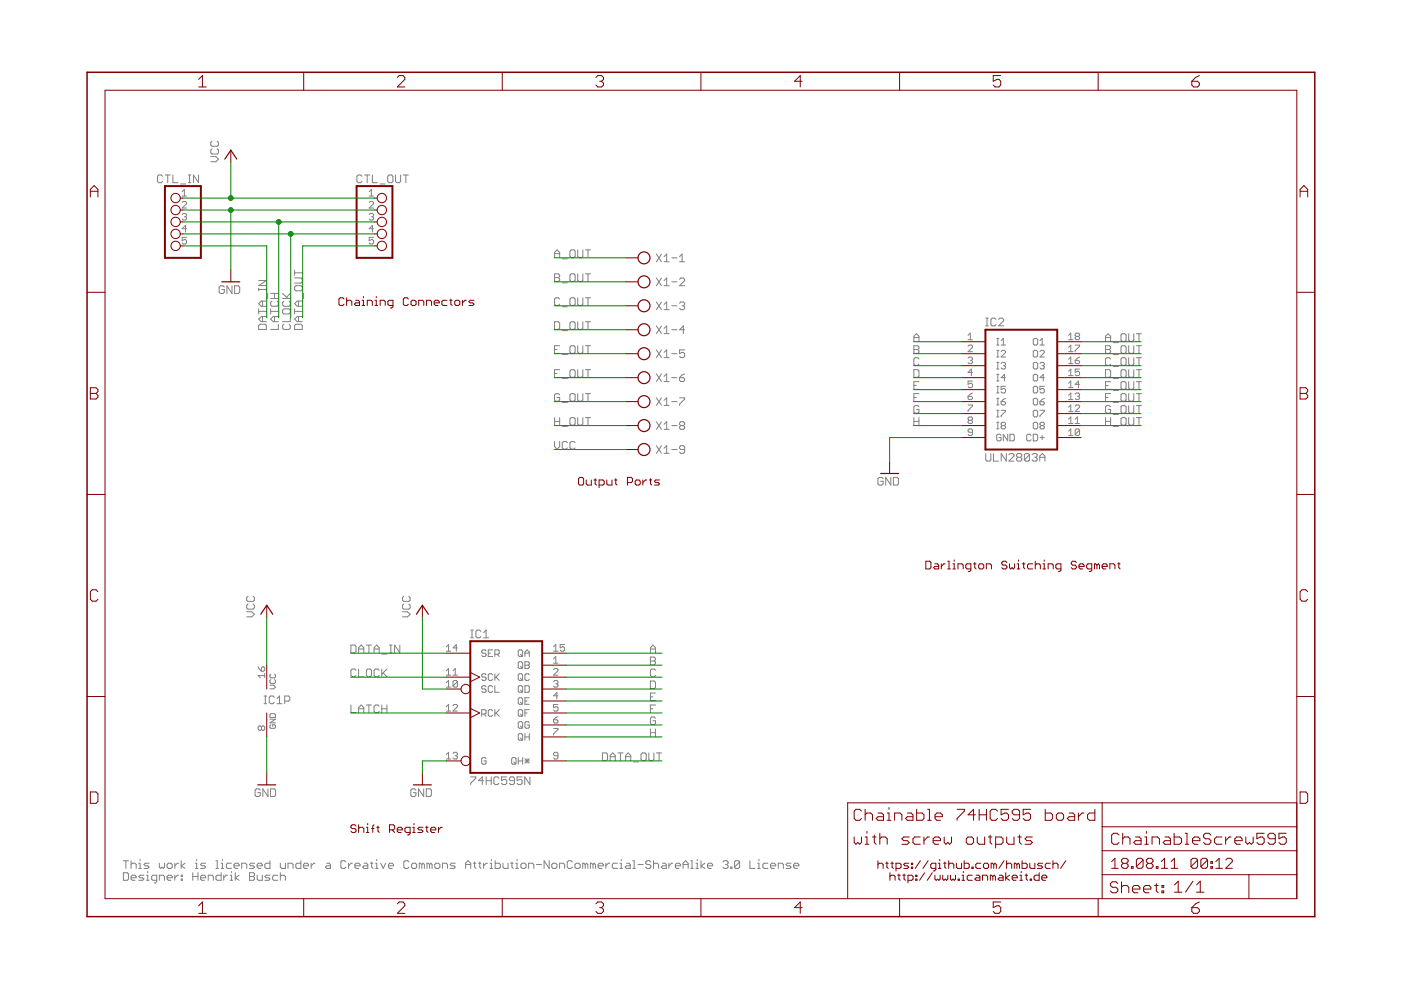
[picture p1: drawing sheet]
<svg xmlns="http://www.w3.org/2000/svg" width="297mm" height="210mm" viewBox="0 0 297 210" stroke-linecap="round" stroke-linejoin="round" font-family="sans-serif">
<g fill="#808080" stroke="#808080" stroke-width=".21">
<path d="M99.8 164.7h1.1z"/>
<path d="M100.9 164.7v.3z"/>
<path d="M100.9 165l-1.1 1.1z"/>
<path d="M99.8 166.1v.2z"/>
<path d="M102.3 164.7v1.6z"/>
<path d="M101.4 165.5l.9-.8z"/>
<path d="M101.4 165.5h1.1z"/>
<path d="M103.1 164.7v1.6z"/>
<path d="M103.1 165.5h1.1z"/>
<path d="M104.2 164.7v1.6z"/>
<path d="M105.5 164.7l.3 .3z"/>
<path d="M105 164.7h.5z"/>
<path d="M105 164.7l-.3 .3z"/>
<path d="M104.7 165v1.1z"/>
<path d="M104.7 166.1l.3 .2z"/>
<path d="M105 166.3h.5z"/>
<path d="M105.5 166.3l.3-.2z"/>
<path d="M106.3 164.7h1.1z"/>
<path d="M106.3 164.7v.8z"/>
<path d="M106.3 165.5l.6-.3z"/>
<path d="M106.9 165.2h.3z"/>
<path d="M107.2 165.2l.2 .3z"/>
<path d="M107.4 165.5v.6z"/>
<path d="M107.4 166.1l-.2 .2z"/>
<path d="M106.6 166.3h.6z"/>
<path d="M106.3 166.1l.3 .2z"/>
<path d="M108 166.1l.2 .2z"/>
<path d="M108.2 166.3h.6z"/>
<path d="M108.8 166.3l.3-.2z"/>
<path d="M109.1 165v1.1z"/>
<path d="M108.8 164.7l.3 .3z"/>
<path d="M108.2 164.7h.6z"/>
<path d="M108.2 164.7l-.2 .3z"/>
<path d="M108 165v.2z"/>
<path d="M108 165.2l.2 .3z"/>
<path d="M108.2 165.5h.9z"/>
<path d="M109.6 164.7h1.1z"/>
<path d="M109.6 164.7v.8z"/>
<path d="M109.6 165.5l.6-.3z"/>
<path d="M110.2 165.2h.2z"/>
<path d="M110.4 165.2l.3 .3z"/>
<path d="M110.7 165.5v.6z"/>
<path d="M110.7 166.1l-.3 .2z"/>
<path d="M109.9 166.3h.5z"/>
<path d="M109.6 166.1l.3 .2z"/>
<path d="M111.3 164.7v1.6z"/>
<path d="M111.3 164.7l1.1 1.6z"/>
<path d="M112.4 164.7v1.6z"/>
<path d="M54.9 167.3l.3 .2z"/>
<path d="M54.4 167.3h.5z"/>
<path d="M54.4 167.3l-.3 .2z"/>
<path d="M54.1 167.5v1.1z"/>
<path d="M54.1 168.6l.3 .3z"/>
<path d="M54.4 168.9h.5z"/>
<path d="M54.9 168.9l.3-.3z"/>
<path d="M55.2 168.1v.5z"/>
<path d="M54.6 168.1h.6z"/>
<path d="M55.7 167.3v1.6z"/>
<path d="M55.7 167.3l1.1 1.6z"/>
<path d="M56.8 167.3v1.6z"/>
<path d="M57.4 167.3v1.6z"/>
<path d="M57.4 168.9h.8z"/>
<path d="M58.4 168.6l-.2 .3z"/>
<path d="M58.4 167.5v1.1z"/>
<path d="M58.2 167.3l.2 .2z"/>
<path d="M57.4 167.3h.8z"/>
<path d="M47.3 60.6l.3 .3z"/>
<path d="M46.7 60.6h.6z"/>
<path d="M46.7 60.6l-.2 .3z"/>
<path d="M46.5 60.9v1.1z"/>
<path d="M46.5 62l.2 .2z"/>
<path d="M46.7 62.2h.6z"/>
<path d="M47.3 62.2l.3-.2z"/>
<path d="M47.6 61.4v.6z"/>
<path d="M47 61.4h.6z"/>
<path d="M48.1 60.6v1.6z"/>
<path d="M48.1 60.6l1.1 1.6z"/>
<path d="M49.2 60.6v1.6z"/>
<path d="M49.7 60.6v1.6z"/>
<path d="M49.7 62.2h.8z"/>
<path d="M50.5 62.2l.3-.2z"/>
<path d="M50.8 60.9v1.1z"/>
<path d="M50.5 60.6l.3 .3z"/>
<path d="M49.7 60.6h.8z"/>
<path d="M52.3 130.8h1.1z"/>
<path d="M53.4 130.8l.5-.6z"/>
<path d="M53.4 129.7l.5 .5z"/>
<path d="M52.3 129.7h1.1z"/>
<path d="M52.6 128.1l-.3 .2z"/>
<path d="M52.3 128.3v.6z"/>
<path d="M52.3 128.9l.3 .3z"/>
<path d="M52.6 129.2h1.1z"/>
<path d="M53.7 129.2l.2-.3z"/>
<path d="M53.9 128.3v.6z"/>
<path d="M53.7 128.1l.2 .2z"/>
<path d="M52.6 126.4l-.3 .3z"/>
<path d="M52.3 126.7v.6z"/>
<path d="M52.3 127.3l.3 .2z"/>
<path d="M52.6 127.5h1.1z"/>
<path d="M53.7 127.5l.2-.2z"/>
<path d="M53.9 126.7v.6z"/>
<path d="M53.7 126.4l.2 .3z"/>
<path d="M44.7 34.3h1.1z"/>
<path d="M46.3 33.7l-.5 .6z"/>
<path d="M45.8 33.2l.5 .5z"/>
<path d="M44.7 33.2h1.1z"/>
<path d="M45 31.6l-.3 .2z"/>
<path d="M44.7 31.8v.6z"/>
<path d="M44.7 32.4l.3 .3z"/>
<path d="M45 32.7h1z"/>
<path d="M46 32.7l.3-.3z"/>
<path d="M46.3 31.8v.6z"/>
<path d="M46 31.6l.3 .2z"/>
<path d="M44.7 30.2l.3-.3z"/>
<path d="M44.7 30.2v.6z"/>
<path d="M44.7 30.8l.3 .2z"/>
<path d="M45 31h1z"/>
<path d="M46 31l.3-.2z"/>
<path d="M46.3 30.2v.6z"/>
<path d="M46 29.9l.3 .3z"/>
<path d="M87.9 167.3l.3 .2z"/>
<path d="M87.4 167.3h.5z"/>
<path d="M87.4 167.3l-.3 .2z"/>
<path d="M87.1 167.5v1.1z"/>
<path d="M87.1 168.6l.3 .3z"/>
<path d="M87.4 168.9h.5z"/>
<path d="M88.2 168.6l-.3 .3z"/>
<path d="M88.2 168.1v.5z"/>
<path d="M87.6 168.1h.6z"/>
<path d="M88.7 167.3v1.6z"/>
<path d="M88.7 167.3l1.1 1.6z"/>
<path d="M89.8 167.3v1.6z"/>
<path d="M90.4 167.3v1.6z"/>
<path d="M90.4 168.9h.8z"/>
<path d="M91.2 168.9l.3-.3z"/>
<path d="M91.5 167.5v1.1z"/>
<path d="M91.2 167.3l.3 .2z"/>
<path d="M90.4 167.3h.8z"/>
<path d="M85.3 130.8h1.1z"/>
<path d="M86.4 130.8l.6-.6z"/>
<path d="M86.4 129.7l.6 .5z"/>
<path d="M85.3 129.7h1.1z"/>
<path d="M85.6 128.1l-.3 .2z"/>
<path d="M85.3 128.3v.6z"/>
<path d="M85.3 128.9l.3 .3z"/>
<path d="M85.6 129.2h1.1z"/>
<path d="M86.7 129.2l.3-.3z"/>
<path d="M87 128.3v.6z"/>
<path d="M86.7 128.1l.3 .2z"/>
<path d="M85.6 126.4l-.3 .3z"/>
<path d="M85.3 126.7v.6z"/>
<path d="M85.3 127.3l.3 .2z"/>
<path d="M85.6 127.5h1.1z"/>
<path d="M86.7 127.5l.3-.2z"/>
<path d="M87 126.7v.6z"/>
<path d="M86.7 126.4l.3 .3z"/>
<path d="M209 96.2v1.3z"/>
<path d="M209 97.5l.3 .3z"/>
<path d="M209.3 97.8h.5z"/>
<path d="M210.1 97.5l-.3 .3z"/>
<path d="M210.1 96.2v1.3z"/>
<path d="M210.6 96.2v1.6z"/>
<path d="M210.6 97.8h1.1z"/>
<path d="M212.3 96.2v1.6z"/>
<path d="M212.3 96.2l1.1 1.6z"/>
<path d="M213.4 96.2v1.6z"/>
<path d="M213.9 97.8h1.1z"/>
<path d="M213.9 97.8l1.1-1.1z"/>
<path d="M215 96.4v.3z"/>
<path d="M214.7 96.2l.3 .2z"/>
<path d="M214.2 96.2h.5z"/>
<path d="M213.9 96.4l.3-.2z"/>
<path d="M215.5 96.4l.3-.2z"/>
<path d="M215.8 96.2h.6z"/>
<path d="M216.4 96.2l.2 .2z"/>
<path d="M216.6 96.4v.3z"/>
<path d="M216.6 96.7l-.2 .3z"/>
<path d="M216.4 97l.2 .2z"/>
<path d="M216.6 97.2v.3z"/>
<path d="M216.4 97.8l.2-.3z"/>
<path d="M215.8 97.8h.6z"/>
<path d="M215.5 97.5l.3 .3z"/>
<path d="M215.5 97.2v.3z"/>
<path d="M215.5 97.2l.3-.2z"/>
<path d="M215.5 96.7l.3 .3z"/>
<path d="M215.5 96.4v.3z"/>
<path d="M215.8 97h.6z"/>
<path d="M217.2 96.4v1.1z"/>
<path d="M217.2 96.4l.3-.2z"/>
<path d="M217.5 96.2h.5z"/>
<path d="M218 96.2l.3 .2z"/>
<path d="M218.3 96.4v1.1z"/>
<path d="M218 97.8l.3-.3z"/>
<path d="M217.5 97.8h.5z"/>
<path d="M217.2 97.5l.3 .3z"/>
<path d="M218.3 96.4l-1.1 1.1z"/>
<path d="M218.8 96.4l.3-.2z"/>
<path d="M219.1 96.2h.5z"/>
<path d="M219.6 96.2l.3 .2z"/>
<path d="M219.9 96.4v.3z"/>
<path d="M219.9 96.7l-.3 .3z"/>
<path d="M219.4 97h.2z"/>
<path d="M219.6 97l.3 .2z"/>
<path d="M219.9 97.2v.3z"/>
<path d="M219.9 97.5l-.3 .3z"/>
<path d="M219.1 97.8h.5z"/>
<path d="M218.8 97.5l.3 .3z"/>
<path d="M220.4 96.7v1.1z"/>
<path d="M220.4 96.7l.6-.5z"/>
<path d="M221 96.2l.5 .5z"/>
<path d="M221.5 96.7v1.1z"/>
<path d="M220.4 97h1.1z"/>
<path d="M187 101.2l.2 .3z"/>
<path d="M186.4 101.2h.6z"/>
<path d="M186.4 101.2l-.3 .3z"/>
<path d="M186.1 101.5v1.1z"/>
<path d="M186.1 102.6l.3 .2z"/>
<path d="M186.4 102.8h.6z"/>
<path d="M187 102.8l.2-.2z"/>
<path d="M187.2 102v.6z"/>
<path d="M186.7 102h.5z"/>
<path d="M187.8 101.2v1.6z"/>
<path d="M187.8 101.2l1.1 1.6z"/>
<path d="M188.9 101.2v1.6z"/>
<path d="M189.4 101.2v1.6z"/>
<path d="M189.4 102.8h.8z"/>
<path d="M190.2 102.8l.3-.2z"/>
<path d="M190.5 101.5v1.1z"/>
<path d="M190.2 101.2l.3 .3z"/>
<path d="M189.4 101.2h.8z"/>
<path d="M26.7 182.5v1.6z"/>
<path d="M26.2 182.5h1z"/>
<path d="M27.8 182.5v1.6z"/>
<path d="M27.8 183.3l.3-.3z"/>
<path d="M28.1 183h.5z"/>
<path d="M28.6 183l.3 .3z"/>
<path d="M28.9 183.3v.8z"/>
<path d="M29.4 183h.3z"/>
<path d="M29.7 183v1.1z"/>
<path d="M29.4 184.1h.6z"/>
<path d="M29.7 182.2v.3z"/>
<path d="M30.5 184.1h.8z"/>
<path d="M31.3 184.1l.3-.2z"/>
<path d="M31.3 183.6l.3 .3z"/>
<path d="M30.8 183.6h.5z"/>
<path d="M30.5 183.3l.3 .3z"/>
<path d="M30.5 183.3l.3-.3z"/>
<path d="M30.8 183h.8z"/>
<path d="M33.8 183v.9z"/>
<path d="M33.8 183.9l.3 .2z"/>
<path d="M34.3 183.9l-.2 .2z"/>
<path d="M34.3 183.9l.3 .2z"/>
<path d="M34.6 184.1l.3-.2z"/>
<path d="M34.9 183v.9z"/>
<path d="M35.7 184.1h.5z"/>
<path d="M36.5 183.9l-.3 .2z"/>
<path d="M36.5 183.3v.6z"/>
<path d="M36.2 183l.3 .3z"/>
<path d="M35.7 183h.5z"/>
<path d="M35.7 183l-.3 .3z"/>
<path d="M35.4 183.3v.6z"/>
<path d="M35.4 183.9l.3 .2z"/>
<path d="M37.1 183v1.1z"/>
<path d="M37.1 183.6l.5-.6z"/>
<path d="M37.6 183h.3z"/>
<path d="M38.4 182.5v1.6z"/>
<path d="M38.4 183.6l.8 .5z"/>
<path d="M38.4 183.6l.8-.6z"/>
<path d="M41.4 183h.3z"/>
<path d="M41.7 183v1.1z"/>
<path d="M41.4 184.1h.6z"/>
<path d="M41.7 182.2v.3z"/>
<path d="M42.5 184.1h.8z"/>
<path d="M43.6 183.9l-.3 .2z"/>
<path d="M43.3 183.6l.3 .3z"/>
<path d="M42.8 183.6h.5z"/>
<path d="M42.5 183.3l.3 .3z"/>
<path d="M42.5 183.3l.3-.3z"/>
<path d="M42.8 183h.8z"/>
<path d="M45.8 182.5h.3z"/>
<path d="M46.1 182.5v1.6z"/>
<path d="M45.8 184.1h.5z"/>
<path d="M46.9 183h.3z"/>
<path d="M47.2 183v1.1z"/>
<path d="M46.9 184.1h.5z"/>
<path d="M47.2 182.2v.3z"/>
<path d="M48.2 183h.9z"/>
<path d="M48.2 183l-.2 .3z"/>
<path d="M48 183.3v.6z"/>
<path d="M48 183.9l.2 .2z"/>
<path d="M48.2 184.1h.9z"/>
<path d="M49.9 184.1h.5z"/>
<path d="M49.6 183.9l.3 .2z"/>
<path d="M49.6 183.3v.6z"/>
<path d="M49.6 183.3l.3-.3z"/>
<path d="M49.9 183h.5z"/>
<path d="M50.4 183l.3 .3z"/>
<path d="M50.7 183.3v.3z"/>
<path d="M49.6 183.6h1.1z"/>
<path d="M51.2 183v1.1z"/>
<path d="M51.2 183h.9z"/>
<path d="M52.1 183l.2 .3z"/>
<path d="M52.3 183.3v.8z"/>
<path d="M52.9 184.1h.8z"/>
<path d="M54 183.9l-.3 .2z"/>
<path d="M53.7 183.6l.3 .3z"/>
<path d="M53.1 183.6h.6z"/>
<path d="M52.9 183.3l.2 .3z"/>
<path d="M53.1 183l-.2 .3z"/>
<path d="M53.1 183h.9z"/>
<path d="M54.8 184.1h.5z"/>
<path d="M54.5 183.9l.3 .2z"/>
<path d="M54.5 183.3v.6z"/>
<path d="M54.5 183.3l.3-.3z"/>
<path d="M54.8 183h.5z"/>
<path d="M55.3 183l.3 .3z"/>
<path d="M55.6 183.3v.3z"/>
<path d="M54.5 183.6h1.1z"/>
<path d="M57.2 182.5v1.6z"/>
<path d="M56.4 184.1h.8z"/>
<path d="M56.2 183.9l.2 .2z"/>
<path d="M56.2 183.3v.6z"/>
<path d="M56.2 183.3l.2-.3z"/>
<path d="M56.4 183h.8z"/>
<path d="M59.4 183v.9z"/>
<path d="M59.4 183.9l.3 .2z"/>
<path d="M59.7 184.1h.8z"/>
<path d="M60.5 183v1.1z"/>
<path d="M61.1 183v1.1z"/>
<path d="M61.1 183h.8z"/>
<path d="M61.9 183l.2 .3z"/>
<path d="M62.1 183.3v.8z"/>
<path d="M63.8 182.5v1.6z"/>
<path d="M63 184.1h.8z"/>
<path d="M62.7 183.9l.3 .2z"/>
<path d="M62.7 183.3v.6z"/>
<path d="M63 183l-.3 .3z"/>
<path d="M63 183h.8z"/>
<path d="M64.6 184.1h.5z"/>
<path d="M64.3 183.9l.3 .2z"/>
<path d="M64.3 183.3v.6z"/>
<path d="M64.3 183.3l.3-.3z"/>
<path d="M64.6 183h.5z"/>
<path d="M65.1 183l.3 .3z"/>
<path d="M65.4 183.3v.3z"/>
<path d="M64.3 183.6h1.1z"/>
<path d="M66 183v1.1z"/>
<path d="M66 183.6l.5-.6z"/>
<path d="M66.5 183h.3z"/>
<path d="M69.3 183h.5z"/>
<path d="M69.8 183l.3 .3z"/>
<path d="M70.1 183.3v.8z"/>
<path d="M69.3 184.1h.8z"/>
<path d="M69 183.9l.3 .2z"/>
<path d="M69 183.9l.3-.3z"/>
<path d="M69.3 183.6h.8z"/>
<path d="M73.1 182.5l.2 .2z"/>
<path d="M72.5 182.5h.6z"/>
<path d="M72.3 182.7l.2-.2z"/>
<path d="M72.3 182.7v1.2z"/>
<path d="M72.3 183.9l.2 .2z"/>
<path d="M72.5 184.1h.6z"/>
<path d="M73.1 184.1l.2-.2z"/>
<path d="M73.9 183v1.1z"/>
<path d="M73.9 183.6l.5-.6z"/>
<path d="M74.4 183h.3z"/>
<path d="M75.5 184.1h.6z"/>
<path d="M75.2 183.9l.3 .2z"/>
<path d="M75.2 183.3v.6z"/>
<path d="M75.2 183.3l.3-.3z"/>
<path d="M75.5 183h.6z"/>
<path d="M76.1 183l.2 .3z"/>
<path d="M76.3 183.3v.3z"/>
<path d="M75.2 183.6h1.1z"/>
<path d="M77.2 183h.5z"/>
<path d="M77.7 183l.3 .3z"/>
<path d="M78 183.3v.8z"/>
<path d="M77.2 184.1h.8z"/>
<path d="M76.9 183.9l.3 .2z"/>
<path d="M76.9 183.9l.3-.3z"/>
<path d="M77.2 183.6h.8z"/>
<path d="M78.8 182.7v1.2z"/>
<path d="M78.8 183.9l.3 .2z"/>
<path d="M78.5 183h.6z"/>
<path d="M79.6 183h.3z"/>
<path d="M79.9 183v1.1z"/>
<path d="M79.6 184.1h.6z"/>
<path d="M79.9 182.2v.3z"/>
<path d="M80.7 183l.6 1.1z"/>
<path d="M81.8 183l-.5 1.1z"/>
<path d="M82.6 184.1h.6z"/>
<path d="M82.4 183.9l.2 .2z"/>
<path d="M82.4 183.3v.6z"/>
<path d="M82.6 183l-.2 .3z"/>
<path d="M82.6 183h.6z"/>
<path d="M83.2 183l.2 .3z"/>
<path d="M83.4 183.3v.3z"/>
<path d="M82.4 183.6h1z"/>
<path d="M86.4 182.5l.3 .2z"/>
<path d="M85.9 182.5h.5z"/>
<path d="M85.6 182.7l.3-.2z"/>
<path d="M85.6 182.7v1.2z"/>
<path d="M85.6 183.9l.3 .2z"/>
<path d="M85.9 184.1h.5z"/>
<path d="M86.7 183.9l-.3 .2z"/>
<path d="M87.5 184.1h.6z"/>
<path d="M88.1 184.1l.2-.2z"/>
<path d="M88.3 183.3v.6z"/>
<path d="M88.1 183l.2 .3z"/>
<path d="M87.5 183h.6z"/>
<path d="M87.5 183l-.2 .3z"/>
<path d="M87.3 183.3v.6z"/>
<path d="M87.3 183.9l.2 .2z"/>
<path d="M88.9 183v1.1z"/>
<path d="M88.9 183h.3z"/>
<path d="M89.2 183l.2 .3z"/>
<path d="M89.4 183.3v.8z"/>
<path d="M89.4 183.3l.3-.3z"/>
<path d="M89.7 183l.3 .3z"/>
<path d="M90 183.3v.8z"/>
<path d="M90.5 183v1.1z"/>
<path d="M90.5 183h.3z"/>
<path d="M90.8 183l.3 .3z"/>
<path d="M91.1 183.3v.8z"/>
<path d="M91.1 183.3l.3-.3z"/>
<path d="M91.4 183l.2 .3z"/>
<path d="M91.6 183.3v.8z"/>
<path d="M92.4 184.1h.6z"/>
<path d="M93.3 183.9l-.3 .2z"/>
<path d="M93.3 183.3v.6z"/>
<path d="M93 183l.3 .3z"/>
<path d="M92.4 183h.6z"/>
<path d="M92.4 183l-.2 .3z"/>
<path d="M92.2 183.3v.6z"/>
<path d="M92.2 183.9l.2 .2z"/>
<path d="M93.8 183v1.1z"/>
<path d="M93.8 183h.8z"/>
<path d="M94.6 183l.3 .3z"/>
<path d="M94.9 183.3v.8z"/>
<path d="M95.4 184.1h.9z"/>
<path d="M96.5 183.9l-.2 .2z"/>
<path d="M96.3 183.6l.2 .3z"/>
<path d="M95.7 183.6h.6z"/>
<path d="M95.4 183.3l.3 .3z"/>
<path d="M95.4 183.3l.3-.3z"/>
<path d="M95.7 183h.8z"/>
<path d="M98.7 183v1.1z"/>
<path d="M99.2 182.5l-.5 .5z"/>
<path d="M99.2 182.5l.6 .5z"/>
<path d="M99.8 183v1.1z"/>
<path d="M98.7 183.3h1.1z"/>
<path d="M100.6 182.7v1.2z"/>
<path d="M100.6 183.9l.3 .2z"/>
<path d="M100.3 183h.6z"/>
<path d="M101.7 182.7v1.2z"/>
<path d="M101.7 183.9l.3 .2z"/>
<path d="M101.5 183h.5z"/>
<path d="M102.5 183v1.1z"/>
<path d="M102.5 183.6l.6-.6z"/>
<path d="M103.1 183h.3z"/>
<path d="M103.9 183h.3z"/>
<path d="M104.2 183v1.1z"/>
<path d="M103.9 184.1h.5z"/>
<path d="M104.2 182.2v.3z"/>
<path d="M105 182.5v1.6z"/>
<path d="M105 184.1h.8z"/>
<path d="M105.8 184.1l.3-.2z"/>
<path d="M106.1 183.3v.6z"/>
<path d="M105.8 183l.3 .3z"/>
<path d="M105 183h.8z"/>
<path d="M106.6 183v.9z"/>
<path d="M106.6 183.9l.3 .2z"/>
<path d="M106.9 184.1h.8z"/>
<path d="M107.7 183v1.1z"/>
<path d="M108.5 182.7v1.2z"/>
<path d="M108.5 183.9l.3 .2z"/>
<path d="M108.3 183h.5z"/>
<path d="M109.3 183h.3z"/>
<path d="M109.6 183v1.1z"/>
<path d="M109.3 184.1h.6z"/>
<path d="M109.6 182.2v.3z"/>
<path d="M110.7 184.1h.6z"/>
<path d="M111.5 183.9l-.2 .2z"/>
<path d="M111.5 183.3v.6z"/>
<path d="M111.3 183l.2 .3z"/>
<path d="M110.7 183h.6z"/>
<path d="M110.7 183l-.3 .3z"/>
<path d="M110.4 183.3v.6z"/>
<path d="M110.4 183.9l.3 .2z"/>
<path d="M112.1 183v1.1z"/>
<path d="M112.1 183h.8z"/>
<path d="M112.9 183l.3 .3z"/>
<path d="M113.2 183.3v.8z"/>
<path d="M113.7 183.3h1.1z"/>
<path d="M115.4 182.5v1.6z"/>
<path d="M115.4 182.5l1 1.6z"/>
<path d="M116.4 182.5v1.6z"/>
<path d="M117.3 184.1h.5z"/>
<path d="M117.8 184.1l.3-.2z"/>
<path d="M118.1 183.3v.6z"/>
<path d="M117.8 183l.3 .3z"/>
<path d="M117.3 183h.5z"/>
<path d="M117.3 183l-.3 .3z"/>
<path d="M117 183.3v.6z"/>
<path d="M117 183.9l.3 .2z"/>
<path d="M118.6 183v1.1z"/>
<path d="M118.6 183h.8z"/>
<path d="M119.4 183l.3 .3z"/>
<path d="M119.7 183.3v.8z"/>
<path d="M121.1 182.5l.2 .2z"/>
<path d="M120.5 182.5h.6z"/>
<path d="M120.3 182.7l.2-.2z"/>
<path d="M120.3 182.7v1.2z"/>
<path d="M120.3 183.9l.2 .2z"/>
<path d="M120.5 184.1h.6z"/>
<path d="M121.3 183.9l-.2 .2z"/>
<path d="M122.2 184.1h.5z"/>
<path d="M122.7 184.1l.3-.2z"/>
<path d="M123 183.3v.6z"/>
<path d="M122.7 183l.3 .3z"/>
<path d="M122.2 183h.5z"/>
<path d="M122.2 183l-.3 .3z"/>
<path d="M121.9 183.3v.6z"/>
<path d="M121.9 183.9l.3 .2z"/>
<path d="M123.5 183v1.1z"/>
<path d="M123.5 183h.3z"/>
<path d="M123.8 183l.3 .3z"/>
<path d="M124.1 183.3v.8z"/>
<path d="M124.1 183.3l.3-.3z"/>
<path d="M124.4 183l.2 .3z"/>
<path d="M124.6 183.3v.8z"/>
<path d="M125.2 183v1.1z"/>
<path d="M125.2 183h.3z"/>
<path d="M125.5 183l.2 .3z"/>
<path d="M125.7 183.3v.8z"/>
<path d="M126 183l-.3 .3z"/>
<path d="M126 183l.3 .3z"/>
<path d="M126.3 183.3v.8z"/>
<path d="M127.1 184.1h.5z"/>
<path d="M126.8 183.9l.3 .2z"/>
<path d="M126.8 183.3v.6z"/>
<path d="M126.8 183.3l.3-.3z"/>
<path d="M127.1 183h.5z"/>
<path d="M127.6 183l.3 .3z"/>
<path d="M127.9 183.3v.3z"/>
<path d="M126.8 183.6h1.1z"/>
<path d="M128.5 183v1.1z"/>
<path d="M129 183l-.5 .6z"/>
<path d="M129 183h.3z"/>
<path d="M130.1 183h.8z"/>
<path d="M130.1 183l-.3 .3z"/>
<path d="M129.8 183.3v.6z"/>
<path d="M129.8 183.9l.3 .2z"/>
<path d="M130.1 184.1h.8z"/>
<path d="M131.4 183h.3z"/>
<path d="M131.7 183v1.1z"/>
<path d="M131.4 184.1h.6z"/>
<path d="M131.7 182.2v.3z"/>
<path d="M132.8 183h.5z"/>
<path d="M133.3 183l.3 .3z"/>
<path d="M133.6 183.3v.8z"/>
<path d="M132.8 184.1h.8z"/>
<path d="M132.5 183.9l.3 .2z"/>
<path d="M132.5 183.9l.3-.3z"/>
<path d="M132.8 183.6h.8z"/>
<path d="M134.2 182.5h.2z"/>
<path d="M134.4 182.5v1.6z"/>
<path d="M134.2 184.1h.5z"/>
<path d="M135.3 183.3h1.1z"/>
<path d="M137.7 182.5l.3 .2z"/>
<path d="M137.2 182.5h.5z"/>
<path d="M136.9 182.7l.3-.2z"/>
<path d="M136.9 182.7v.3z"/>
<path d="M136.9 183l.3 .3z"/>
<path d="M137.2 183.3h.5z"/>
<path d="M137.7 183.3l.3 .3z"/>
<path d="M138 183.6v.3z"/>
<path d="M138 183.9l-.3 .2z"/>
<path d="M137.2 184.1h.5z"/>
<path d="M136.9 183.9l.3 .2z"/>
<path d="M138.6 182.5v1.6z"/>
<path d="M138.8 183l-.2 .3z"/>
<path d="M138.8 183h.6z"/>
<path d="M139.4 183l.2 .3z"/>
<path d="M139.6 183.3v.8z"/>
<path d="M140.5 183h.5z"/>
<path d="M141 183l.3 .3z"/>
<path d="M141.3 183.3v.8z"/>
<path d="M140.5 184.1h.8z"/>
<path d="M140.2 183.9l.3 .2z"/>
<path d="M140.2 183.9l.3-.3z"/>
<path d="M140.5 183.6h.8z"/>
<path d="M141.8 183v1.1z"/>
<path d="M141.8 183.6l.6-.6z"/>
<path d="M142.4 183h.2z"/>
<path d="M143.4 184.1h.6z"/>
<path d="M143.2 183.9l.2 .2z"/>
<path d="M143.2 183.3v.6z"/>
<path d="M143.4 183l-.2 .3z"/>
<path d="M143.4 183h.6z"/>
<path d="M144 183l.3 .3z"/>
<path d="M144.3 183.3v.3z"/>
<path d="M143.2 183.6h1.1z"/>
<path d="M144.8 183v1.1z"/>
<path d="M144.8 183l.6-.5z"/>
<path d="M145.4 182.5l.5 .5z"/>
<path d="M145.9 183v1.1z"/>
<path d="M144.8 183.3h1.1z"/>
<path d="M146.4 182.5h.3z"/>
<path d="M146.7 182.5v1.6z"/>
<path d="M146.4 184.1h.6z"/>
<path d="M147.6 183h.2z"/>
<path d="M147.8 183v1.1z"/>
<path d="M147.6 184.1h.5z"/>
<path d="M147.8 182.2v.3z"/>
<path d="M148.6 182.5v1.6z"/>
<path d="M148.6 183.6l.9 .5z"/>
<path d="M148.6 183.6l.9-.6z"/>
<path d="M150.3 184.1h.5z"/>
<path d="M150 183.9l.3 .2z"/>
<path d="M150 183.3v.6z"/>
<path d="M150 183.3l.3-.3z"/>
<path d="M150.3 183h.5z"/>
<path d="M150.8 183l.3 .3z"/>
<path d="M151.1 183.3v.3z"/>
<path d="M150 183.6h1.1z"/>
<path d="M153.3 182.7l.2-.2z"/>
<path d="M153.5 182.5h.6z"/>
<path d="M154.1 182.5l.3 .2z"/>
<path d="M154.4 182.7v.3z"/>
<path d="M154.4 183l-.3 .3z"/>
<path d="M153.8 183.3h.3z"/>
<path d="M154.1 183.3l.3 .3z"/>
<path d="M154.4 183.6v.3z"/>
<path d="M154.4 183.9l-.3 .2z"/>
<path d="M153.5 184.1h.6z"/>
<path d="M153.3 183.9l.2 .2z"/>
<path d="M154.9 183.9v.2z"/>
<path d="M154.9 183.9h.3z"/>
<path d="M155.2 183.9v.2z"/>
<path d="M154.9 184.1h.3z"/>
<path d="M155.7 182.7v1.2z"/>
<path d="M155.7 182.7l.3-.2z"/>
<path d="M156 182.5h.5z"/>
<path d="M156.5 182.5l.3 .2z"/>
<path d="M156.8 182.7v1.2z"/>
<path d="M156.8 183.9l-.3 .2z"/>
<path d="M156 184.1h.5z"/>
<path d="M155.7 183.9l.3 .2z"/>
<path d="M156.8 182.7l-1.1 1.2z"/>
<path d="M159 182.5v1.6z"/>
<path d="M159 184.1h1.1z"/>
<path d="M160.7 183h.2z"/>
<path d="M160.9 183v1.1z"/>
<path d="M160.7 184.1h.5z"/>
<path d="M160.9 182.2v.3z"/>
<path d="M162 183h.8z"/>
<path d="M162 183l-.3 .3z"/>
<path d="M161.7 183.3v.6z"/>
<path d="M161.7 183.9l.3 .2z"/>
<path d="M162 184.1h.8z"/>
<path d="M163.6 184.1h.6z"/>
<path d="M163.4 183.9l.2 .2z"/>
<path d="M163.4 183.3v.6z"/>
<path d="M163.4 183.3l.2-.3z"/>
<path d="M163.6 183h.6z"/>
<path d="M164.2 183l.3 .3z"/>
<path d="M164.5 183.3v.3z"/>
<path d="M163.4 183.6h1.1z"/>
<path d="M165 183v1.1z"/>
<path d="M165 183h.8z"/>
<path d="M165.8 183l.3 .3z"/>
<path d="M166.1 183.3v.8z"/>
<path d="M166.6 184.1h.8z"/>
<path d="M167.7 183.9l-.3 .2z"/>
<path d="M167.4 183.6l.3 .3z"/>
<path d="M166.9 183.6h.5z"/>
<path d="M166.6 183.3l.3 .3z"/>
<path d="M166.6 183.3l.3-.3z"/>
<path d="M166.9 183h.8z"/>
<path d="M168.5 184.1h.6z"/>
<path d="M168.3 183.9l.2 .2z"/>
<path d="M168.3 183.3v.6z"/>
<path d="M168.3 183.3l.2-.3z"/>
<path d="M168.5 183h.6z"/>
<path d="M169.1 183l.3 .3z"/>
<path d="M169.4 183.3v.3z"/>
<path d="M168.3 183.6h1.1z"/>
<path d="M26.2 185v1.6z"/>
<path d="M26.2 186.6h.8z"/>
<path d="M27 186.6l.2-.2z"/>
<path d="M27.2 185.3v1.1z"/>
<path d="M27 185l.2 .3z"/>
<path d="M26.2 185h.8z"/>
<path d="M28.1 186.6h.5z"/>
<path d="M27.8 186.4l.3 .2z"/>
<path d="M27.8 185.8v.6z"/>
<path d="M27.8 185.8l.3-.2z"/>
<path d="M28.1 185.6h.5z"/>
<path d="M28.6 185.6l.3 .2z"/>
<path d="M28.9 185.8v.3z"/>
<path d="M27.8 186.1h1.1z"/>
<path d="M29.4 186.6h.8z"/>
<path d="M30.2 186.6l.3-.2z"/>
<path d="M30.2 186.1l.3 .3z"/>
<path d="M29.7 186.1h.5z"/>
<path d="M29.4 185.8l.3 .3z"/>
<path d="M29.4 185.8l.3-.2z"/>
<path d="M29.7 185.6h.8z"/>
<path d="M31.1 185.6h.2z"/>
<path d="M31.3 185.6v1z"/>
<path d="M31.1 186.6h.5z"/>
<path d="M31.3 184.8v.2z"/>
<path d="M32.7 187.2h.3z"/>
<path d="M33.2 186.9l-.2 .3z"/>
<path d="M33.2 185.6v1.3z"/>
<path d="M32.4 185.6h.8z"/>
<path d="M32.4 185.6l-.2 .2z"/>
<path d="M32.2 185.8v.6z"/>
<path d="M32.2 186.4l.2 .2z"/>
<path d="M32.4 186.6h.8z"/>
<path d="M33.8 185.6v1z"/>
<path d="M33.8 185.6h.8z"/>
<path d="M34.6 185.6l.3 .2z"/>
<path d="M34.9 185.8v.8z"/>
<path d="M35.7 186.6h.5z"/>
<path d="M35.4 186.4l.3 .2z"/>
<path d="M35.4 185.8v.6z"/>
<path d="M35.4 185.8l.3-.2z"/>
<path d="M35.7 185.6h.5z"/>
<path d="M36.2 185.6l.3 .2z"/>
<path d="M36.5 185.8v.3z"/>
<path d="M35.4 186.1h1.1z"/>
<path d="M37.1 185.6v1z"/>
<path d="M37.1 186.1l.5-.5z"/>
<path d="M37.6 185.6h.3z"/>
<path d="M38.4 185.6h.3z"/>
<path d="M38.7 185.6v.2z"/>
<path d="M38.4 185.8h.3z"/>
<path d="M38.4 185.6v.2z"/>
<path d="M38.4 186.4h.3z"/>
<path d="M38.7 186.4v.2z"/>
<path d="M38.4 186.6h.3z"/>
<path d="M38.4 186.4v.2z"/>
<path d="M40.9 185v1.6z"/>
<path d="M40.9 185.8h1.1z"/>
<path d="M42 185v1.6z"/>
<path d="M42.8 186.6h.5z"/>
<path d="M42.5 186.4l.3 .2z"/>
<path d="M42.5 185.8v.6z"/>
<path d="M42.5 185.8l.3-.2z"/>
<path d="M42.8 185.6h.5z"/>
<path d="M43.3 185.6l.3 .2z"/>
<path d="M43.6 185.8v.3z"/>
<path d="M42.5 186.1h1.1z"/>
<path d="M44.2 185.6v1z"/>
<path d="M44.2 185.6h.8z"/>
<path d="M45 185.6l.2 .2z"/>
<path d="M45.2 185.8v.8z"/>
<path d="M46.9 185v1.6z"/>
<path d="M46.1 186.6h.8z"/>
<path d="M45.8 186.4l.3 .2z"/>
<path d="M45.8 185.8v.6z"/>
<path d="M45.8 185.8l.3-.2z"/>
<path d="M46.1 185.6h.8z"/>
<path d="M47.4 185.6v1z"/>
<path d="M48 185.6l-.6 .5z"/>
<path d="M48 185.6h.2z"/>
<path d="M48.8 185.6h.3z"/>
<path d="M49.1 185.6v1z"/>
<path d="M48.8 186.6h.5z"/>
<path d="M49.1 184.8v.2z"/>
<path d="M49.9 185v1.6z"/>
<path d="M49.9 186.1l.8 .5z"/>
<path d="M49.9 186.1l.8-.5z"/>
<path d="M52.9 185v1.6z"/>
<path d="M52.9 185h.8z"/>
<path d="M53.7 185l.3 .3z"/>
<path d="M54 185.3v.3z"/>
<path d="M54 185.6l-.3 .2z"/>
<path d="M53.7 185.8l.3 .3z"/>
<path d="M54 186.1v.3z"/>
<path d="M53.7 186.6l.3-.2z"/>
<path d="M52.9 186.6h.8z"/>
<path d="M52.9 185.8h.8z"/>
<path d="M54.5 185.6v.8z"/>
<path d="M54.5 186.4l.3 .2z"/>
<path d="M54.8 186.6h.8z"/>
<path d="M55.6 185.6v1z"/>
<path d="M56.2 186.6h.8z"/>
<path d="M57 186.6l.2-.2z"/>
<path d="M57 186.1l.2 .3z"/>
<path d="M56.4 186.1h.6z"/>
<path d="M56.2 185.8l.2 .3z"/>
<path d="M56.2 185.8l.2-.2z"/>
<path d="M56.4 185.6h.8z"/>
<path d="M58.1 185.6h.8z"/>
<path d="M58.1 185.6l-.3 .2z"/>
<path d="M57.8 185.8v.6z"/>
<path d="M57.8 186.4l.3 .2z"/>
<path d="M58.1 186.6h.8z"/>
<path d="M59.4 185v1.6z"/>
<path d="M59.4 185.8l.3-.2z"/>
<path d="M59.7 185.6h.5z"/>
<path d="M60.2 185.6l.3 .2z"/>
<path d="M60.5 185.8v.8z"/>
<path d="M109.9 140.5v1z"/>
<path d="M109.9 140.5l.2-.2z"/>
<path d="M110.1 140.3h.5z"/>
<path d="M110.6 140.3l.2 .2z"/>
<path d="M110.8 140.5v1z"/>
<path d="M110.8 141.5l-.2 .2z"/>
<path d="M110.1 141.7h.5z"/>
<path d="M109.9 141.5l.2 .2z"/>
<path d="M110.3 141.3l.5 .4z"/>
<path d="M111.3 140.3v1.4z"/>
<path d="M111.3 140.3h.7z"/>
<path d="M112 140.3l.2 .2z"/>
<path d="M112.2 140.5v.3z"/>
<path d="M112.2 140.8l-.2 .2z"/>
<path d="M112 141l.2 .3z"/>
<path d="M112.2 141.3v.2z"/>
<path d="M112.2 141.5l-.2 .2z"/>
<path d="M111.3 141.7h.7z"/>
<path d="M111.3 141h.7z"/>
<path d="M117.4 139.7l.4-.5z"/>
<path d="M117.8 139.2v1.4z"/>
<path d="M117.4 140.6h.9z"/>
<path d="M109.9 143.1v.9z"/>
<path d="M109.9 143.1l.2-.2z"/>
<path d="M110.1 142.9h.5z"/>
<path d="M110.6 142.9l.2 .2z"/>
<path d="M110.8 143.1v.9z"/>
<path d="M110.8 144l-.2 .3z"/>
<path d="M110.1 144.3h.5z"/>
<path d="M109.9 144l.2 .3z"/>
<path d="M110.3 143.8l.5 .5z"/>
<path d="M112 142.9l.2 .2z"/>
<path d="M111.5 142.9h.5z"/>
<path d="M111.5 142.9l-.2 .2z"/>
<path d="M111.3 143.1v.9z"/>
<path d="M111.3 144l.2 .3z"/>
<path d="M111.5 144.3h.5z"/>
<path d="M112.2 144l-.2 .3z"/>
<path d="M117.4 143.1h.9z"/>
<path d="M117.4 143.1l.9-.9z"/>
<path d="M118.3 142v.2z"/>
<path d="M118.1 141.8l.2 .2z"/>
<path d="M117.6 141.8h.5z"/>
<path d="M117.6 141.8l-.2 .2z"/>
<path d="M109.9 145.6v1z"/>
<path d="M109.9 145.6l.2-.2z"/>
<path d="M110.1 145.4h.5z"/>
<path d="M110.6 145.4l.2 .2z"/>
<path d="M110.8 145.6v1z"/>
<path d="M110.8 146.6l-.2 .2z"/>
<path d="M110.1 146.8h.5z"/>
<path d="M109.9 146.6l.2 .2z"/>
<path d="M110.3 146.3l.5 .5z"/>
<path d="M111.3 145.4v1.4z"/>
<path d="M111.3 146.8h.7z"/>
<path d="M112 146.8l.2-.2z"/>
<path d="M112.2 145.6v1z"/>
<path d="M112 145.4l.2 .2z"/>
<path d="M111.3 145.4h.7z"/>
<path d="M117.4 144.5l.2-.2z"/>
<path d="M117.6 144.3h.5z"/>
<path d="M118.1 144.3l.2 .2z"/>
<path d="M118.3 144.5v.3z"/>
<path d="M118.3 144.8l-.2 .2z"/>
<path d="M117.8 145h.3z"/>
<path d="M118.1 145l.2 .2z"/>
<path d="M118.3 145.2v.3z"/>
<path d="M118.3 145.5l-.2 .2z"/>
<path d="M117.6 145.7h.5z"/>
<path d="M117.4 145.5l.2 .2z"/>
<path d="M109.9 148.2v.9z"/>
<path d="M109.9 148.2l.2-.3z"/>
<path d="M110.1 147.9h.5z"/>
<path d="M110.6 147.9l.2 .3z"/>
<path d="M110.8 148.2v.9z"/>
<path d="M110.8 149.1l-.2 .2z"/>
<path d="M110.1 149.3h.5z"/>
<path d="M109.9 149.1l.2 .2z"/>
<path d="M110.3 148.9l.5 .4z"/>
<path d="M111.3 147.9h.9z"/>
<path d="M111.3 147.9v1.4z"/>
<path d="M111.3 149.3h.9z"/>
<path d="M111.3 148.6h.5z"/>
<path d="M118.1 146.8v1.4z"/>
<path d="M118.1 146.8l-.7 .7z"/>
<path d="M117.4 147.5h.9z"/>
<path d="M109.9 150.7v.9z"/>
<path d="M109.9 150.7l.2-.2z"/>
<path d="M110.1 150.5h.5z"/>
<path d="M110.6 150.5l.2 .2z"/>
<path d="M110.8 150.7v.9z"/>
<path d="M110.8 151.6l-.2 .3z"/>
<path d="M110.1 151.9h.5z"/>
<path d="M109.9 151.6l.2 .3z"/>
<path d="M110.3 151.4l.5 .5z"/>
<path d="M111.3 150.5v1.4z"/>
<path d="M111.3 150.5h.9z"/>
<path d="M111.3 151.2h.5z"/>
<path d="M117.4 149.4h.9z"/>
<path d="M117.4 149.4v.7z"/>
<path d="M117.4 150.1l.4-.3z"/>
<path d="M117.8 149.8h.3z"/>
<path d="M118.1 149.8l.2 .3z"/>
<path d="M118.3 150.1v.4z"/>
<path d="M118.3 150.5l-.2 .3z"/>
<path d="M117.6 150.8h.5z"/>
<path d="M117.4 150.5l.2 .3z"/>
<path d="M109.9 153.2v1z"/>
<path d="M109.9 153.2l.2-.2z"/>
<path d="M110.1 153h.5z"/>
<path d="M110.6 153l.2 .2z"/>
<path d="M110.8 153.2v1z"/>
<path d="M110.8 154.2l-.2 .2z"/>
<path d="M110.1 154.4h.5z"/>
<path d="M109.9 154.2l.2 .2z"/>
<path d="M110.3 153.9l.5 .5z"/>
<path d="M112 153l.2 .2z"/>
<path d="M111.5 153h.5z"/>
<path d="M111.5 153l-.2 .2z"/>
<path d="M111.3 153.2v1z"/>
<path d="M111.3 154.2l.2 .2z"/>
<path d="M111.5 154.4h.5z"/>
<path d="M112 154.4l.2-.2z"/>
<path d="M112.2 153.7v.5z"/>
<path d="M111.8 153.7h.4z"/>
<path d="M117.8 152.1l.5-.2z"/>
<path d="M117.8 152.1l-.4 .5z"/>
<path d="M117.4 152.6v.5z"/>
<path d="M117.4 153.1l.2 .2z"/>
<path d="M117.6 153.3h.5z"/>
<path d="M118.1 153.3l.2-.2z"/>
<path d="M118.3 152.8v.3z"/>
<path d="M118.1 152.6l.2 .2z"/>
<path d="M117.4 152.6h.7z"/>
<path d="M109.9 155.8v.9z"/>
<path d="M109.9 155.8l.2-.2z"/>
<path d="M110.1 155.6h.5z"/>
<path d="M110.6 155.6l.2 .2z"/>
<path d="M110.8 155.8v.9z"/>
<path d="M110.8 156.7l-.2 .2z"/>
<path d="M110.1 156.9h.5z"/>
<path d="M109.9 156.7l.2 .2z"/>
<path d="M110.3 156.5l.5 .4z"/>
<path d="M111.3 155.6v1.3z"/>
<path d="M111.3 156.2h.9z"/>
<path d="M112.2 155.6v1.3z"/>
<path d="M117.4 154.5h.9z"/>
<path d="M118.3 154.5v.2z"/>
<path d="M118.3 154.7l-.9 .9z"/>
<path d="M117.4 155.6v.2z"/>
<path d="M102.8 145.4l.3 .2z"/>
<path d="M102.4 145.4h.4z"/>
<path d="M102.4 145.4l-.3 .2z"/>
<path d="M102.1 145.6v.3z"/>
<path d="M102.1 145.9l.3 .2z"/>
<path d="M102.4 146.1h.4z"/>
<path d="M102.8 146.1l.3 .2z"/>
<path d="M103.1 146.3v.3z"/>
<path d="M103.1 146.6l-.3 .2z"/>
<path d="M102.4 146.8h.4z"/>
<path d="M102.1 146.6l.3 .2z"/>
<path d="M104.2 145.4l.3 .2z"/>
<path d="M103.8 145.4h.4z"/>
<path d="M103.8 145.4l-.3 .2z"/>
<path d="M103.5 145.6v1z"/>
<path d="M103.5 146.6l.3 .2z"/>
<path d="M103.8 146.8h.4z"/>
<path d="M104.2 146.8l.3-.2z"/>
<path d="M104.9 145.4v1.4z"/>
<path d="M104.9 146.8h1z"/>
<path d="M94.6 144.8l.5-.5z"/>
<path d="M95.1 144.3v1.4z"/>
<path d="M94.6 145.7h1z"/>
<path d="M96.1 144.5v1z"/>
<path d="M96.1 144.5l.2-.2z"/>
<path d="M96.3 144.3h.5z"/>
<path d="M96.8 144.3l.2 .2z"/>
<path d="M97 144.5v1z"/>
<path d="M97 145.5l-.2 .2z"/>
<path d="M96.3 145.7h.5z"/>
<path d="M96.1 145.5l.2 .2z"/>
<path d="M96.1 145.5l.9-1z"/>
<path d="M102.8 142.9l.3 .2z"/>
<path d="M102.4 142.9h.4z"/>
<path d="M102.4 142.9l-.3 .2z"/>
<path d="M102.1 143.1v.2z"/>
<path d="M102.1 143.3l.3 .2z"/>
<path d="M102.4 143.5h.4z"/>
<path d="M102.8 143.5l.3 .3z"/>
<path d="M103.1 143.8v.2z"/>
<path d="M103.1 144l-.3 .3z"/>
<path d="M102.4 144.3h.4z"/>
<path d="M102.1 144l.3 .3z"/>
<path d="M104.2 142.9l.3 .2z"/>
<path d="M103.8 142.9h.4z"/>
<path d="M103.8 142.9l-.3 .2z"/>
<path d="M103.5 143.1v.9z"/>
<path d="M103.5 144l.3 .3z"/>
<path d="M103.8 144.3h.4z"/>
<path d="M104.5 144l-.3 .3z"/>
<path d="M104.9 142.9v1.4z"/>
<path d="M104.9 143.8l1-.9z"/>
<path d="M105.2 143.5l.7 .8z"/>
<path d="M94.6 142.2l.5-.4z"/>
<path d="M95.1 141.8v1.3z"/>
<path d="M94.6 143.1h1z"/>
<path d="M96.5 141.8l-.4 .4z"/>
<path d="M96.5 141.8v1.3z"/>
<path d="M96.1 143.1h.9z"/>
<path d="M102.1 150.5v1.4z"/>
<path d="M102.1 150.5h.7z"/>
<path d="M102.8 150.5l.3 .2z"/>
<path d="M103.1 150.7v.5z"/>
<path d="M103.1 151.2l-.3 .2z"/>
<path d="M102.1 151.4h.7z"/>
<path d="M102.6 151.4l.5 .5z"/>
<path d="M104.2 150.5l.3 .2z"/>
<path d="M103.8 150.5h.4z"/>
<path d="M103.8 150.5l-.3 .2z"/>
<path d="M103.5 150.7v.9z"/>
<path d="M103.5 151.6l.3 .3z"/>
<path d="M103.8 151.9h.4z"/>
<path d="M104.2 151.9l.3-.3z"/>
<path d="M104.9 150.5v1.4z"/>
<path d="M104.9 151.4l1-.9z"/>
<path d="M105.2 151.2l.7 .7z"/>
<path d="M94.6 149.8l.5-.4z"/>
<path d="M95.1 149.4v1.4z"/>
<path d="M94.6 150.8h1z"/>
<path d="M96.1 150.8h.9z"/>
<path d="M96.1 150.8l.9-1z"/>
<path d="M97 149.6v.2z"/>
<path d="M96.8 149.4l.2 .2z"/>
<path d="M96.3 149.4h.5z"/>
<path d="M96.3 149.4l-.2 .2z"/>
<path d="M102.8 160.6l.3 .3z"/>
<path d="M102.4 160.6h.4z"/>
<path d="M102.4 160.6l-.3 .3z"/>
<path d="M102.1 160.9v.9z"/>
<path d="M102.1 161.8l.3 .2z"/>
<path d="M102.4 162h.4z"/>
<path d="M103.1 161.8l-.3 .2z"/>
<path d="M103.1 161.3v.5z"/>
<path d="M102.6 161.3h.5z"/>
<path d="M95.1 159.5l-.5 .5z"/>
<path d="M95.1 159.5v1.4z"/>
<path d="M94.6 160.9h1z"/>
<path d="M96.3 159.5l-.2 .3z"/>
<path d="M96.3 159.5h.5z"/>
<path d="M96.8 159.5l.2 .3z"/>
<path d="M97 159.8v.2z"/>
<path d="M97 160l-.2 .2z"/>
<path d="M96.5 160.2h.3z"/>
<path d="M96.8 160.2l.2 .3z"/>
<path d="M97 160.5v.2z"/>
<path d="M97 160.7l-.2 .2z"/>
<path d="M96.3 160.9h.5z"/>
<path d="M96.1 160.7l.2 .2z"/>
<path d="M102.8 137.8l.3 .2z"/>
<path d="M102.4 137.8h.4z"/>
<path d="M102.4 137.8l-.3 .2z"/>
<path d="M102.1 138v.3z"/>
<path d="M102.1 138.3l.3 .2z"/>
<path d="M102.4 138.5h.4z"/>
<path d="M102.8 138.5l.3 .2z"/>
<path d="M103.1 138.7v.3z"/>
<path d="M103.1 139l-.3 .2z"/>
<path d="M102.4 139.2h.4z"/>
<path d="M102.1 139l.3 .2z"/>
<path d="M103.5 137.8h1z"/>
<path d="M103.5 137.8v1.4z"/>
<path d="M103.5 139.2h1z"/>
<path d="M103.5 138.5h.5z"/>
<path d="M104.9 137.8v1.4z"/>
<path d="M104.9 137.8h.7z"/>
<path d="M105.6 137.8l.3 .2z"/>
<path d="M105.9 138v.5z"/>
<path d="M105.9 138.5l-.3 .2z"/>
<path d="M104.9 138.7h.7z"/>
<path d="M105.4 138.7l.5 .5z"/>
<path d="M94.6 137.1l.5-.4z"/>
<path d="M95.1 136.7v1.4z"/>
<path d="M94.6 138.1h1z"/>
<path d="M96.8 136.7v1.4z"/>
<path d="M96.8 136.7l-.7 .7z"/>
<path d="M96.1 137.4h.9z"/>
<path d="M109.9 138v1z"/>
<path d="M109.9 138l.2-.2z"/>
<path d="M110.1 137.8h.5z"/>
<path d="M110.6 137.8l.2 .2z"/>
<path d="M110.8 138v1z"/>
<path d="M110.8 139l-.2 .2z"/>
<path d="M110.1 139.2h.5z"/>
<path d="M109.9 139l.2 .2z"/>
<path d="M110.3 138.7l.5 .5z"/>
<path d="M111.3 138.3v.9z"/>
<path d="M111.3 138.3l.5-.5z"/>
<path d="M111.8 137.8l.4 .5z"/>
<path d="M112.2 138.3v.9z"/>
<path d="M111.3 138.5h.9z"/>
<path d="M117.4 137.1l.4-.4z"/>
<path d="M117.8 136.7v1.4z"/>
<path d="M117.4 138.1h.9z"/>
<path d="M118.8 136.7h.9z"/>
<path d="M118.8 136.7v.7z"/>
<path d="M118.8 137.4l.4-.3z"/>
<path d="M119.2 137.1h.3z"/>
<path d="M119.5 137.1l.2 .3z"/>
<path d="M119.7 137.4v.4z"/>
<path d="M119.7 137.8l-.2 .3z"/>
<path d="M119 138.1h.5z"/>
<path d="M118.8 137.8l.2 .3z"/>
<path d="M99.8 135.2h.5z"/>
<path d="M100.1 133.6v1.6z"/>
<path d="M99.8 133.6h.5z"/>
<path d="M101.7 133.6l.3 .3z"/>
<path d="M101.2 133.6h.5z"/>
<path d="M101.2 133.6l-.3 .3z"/>
<path d="M100.9 133.9v1.1z"/>
<path d="M100.9 135l.3 .2z"/>
<path d="M101.2 135.2h.5z"/>
<path d="M101.7 135.2l.3-.2z"/>
<path d="M103.1 133.6l-.6 .6z"/>
<path d="M103.1 133.6v1.6z"/>
<path d="M102.5 135.2h1.1z"/>
<path d="M108.5 160.9v.9z"/>
<path d="M108.5 160.9l.2-.3z"/>
<path d="M108.7 160.6h.5z"/>
<path d="M109.2 160.6l.2 .3z"/>
<path d="M109.4 160.9v.9z"/>
<path d="M109.4 161.8l-.2 .2z"/>
<path d="M108.7 162h.5z"/>
<path d="M108.5 161.8l.2 .2z"/>
<path d="M108.9 161.6l.5 .4z"/>
<path d="M109.9 160.6v1.4z"/>
<path d="M109.9 161.3h.9z"/>
<path d="M110.8 160.6v1.4z"/>
<path d="M111.3 160.9l.9 .9z"/>
<path d="M111.3 161.8l.9-.9z"/>
<path d="M111.3 161.3h.9z"/>
<path d="M111.8 160.9v.9z"/>
<path d="M117.4 160.7l.2 .2z"/>
<path d="M117.6 160.9h.5z"/>
<path d="M118.1 160.9l.2-.2z"/>
<path d="M118.3 159.8v.9z"/>
<path d="M118.1 159.5l.2 .3z"/>
<path d="M117.6 159.5h.5z"/>
<path d="M117.6 159.5l-.2 .3z"/>
<path d="M117.4 159.8v.2z"/>
<path d="M117.4 160l.2 .2z"/>
<path d="M117.6 160.2h.7z"/>
<path d="M54.7 154.6l.3 .3z"/>
<path d="M54.7 154.2v.4z"/>
<path d="M54.7 154.2l.3-.3z"/>
<path d="M55 153.9h.2z"/>
<path d="M55.2 153.9l.2 .3z"/>
<path d="M55.4 154.2l.3-.3z"/>
<path d="M55.7 153.9h.2z"/>
<path d="M55.9 153.9l.2 .3z"/>
<path d="M56.1 154.2v.4z"/>
<path d="M56.1 154.6l-.2 .3z"/>
<path d="M55.7 154.9h.2z"/>
<path d="M55.4 154.6l.3 .3z"/>
<path d="M55.4 154.6l-.2 .3z"/>
<path d="M55 154.9h.2z"/>
<path d="M55.4 154.2v.4z"/>
<path d="M54.7 143.2l.5 .5z"/>
<path d="M54.7 143.2h1.4z"/>
<path d="M56.1 142.8v.9z"/>
<path d="M54.7 141.4l.3 .4z"/>
<path d="M55 141.8l.4 .5z"/>
<path d="M55.4 142.3h.5z"/>
<path d="M55.9 142.3l.2-.2z"/>
<path d="M56.1 141.6v.5z"/>
<path d="M55.9 141.4l.2 .2z"/>
<path d="M55.7 141.4h.2z"/>
<path d="M55.7 141.4l-.3 .2z"/>
<path d="M55.4 141.6v.7z"/>
<path d="M56 149.2h.5z"/>
<path d="M56.3 147.6v1.6z"/>
<path d="M56 147.6h.5z"/>
<path d="M57.9 147.6l.3 .2z"/>
<path d="M57.4 147.6h.5z"/>
<path d="M57.4 147.6l-.3 .2z"/>
<path d="M57.1 147.8v1.1z"/>
<path d="M57.1 148.9l.3 .3z"/>
<path d="M57.4 149.2h.5z"/>
<path d="M57.9 149.2l.3-.3z"/>
<path d="M58.7 148.1l.6-.5z"/>
<path d="M59.3 147.6v1.6z"/>
<path d="M58.7 149.2h1.1z"/>
<path d="M60.4 147.6v1.6z"/>
<path d="M60.4 147.6h.8z"/>
<path d="M61.2 147.6l.2 .2z"/>
<path d="M61.4 147.8v.6z"/>
<path d="M61.4 148.4l-.2 .3z"/>
<path d="M60.4 148.7h.8z"/>
<path d="M57.4 153.6l-.2 .2z"/>
<path d="M57.2 153.8v.4z"/>
<path d="M57.2 154.2l.2 .2z"/>
<path d="M57.4 154.4h.8z"/>
<path d="M58.4 154.2l-.2 .2z"/>
<path d="M58.4 153.8v.4z"/>
<path d="M58.2 153.6l.2 .2z"/>
<path d="M57.8 153.6h.4z"/>
<path d="M57.8 153.6v.4z"/>
<path d="M57.2 153.3h1.2z"/>
<path d="M57.2 153.3l1.2-.8z"/>
<path d="M57.2 152.5h1.2z"/>
<path d="M57.2 152.1h1.2z"/>
<path d="M58.4 151.5v.6z"/>
<path d="M58.2 151.3l.2 .2z"/>
<path d="M57.4 151.3h.8z"/>
<path d="M57.4 151.3l-.2 .2z"/>
<path d="M57.2 151.5v.6z"/>
<path d="M57.2 146h.8z"/>
<path d="M58 146l.4-.3z"/>
<path d="M58 145.3l.4 .4z"/>
<path d="M57.2 145.3h.8z"/>
<path d="M57.4 144.1l-.2 .2z"/>
<path d="M57.2 144.3v.4z"/>
<path d="M57.2 144.7l.2 .2z"/>
<path d="M57.4 144.9h.8z"/>
<path d="M58.2 144.9l.2-.2z"/>
<path d="M58.4 144.3v.4z"/>
<path d="M58.2 144.1l.2 .2z"/>
<path d="M57.4 142.9l-.2 .2z"/>
<path d="M57.2 143.1v.4z"/>
<path d="M57.2 143.5l.2 .2z"/>
<path d="M57.4 143.7h.8z"/>
<path d="M58.4 143.5l-.2 .2z"/>
<path d="M58.4 143.1v.4z"/>
<path d="M58.2 142.9l.2 .2z"/>
<path d="M38.6 40.6l.5-.4z"/>
<path d="M39.1 40.2v1.4z"/>
<path d="M38.6 41.6h1z"/>
<path d="M38.6 44.1h1z"/>
<path d="M38.6 44.1l1-.9z"/>
<path d="M39.6 42.9v.3z"/>
<path d="M39.3 42.7l.3 .2z"/>
<path d="M38.9 42.7h.4z"/>
<path d="M38.9 42.7l-.3 .2z"/>
<path d="M38.6 45.5l.3-.2z"/>
<path d="M38.9 45.3h.4z"/>
<path d="M39.3 45.3l.3 .2z"/>
<path d="M39.6 45.5v.2z"/>
<path d="M39.6 45.7l-.3 .3z"/>
<path d="M39.1 46h.2z"/>
<path d="M39.3 46l.3 .2z"/>
<path d="M39.6 46.2v.2z"/>
<path d="M39.6 46.4l-.3 .3z"/>
<path d="M38.9 46.7h.4z"/>
<path d="M38.6 46.4l.3 .3z"/>
<path d="M39.3 47.8v1.4z"/>
<path d="M39.3 47.8l-.7 .7z"/>
<path d="M38.6 48.5h1z"/>
<path d="M38.6 50.3h1z"/>
<path d="M38.6 50.3v.7z"/>
<path d="M38.6 51l.5-.2z"/>
<path d="M39.1 50.8h.2z"/>
<path d="M39.3 50.8l.3 .2z"/>
<path d="M39.6 51v.5z"/>
<path d="M39.6 51.5l-.3 .2z"/>
<path d="M38.9 51.7h.4z"/>
<path d="M38.6 51.5l.3 .2z"/>
<path d="M34.2 37.1l.3 .3z"/>
<path d="M33.7 37.1h.5z"/>
<path d="M33.7 37.1l-.3 .3z"/>
<path d="M33.4 37.4v1.1z"/>
<path d="M33.4 38.5l.3 .2z"/>
<path d="M33.7 38.7h.5z"/>
<path d="M34.5 38.5l-.3 .2z"/>
<path d="M35.6 37.1v1.6z"/>
<path d="M35 37.1h1.1z"/>
<path d="M36.7 37.1v1.6z"/>
<path d="M36.7 38.7h1z"/>
<path d="M38.3 39h1.1z"/>
<path d="M39.9 38.7h.6z"/>
<path d="M40.2 37.1v1.6z"/>
<path d="M39.9 37.1h.6z"/>
<path d="M41 37.1v1.6z"/>
<path d="M41 37.1l1.1 1.6z"/>
<path d="M42.1 37.1v1.6z"/>
<path d="M78.7 40.2l-.4 .4z"/>
<path d="M78.7 40.2v1.4z"/>
<path d="M78.3 41.6h.9z"/>
<path d="M78.3 44.1h.9z"/>
<path d="M78.3 44.1l.9-.9z"/>
<path d="M79.2 42.9v.3z"/>
<path d="M79 42.7l.2 .2z"/>
<path d="M78.5 42.7h.5z"/>
<path d="M78.3 42.9l.2-.2z"/>
<path d="M78.3 45.5l.2-.2z"/>
<path d="M78.5 45.3h.5z"/>
<path d="M79 45.3l.2 .2z"/>
<path d="M79.2 45.5v.2z"/>
<path d="M79.2 45.7l-.2 .3z"/>
<path d="M78.7 46h.3z"/>
<path d="M79 46l.2 .2z"/>
<path d="M79.2 46.2v.2z"/>
<path d="M79.2 46.4l-.2 .3z"/>
<path d="M78.5 46.7h.5z"/>
<path d="M78.3 46.4l.2 .3z"/>
<path d="M79 47.8v1.4z"/>
<path d="M79 47.8l-.7 .7z"/>
<path d="M78.3 48.5h.9z"/>
<path d="M78.3 50.3h.9z"/>
<path d="M78.3 50.3v.7z"/>
<path d="M78.3 51l.4-.2z"/>
<path d="M78.7 50.8h.3z"/>
<path d="M79 50.8l.2 .2z"/>
<path d="M79.2 51v.5z"/>
<path d="M79.2 51.5l-.2 .2z"/>
<path d="M78.5 51.7h.5z"/>
<path d="M78.3 51.5l.2 .2z"/>
<path d="M76.5 37.1l.2 .3z"/>
<path d="M75.9 37.1h.6z"/>
<path d="M75.9 37.1l-.2 .3z"/>
<path d="M75.7 37.4v1.1z"/>
<path d="M75.7 38.5l.2 .2z"/>
<path d="M75.9 38.7h.6z"/>
<path d="M76.7 38.5l-.2 .2z"/>
<path d="M77.8 37.1v1.6z"/>
<path d="M77.3 37.1h1.1z"/>
<path d="M79 37.1v1.6z"/>
<path d="M79 38.7h1z"/>
<path d="M80.6 39h1.1z"/>
<path d="M82.5 37.1h.5z"/>
<path d="M82.5 37.1l-.3 .3z"/>
<path d="M82.2 37.4v1.1z"/>
<path d="M82.2 38.5l.3 .2z"/>
<path d="M82.5 38.7h.5z"/>
<path d="M83.3 38.5l-.3 .2z"/>
<path d="M83.3 37.4v1.1z"/>
<path d="M83 37.1l.3 .3z"/>
<path d="M83.9 37.1v1.4z"/>
<path d="M83.9 38.5l.2 .2z"/>
<path d="M84.1 38.7h.6z"/>
<path d="M84.7 38.7l.2-.2z"/>
<path d="M84.9 37.1v1.4z"/>
<path d="M86 37.1v1.6z"/>
<path d="M85.5 37.1h1.1z"/>
<path d="M139.2 53.9l1 1.6z"/>
<path d="M140.2 53.9l-1 1.6z"/>
<path d="M140.8 54.4l.5-.5z"/>
<path d="M141.3 53.9v1.6z"/>
<path d="M140.8 55.5h1.1z"/>
<path d="M142.4 54.7h1.1z"/>
<path d="M144.6 53.9l-.5 .5z"/>
<path d="M144.6 53.9v1.6z"/>
<path d="M144.1 55.5h1.1z"/>
<path d="M139.2 58.9l1 1.7z"/>
<path d="M140.2 58.9l-1 1.7z"/>
<path d="M141.3 58.9l-.5 .6z"/>
<path d="M141.3 58.9v1.7z"/>
<path d="M140.8 60.6h1.1z"/>
<path d="M142.4 59.8h1.1z"/>
<path d="M144.1 60.6h1.1z"/>
<path d="M144.1 60.6l1.1-1.1z"/>
<path d="M145.2 59.2v.3z"/>
<path d="M144.9 58.9l.3 .3z"/>
<path d="M144.3 58.9h.6z"/>
<path d="M144.3 58.9l-.2 .3z"/>
<path d="M139.2 64l1 1.7z"/>
<path d="M140.2 64l-1 1.7z"/>
<path d="M140.8 64.6l.5-.6z"/>
<path d="M141.3 64v1.7z"/>
<path d="M140.8 65.7h1.1z"/>
<path d="M142.4 64.8h1.1z"/>
<path d="M144.3 64l-.2 .3z"/>
<path d="M144.3 64h.6z"/>
<path d="M144.9 64l.3 .3z"/>
<path d="M145.2 64.3v.3z"/>
<path d="M145.2 64.6l-.3 .2z"/>
<path d="M144.6 64.8h.3z"/>
<path d="M144.9 64.8l.3 .3z"/>
<path d="M145.2 65.1v.3z"/>
<path d="M145.2 65.4l-.3 .3z"/>
<path d="M144.3 65.7h.6z"/>
<path d="M144.1 65.4l.2 .3z"/>
<path d="M139.2 69.1l1 1.6z"/>
<path d="M140.2 69.1l-1 1.6z"/>
<path d="M140.8 69.6l.5-.5z"/>
<path d="M141.3 69.1v1.6z"/>
<path d="M140.8 70.7h1.1z"/>
<path d="M142.4 69.9h1.1z"/>
<path d="M144.9 69.1v1.6z"/>
<path d="M144.9 69.1l-.8 .8z"/>
<path d="M144.1 69.9h1.1z"/>
<path d="M139.2 74.2l1 1.6z"/>
<path d="M140.2 74.2l-1 1.6z"/>
<path d="M140.8 74.7l.5-.5z"/>
<path d="M141.3 74.2v1.6z"/>
<path d="M140.8 75.8h1.1z"/>
<path d="M142.4 75h1.1z"/>
<path d="M144.1 74.2h1.1z"/>
<path d="M144.1 74.2v.8z"/>
<path d="M144.1 75l.5-.3z"/>
<path d="M144.6 74.7h.3z"/>
<path d="M144.9 74.7l.3 .3z"/>
<path d="M145.2 75v.5z"/>
<path d="M145.2 75.5l-.3 .3z"/>
<path d="M144.3 75.8h.6z"/>
<path d="M144.1 75.5l.2 .3z"/>
<path d="M139.2 79.3l1 1.6z"/>
<path d="M140.2 79.3l-1 1.6z"/>
<path d="M140.8 79.8l.5-.5z"/>
<path d="M141.3 79.3v1.6z"/>
<path d="M140.8 80.9h1.1z"/>
<path d="M142.4 80.1h1.1z"/>
<path d="M144.6 79.5l.6-.2z"/>
<path d="M144.6 79.5l-.5 .6z"/>
<path d="M144.1 80.1v.5z"/>
<path d="M144.1 80.6l.2 .3z"/>
<path d="M144.3 80.9h.6z"/>
<path d="M144.9 80.9l.3-.3z"/>
<path d="M145.2 80.3v.3z"/>
<path d="M144.9 80.1l.3 .2z"/>
<path d="M144.1 80.1h.8z"/>
<path d="M139.2 84.3l1 1.7z"/>
<path d="M140.2 84.3l-1 1.7z"/>
<path d="M140.8 84.9l.5-.6z"/>
<path d="M141.3 84.3v1.7z"/>
<path d="M140.8 86h1.1z"/>
<path d="M142.4 85.2h1.1z"/>
<path d="M144.1 84.3h1.1z"/>
<path d="M145.2 84.3v.3z"/>
<path d="M145.2 84.6l-1.1 1.1z"/>
<path d="M144.1 85.7v.3z"/>
<path d="M139.2 89.4l1 1.6z"/>
<path d="M140.2 89.4l-1 1.6z"/>
<path d="M140.8 90l.5-.6z"/>
<path d="M141.3 89.4v1.6z"/>
<path d="M140.8 91h1.1z"/>
<path d="M142.4 90.2h1.1z"/>
<path d="M144.1 89.7l.2-.3z"/>
<path d="M144.3 89.4h.6z"/>
<path d="M144.9 89.4l.3 .3z"/>
<path d="M145.2 89.7v.3z"/>
<path d="M145.2 90l-.3 .2z"/>
<path d="M144.9 90.2l.3 .3z"/>
<path d="M145.2 90.5v.3z"/>
<path d="M144.9 91l.3-.2z"/>
<path d="M144.3 91h.6z"/>
<path d="M144.1 90.8l.2 .2z"/>
<path d="M144.1 90.5v.3z"/>
<path d="M144.3 90.2l-.2 .3z"/>
<path d="M144.1 90l.2 .2z"/>
<path d="M144.1 89.7v.3z"/>
<path d="M144.3 90.2h.6z"/>
<path d="M139.2 94.5l1 1.6z"/>
<path d="M140.2 94.5l-1 1.6z"/>
<path d="M140.8 95l.5-.5z"/>
<path d="M141.3 94.5v1.6z"/>
<path d="M140.8 96.1h1.1z"/>
<path d="M142.4 95.3h1.1z"/>
<path d="M144.1 95.9l.2 .2z"/>
<path d="M144.3 96.1h.6z"/>
<path d="M144.9 96.1l.3-.2z"/>
<path d="M145.2 94.8v1.1z"/>
<path d="M144.9 94.5l.3 .3z"/>
<path d="M144.3 94.5h.6z"/>
<path d="M144.3 94.5l-.2 .3z"/>
<path d="M144.1 94.8v.2z"/>
<path d="M144.1 95l.2 .3z"/>
<path d="M144.3 95.3h.9z"/>
<path d="M211.3 73.2h.5z"/>
<path d="M211.6 71.8v1.4z"/>
<path d="M211.3 71.8h.5z"/>
<path d="M212.3 72.2l.4-.4z"/>
<path d="M212.7 71.8v1.4z"/>
<path d="M212.3 73.2h.9z"/>
<path d="M205.2 71.1l.5-.5z"/>
<path d="M205.7 70.6v1.4z"/>
<path d="M205.2 72h1z"/>
<path d="M211.3 75.7h.5z"/>
<path d="M211.6 74.3v1.4z"/>
<path d="M211.3 74.3h.5z"/>
<path d="M212.3 75.7h.9z"/>
<path d="M212.3 75.7l.9-.9z"/>
<path d="M213.2 74.5v.3z"/>
<path d="M213 74.3l.2 .2z"/>
<path d="M212.5 74.3h.5z"/>
<path d="M212.5 74.3l-.2 .2z"/>
<path d="M205.2 74.6h1z"/>
<path d="M205.2 74.6l1-1z"/>
<path d="M206.2 73.4v.2z"/>
<path d="M205.9 73.2l.3 .2z"/>
<path d="M205.5 73.2h.4z"/>
<path d="M205.5 73.2l-.3 .2z"/>
<path d="M211.3 78.2h.5z"/>
<path d="M211.6 76.8v1.4z"/>
<path d="M211.3 76.8h.5z"/>
<path d="M212.3 77.1l.2-.3z"/>
<path d="M212.5 76.8h.5z"/>
<path d="M213 76.8l.2 .3z"/>
<path d="M213.2 77.1v.2z"/>
<path d="M213 77.5l.2-.2z"/>
<path d="M212.7 77.5h.3z"/>
<path d="M213 77.5l.2 .3z"/>
<path d="M213.2 77.8v.2z"/>
<path d="M213.2 78l-.2 .2z"/>
<path d="M212.5 78.2h.5z"/>
<path d="M212.3 78l.2 .2z"/>
<path d="M205.2 75.9l.3-.2z"/>
<path d="M205.5 75.7h.4z"/>
<path d="M205.9 75.7l.3 .2z"/>
<path d="M206.2 75.9v.3z"/>
<path d="M206.2 76.2l-.3 .2z"/>
<path d="M205.7 76.4h.2z"/>
<path d="M205.9 76.4l.3 .2z"/>
<path d="M206.2 76.6v.3z"/>
<path d="M206.2 76.9l-.3 .2z"/>
<path d="M205.5 77.1h.4z"/>
<path d="M205.2 76.9l.3 .2z"/>
<path d="M211.3 80.8h.5z"/>
<path d="M211.6 79.4v1.4z"/>
<path d="M211.3 79.4h.5z"/>
<path d="M213 79.4v1.4z"/>
<path d="M213 79.4l-.7 .7z"/>
<path d="M212.3 80.1h.9z"/>
<path d="M205.9 78.3v1.3z"/>
<path d="M205.9 78.3l-.7 .7z"/>
<path d="M205.2 79h1z"/>
<path d="M211.3 83.3h.5z"/>
<path d="M211.6 81.9v1.4z"/>
<path d="M211.3 81.9h.5z"/>
<path d="M212.3 81.9h.9z"/>
<path d="M212.3 81.9v.7z"/>
<path d="M212.3 82.6l.4-.2z"/>
<path d="M212.7 82.4h.3z"/>
<path d="M213 82.4l.2 .2z"/>
<path d="M213.2 82.6v.5z"/>
<path d="M213.2 83.1l-.2 .2z"/>
<path d="M212.5 83.3h.5z"/>
<path d="M212.3 83.1l.2 .2z"/>
<path d="M205.2 80.8h1z"/>
<path d="M205.2 80.8v.7z"/>
<path d="M205.2 81.5l.5-.2z"/>
<path d="M205.7 81.3h.2z"/>
<path d="M205.9 81.3l.3 .2z"/>
<path d="M206.2 81.5v.5z"/>
<path d="M206.2 82l-.3 .2z"/>
<path d="M205.5 82.2h.4z"/>
<path d="M205.2 82l.3 .2z"/>
<path d="M211.3 85.9h.5z"/>
<path d="M211.6 84.5v1.4z"/>
<path d="M211.3 84.5h.5z"/>
<path d="M212.7 84.7l.5-.2z"/>
<path d="M212.7 84.7l-.4 .5z"/>
<path d="M212.3 85.2v.4z"/>
<path d="M212.3 85.6l.2 .3z"/>
<path d="M212.5 85.9h.5z"/>
<path d="M213 85.9l.2-.3z"/>
<path d="M213.2 85.4v.2z"/>
<path d="M213 85.2l.2 .2z"/>
<path d="M212.3 85.2h.7z"/>
<path d="M205.7 83.6l.5-.3z"/>
<path d="M205.7 83.6l-.5 .4z"/>
<path d="M205.2 84v.5z"/>
<path d="M205.2 84.5l.3 .2z"/>
<path d="M205.5 84.7h.4z"/>
<path d="M206.2 84.5l-.3 .2z"/>
<path d="M206.2 84.3v.2z"/>
<path d="M205.9 84l.3 .3z"/>
<path d="M205.2 84h.7z"/>
<path d="M211.3 88.4h.5z"/>
<path d="M211.6 87v1.4z"/>
<path d="M211.3 87h.5z"/>
<path d="M212.3 87h.9z"/>
<path d="M213.2 87v.2z"/>
<path d="M213.2 87.2l-.9 1z"/>
<path d="M212.3 88.2v.2z"/>
<path d="M205.2 85.9h1z"/>
<path d="M206.2 85.9v.2z"/>
<path d="M206.2 86.1l-1 .9z"/>
<path d="M205.2 87v.3z"/>
<path d="M211.3 90.9h.5z"/>
<path d="M211.6 89.5v1.4z"/>
<path d="M211.3 89.5h.5z"/>
<path d="M212.3 89.8l.2-.3z"/>
<path d="M212.5 89.5h.5z"/>
<path d="M213 89.5l.2 .3z"/>
<path d="M213.2 89.8v.2z"/>
<path d="M213 90.2l.2-.2z"/>
<path d="M213 90.2l.2 .3z"/>
<path d="M213.2 90.5v.2z"/>
<path d="M213.2 90.7l-.2 .2z"/>
<path d="M212.5 90.9h.5z"/>
<path d="M212.3 90.7l.2 .2z"/>
<path d="M212.3 90.5v.2z"/>
<path d="M212.5 90.2l-.2 .3z"/>
<path d="M212.3 90l.2 .2z"/>
<path d="M212.3 89.8v.2z"/>
<path d="M212.5 90.2h.5z"/>
<path d="M205.2 88.6l.3-.2z"/>
<path d="M205.5 88.4h.4z"/>
<path d="M205.9 88.4l.3 .2z"/>
<path d="M206.2 88.6v.3z"/>
<path d="M206.2 88.9l-.3 .2z"/>
<path d="M205.9 89.1l.3 .2z"/>
<path d="M206.2 89.3v.3z"/>
<path d="M206.2 89.6l-.3 .2z"/>
<path d="M205.5 89.8h.4z"/>
<path d="M205.2 89.6l.3 .2z"/>
<path d="M205.2 89.3v.3z"/>
<path d="M205.2 89.3l.3-.2z"/>
<path d="M205.2 88.9l.3 .2z"/>
<path d="M205.2 88.6v.3z"/>
<path d="M205.5 89.1h.4z"/>
<path d="M219.3 89.5h.5z"/>
<path d="M219.1 89.8l.2-.3z"/>
<path d="M219.1 89.8v.9z"/>
<path d="M219.1 90.7l.2 .2z"/>
<path d="M219.3 90.9h.5z"/>
<path d="M219.8 90.9l.2-.2z"/>
<path d="M220 89.8v.9z"/>
<path d="M219.8 89.5l.2 .3z"/>
<path d="M220.5 89.8l.2-.3z"/>
<path d="M220.7 89.5h.5z"/>
<path d="M221.2 89.5l.2 .3z"/>
<path d="M221.4 89.8v.2z"/>
<path d="M221.4 90l-.2 .2z"/>
<path d="M221.2 90.2l.2 .3z"/>
<path d="M221.4 90.5v.2z"/>
<path d="M221.4 90.7l-.2 .2z"/>
<path d="M220.7 90.9h.5z"/>
<path d="M220.5 90.7l.2 .2z"/>
<path d="M220.5 90.5v.2z"/>
<path d="M220.5 90.5l.2-.3z"/>
<path d="M220.5 90l.2 .2z"/>
<path d="M220.5 89.8v.2z"/>
<path d="M220.7 90.2h.5z"/>
<path d="M226.6 88.9l.4-.5z"/>
<path d="M227 88.4v1.4z"/>
<path d="M226.6 89.8h.9z"/>
<path d="M228 88.9l.4-.5z"/>
<path d="M228.4 88.4v1.4z"/>
<path d="M228 89.8h.9z"/>
<path d="M219.3 71.8h.5z"/>
<path d="M219.3 71.8l-.2 .2z"/>
<path d="M219.1 72v.9z"/>
<path d="M219.1 72.9l.2 .3z"/>
<path d="M219.3 73.2h.5z"/>
<path d="M219.8 73.2l.2-.3z"/>
<path d="M220 72v.9z"/>
<path d="M219.8 71.8l.2 .2z"/>
<path d="M220.5 72.2l.5-.4z"/>
<path d="M221 71.8v1.4z"/>
<path d="M220.5 73.2h.9z"/>
<path d="M226.6 71.1l.4-.5z"/>
<path d="M227 70.6v1.4z"/>
<path d="M226.6 72h.9z"/>
<path d="M228 70.9l.2-.3z"/>
<path d="M228.2 70.6h.5z"/>
<path d="M228.7 70.6l.2 .3z"/>
<path d="M228.9 70.9v.2z"/>
<path d="M228.9 71.1l-.2 .2z"/>
<path d="M228.7 71.3l.2 .3z"/>
<path d="M228.9 71.6v.2z"/>
<path d="M228.9 71.8l-.2 .2z"/>
<path d="M228.2 72h.5z"/>
<path d="M228 71.8l.2 .2z"/>
<path d="M228 71.6v.2z"/>
<path d="M228 71.6l.2-.3z"/>
<path d="M228 71.1l.2 .2z"/>
<path d="M228 70.9v.2z"/>
<path d="M228.2 71.3h.5z"/>
<path d="M219.3 74.3h.5z"/>
<path d="M219.1 74.5l.2-.2z"/>
<path d="M219.1 74.5v1z"/>
<path d="M219.1 75.5l.2 .2z"/>
<path d="M219.3 75.7h.5z"/>
<path d="M219.8 75.7l.2-.2z"/>
<path d="M220 74.5v1z"/>
<path d="M219.8 74.3l.2 .2z"/>
<path d="M220.5 75.7h.9z"/>
<path d="M220.5 75.7l.9-.9z"/>
<path d="M221.4 74.5v.3z"/>
<path d="M221.2 74.3l.2 .2z"/>
<path d="M220.7 74.3h.5z"/>
<path d="M220.5 74.5l.2-.2z"/>
<path d="M226.6 73.6l.4-.4z"/>
<path d="M227 73.2v1.4z"/>
<path d="M226.6 74.6h.9z"/>
<path d="M228 73.2h.9z"/>
<path d="M228.9 73.2v.2z"/>
<path d="M228.9 73.4l-.9 .9z"/>
<path d="M228 74.3v.3z"/>
<path d="M219.3 76.8h.5z"/>
<path d="M219.3 76.8l-.2 .3z"/>
<path d="M219.1 77.1v.9z"/>
<path d="M219.1 78l.2 .2z"/>
<path d="M219.3 78.2h.5z"/>
<path d="M219.8 78.2l.2-.2z"/>
<path d="M220 77.1v.9z"/>
<path d="M219.8 76.8l.2 .3z"/>
<path d="M220.5 77.1l.2-.3z"/>
<path d="M220.7 76.8h.5z"/>
<path d="M221.2 76.8l.2 .3z"/>
<path d="M221.4 77.1v.2z"/>
<path d="M221.4 77.3l-.2 .2z"/>
<path d="M221 77.5h.2z"/>
<path d="M221.2 77.5l.2 .3z"/>
<path d="M221.4 77.8v.2z"/>
<path d="M221.4 78l-.2 .2z"/>
<path d="M220.7 78.2h.5z"/>
<path d="M220.5 78l.2 .2z"/>
<path d="M226.6 76.2l.4-.5z"/>
<path d="M227 75.7v1.4z"/>
<path d="M226.6 77.1h.9z"/>
<path d="M228.4 75.9l.5-.2z"/>
<path d="M228 76.4l.4-.5z"/>
<path d="M228 76.4v.5z"/>
<path d="M228 76.9l.2 .2z"/>
<path d="M228.2 77.1h.5z"/>
<path d="M228.7 77.1l.2-.2z"/>
<path d="M228.9 76.6v.3z"/>
<path d="M228.7 76.4l.2 .2z"/>
<path d="M228 76.4h.7z"/>
<path d="M219.3 79.4h.5z"/>
<path d="M219.3 79.4l-.2 .2z"/>
<path d="M219.1 79.6v.9z"/>
<path d="M219.1 80.5l.2 .3z"/>
<path d="M219.3 80.8h.5z"/>
<path d="M219.8 80.8l.2-.3z"/>
<path d="M220 79.6v.9z"/>
<path d="M219.8 79.4l.2 .2z"/>
<path d="M221.2 79.4v1.4z"/>
<path d="M220.5 80.1l.7-.7z"/>
<path d="M220.5 80.1h.9z"/>
<path d="M226.6 78.7l.4-.4z"/>
<path d="M227 78.3v1.3z"/>
<path d="M226.6 79.6h.9z"/>
<path d="M228 78.3h.9z"/>
<path d="M228 78.3v.7z"/>
<path d="M228 79l.4-.3z"/>
<path d="M228.4 78.7h.3z"/>
<path d="M228.7 78.7l.2 .3z"/>
<path d="M228.9 79v.4z"/>
<path d="M228.9 79.4l-.2 .2z"/>
<path d="M228.2 79.6h.5z"/>
<path d="M228 79.4l.2 .2z"/>
<path d="M219.3 81.9h.5z"/>
<path d="M219.1 82.1l.2-.2z"/>
<path d="M219.1 82.1v1z"/>
<path d="M219.1 83.1l.2 .2z"/>
<path d="M219.3 83.3h.5z"/>
<path d="M219.8 83.3l.2-.2z"/>
<path d="M220 82.1v1z"/>
<path d="M219.8 81.9l.2 .2z"/>
<path d="M220.5 81.9h.9z"/>
<path d="M220.5 81.9v.7z"/>
<path d="M220.5 82.6l.5-.2z"/>
<path d="M221 82.4h.2z"/>
<path d="M221.2 82.4l.2 .2z"/>
<path d="M221.4 82.6v.5z"/>
<path d="M221.4 83.1l-.2 .2z"/>
<path d="M220.7 83.3h.5z"/>
<path d="M220.5 83.1l.2 .2z"/>
<path d="M226.6 81.3l.4-.5z"/>
<path d="M227 80.8v1.4z"/>
<path d="M226.6 82.2h.9z"/>
<path d="M228.7 80.8v1.4z"/>
<path d="M228.7 80.8l-.7 .7z"/>
<path d="M228 81.5h.9z"/>
<path d="M219.3 84.5h.5z"/>
<path d="M219.3 84.5l-.2 .2z"/>
<path d="M219.1 84.7v.9z"/>
<path d="M219.1 85.6l.2 .3z"/>
<path d="M219.3 85.9h.5z"/>
<path d="M219.8 85.9l.2-.3z"/>
<path d="M220 84.7v.9z"/>
<path d="M219.8 84.5l.2 .2z"/>
<path d="M221 84.7l.4-.2z"/>
<path d="M221 84.7l-.5 .5z"/>
<path d="M220.5 85.2v.4z"/>
<path d="M220.5 85.6l.2 .3z"/>
<path d="M220.7 85.9h.5z"/>
<path d="M221.4 85.6l-.2 .3z"/>
<path d="M221.4 85.4v.2z"/>
<path d="M221.2 85.2l.2 .2z"/>
<path d="M220.5 85.2h.7z"/>
<path d="M226.6 83.8l.4-.5z"/>
<path d="M227 83.3v1.4z"/>
<path d="M226.6 84.7h.9z"/>
<path d="M228 83.6l.2-.3z"/>
<path d="M228.2 83.3h.5z"/>
<path d="M228.7 83.3l.2 .3z"/>
<path d="M228.9 83.6v.2z"/>
<path d="M228.9 83.8l-.2 .2z"/>
<path d="M228.4 84h.3z"/>
<path d="M228.7 84l.2 .3z"/>
<path d="M228.9 84.3v.2z"/>
<path d="M228.9 84.5l-.2 .2z"/>
<path d="M228.2 84.7h.5z"/>
<path d="M228 84.5l.2 .2z"/>
<path d="M219.3 87h.5z"/>
<path d="M219.3 87l-.2 .2z"/>
<path d="M219.1 87.2v1z"/>
<path d="M219.1 88.2l.2 .2z"/>
<path d="M219.3 88.4h.5z"/>
<path d="M219.8 88.4l.2-.2z"/>
<path d="M220 87.2v1z"/>
<path d="M219.8 87l.2 .2z"/>
<path d="M220.5 87h.9z"/>
<path d="M221.4 87v.2z"/>
<path d="M221.4 87.2l-.9 1z"/>
<path d="M220.5 88.2v.2z"/>
<path d="M226.6 86.3l.4-.4z"/>
<path d="M227 85.9v1.4z"/>
<path d="M226.6 87.3h.9z"/>
<path d="M228 87.3h.9z"/>
<path d="M228 87.3l.9-1z"/>
<path d="M228.9 86.1v.2z"/>
<path d="M228.7 85.9l.2 .2z"/>
<path d="M228.2 85.9h.5z"/>
<path d="M228 86.1l.2-.2z"/>
<path d="M209 69.1h.5z"/>
<path d="M209.3 67.5v1.6z"/>
<path d="M209 67.5h.5z"/>
<path d="M210.9 67.5l.3 .2z"/>
<path d="M210.4 67.5h.5z"/>
<path d="M210.4 67.5l-.3 .2z"/>
<path d="M210.1 67.7v1.1z"/>
<path d="M210.1 68.8l.3 .3z"/>
<path d="M210.4 69.1h.5z"/>
<path d="M210.9 69.1l.3-.3z"/>
<path d="M211.7 69.1h1.1z"/>
<path d="M212.8 68l-1.1 1.1z"/>
<path d="M212.8 67.7v.3z"/>
<path d="M212.5 67.5l.3 .2z"/>
<path d="M212 67.5h.5z"/>
<path d="M212 67.5l-.3 .2z"/>
<path d="M218.4 92.1l.2 .2z"/>
<path d="M217.9 92.1h.5z"/>
<path d="M217.9 92.1l-.2 .2z"/>
<path d="M217.7 92.3v.9z"/>
<path d="M217.7 93.2l.2 .3z"/>
<path d="M217.9 93.5h.5z"/>
<path d="M218.4 93.5l.2-.3z"/>
<path d="M219.1 92.1v1.4z"/>
<path d="M219.1 93.5h.7z"/>
<path d="M219.8 93.5l.2-.3z"/>
<path d="M220 92.3v.9z"/>
<path d="M219.8 92.1l.2 .2z"/>
<path d="M219.1 92.1h.7z"/>
<path d="M220.5 92.8h.9z"/>
<path d="M221 92.3v.9z"/>
<path d="M226.6 91.4l.4-.4z"/>
<path d="M227 91v1.3z"/>
<path d="M226.6 92.3h.9z"/>
<path d="M228 91.2v.9z"/>
<path d="M228 91.2l.2-.2z"/>
<path d="M228.2 91h.5z"/>
<path d="M228.7 91l.2 .2z"/>
<path d="M228.9 91.2v.9z"/>
<path d="M228.9 92.1l-.2 .2z"/>
<path d="M228.2 92.3h.5z"/>
<path d="M228 92.1l.2 .2z"/>
<path d="M228 92.1l.9-.9z"/>
<path d="M212 92.1l.3 .2z"/>
<path d="M211.6 92.1h.4z"/>
<path d="M211.6 92.1l-.3 .2z"/>
<path d="M211.3 92.3v.9z"/>
<path d="M211.3 93.2l.3 .3z"/>
<path d="M211.6 93.5h.4z"/>
<path d="M212 93.5l.3-.3z"/>
<path d="M212.3 92.8v.4z"/>
<path d="M211.8 92.8h.5z"/>
<path d="M212.7 92.1v1.4z"/>
<path d="M212.7 92.1l1 1.4z"/>
<path d="M213.7 92.1v1.4z"/>
<path d="M214.1 92.1v1.4z"/>
<path d="M214.1 93.5h.7z"/>
<path d="M214.8 93.5l.2-.3z"/>
<path d="M215 92.3v.9z"/>
<path d="M214.8 92.1l.2 .2z"/>
<path d="M214.1 92.1h.7z"/>
<path d="M205.2 92.1l.3 .2z"/>
<path d="M205.5 92.3h.4z"/>
<path d="M206.2 92.1l-.3 .2z"/>
<path d="M206.2 91.2v.9z"/>
<path d="M205.9 91l.3 .2z"/>
<path d="M205.5 91h.4z"/>
<path d="M205.5 91l-.3 .2z"/>
<path d="M205.2 91.2v.2z"/>
<path d="M205.2 91.4l.3 .3z"/>
<path d="M205.5 91.7h.7z"/>
<path d="M117.6 93.6v1.1z"/>
<path d="M117.6 94.7l.5 .5z"/>
<path d="M118.1 95.2l.6-.5z"/>
<path d="M118.7 93.6v1.1z"/>
<path d="M120 93.6l.3 .3z"/>
<path d="M119.5 93.6h.5z"/>
<path d="M119.2 93.9l.3-.3z"/>
<path d="M119.2 93.9v1.1z"/>
<path d="M119.2 95l.3 .2z"/>
<path d="M119.5 95.2h.5z"/>
<path d="M120 95.2l.3-.2z"/>
<path d="M121.7 93.6l.2 .3z"/>
<path d="M121.1 93.6h.6z"/>
<path d="M120.8 93.9l.3-.3z"/>
<path d="M120.8 93.9v1.1z"/>
<path d="M120.8 95l.3 .2z"/>
<path d="M121.1 95.2h.6z"/>
<path d="M121.7 95.2l.2-.2z"/>
<path d="M57.4 69.8h1.6z"/>
<path d="M59 68.7v1.1z"/>
<path d="M57.9 68.2h1.1z"/>
<path d="M57.4 67.7l.5 .5z"/>
<path d="M57.4 67.7l.5-.6z"/>
<path d="M57.9 67.1h1.1z"/>
<path d="M58.2 67.1v1.1z"/>
<path d="M57.4 66h1.6z"/>
<path d="M57.4 65.5v1.1z"/>
<path d="M57.7 63.8l-.3 .3z"/>
<path d="M57.4 64.1v.6z"/>
<path d="M57.4 64.7l.3 .2z"/>
<path d="M57.7 64.9h1z"/>
<path d="M58.7 64.9l.3-.2z"/>
<path d="M59 64.1v.6z"/>
<path d="M58.7 63.8l.3 .3z"/>
<path d="M57.4 63.3h1.6z"/>
<path d="M58.2 62.2v1.1z"/>
<path d="M57.4 62.2h1.6z"/>
<path d="M74.4 149.5v1.6z"/>
<path d="M74.4 151.1h1.1z"/>
<path d="M76 150v1.1z"/>
<path d="M76 150l.6-.5z"/>
<path d="M76.6 149.5l.5 .5z"/>
<path d="M77.1 150v1.1z"/>
<path d="M76 150.3h1.1z"/>
<path d="M78.2 149.5v1.6z"/>
<path d="M77.7 149.5h1.1z"/>
<path d="M80.1 149.5l.3 .3z"/>
<path d="M79.6 149.5h.5z"/>
<path d="M79.6 149.5l-.3 .3z"/>
<path d="M79.3 149.8v1z"/>
<path d="M79.3 150.8l.3 .3z"/>
<path d="M79.6 151.1h.5z"/>
<path d="M80.4 150.8l-.3 .3z"/>
<path d="M80.9 149.5v1.6z"/>
<path d="M80.9 150.3h1.1z"/>
<path d="M82 149.5v1.6z"/>
<path d="M60.2 68.7l-.3 .3z"/>
<path d="M59.9 69v.6z"/>
<path d="M59.9 69.6l.3 .2z"/>
<path d="M60.2 69.8h1.1z"/>
<path d="M61.3 69.8l.3-.2z"/>
<path d="M61.6 69v.6z"/>
<path d="M61.3 68.7l.3 .3z"/>
<path d="M59.9 68.2h1.7z"/>
<path d="M61.6 67.1v1.1z"/>
<path d="M59.9 65.8v.5z"/>
<path d="M59.9 66.3l.3 .3z"/>
<path d="M60.2 66.6h1.1z"/>
<path d="M61.3 66.6l.3-.3z"/>
<path d="M61.6 65.8v.5z"/>
<path d="M61.3 65.5l.3 .3z"/>
<path d="M60.2 65.5h1.1z"/>
<path d="M60.2 65.5l-.3 .3z"/>
<path d="M60.2 63.8l-.3 .3z"/>
<path d="M59.9 64.1v.6z"/>
<path d="M59.9 64.7l.3 .2z"/>
<path d="M60.2 64.9h1.1z"/>
<path d="M61.3 64.9l.3-.2z"/>
<path d="M61.6 64.1v.6z"/>
<path d="M61.3 63.8l.3 .3z"/>
<path d="M59.9 63.3h1.7z"/>
<path d="M59.9 62.2l1.1 1.1z"/>
<path d="M61.6 62.2l-.9 .8z"/>
<path d="M75.2 141.9l.3 .2z"/>
<path d="M74.7 141.9h.5z"/>
<path d="M74.7 141.9l-.3 .2z"/>
<path d="M74.4 142.1v1.1z"/>
<path d="M74.4 143.2l.3 .3z"/>
<path d="M74.7 143.5h.5z"/>
<path d="M75.5 143.2l-.3 .3z"/>
<path d="M76 141.9v1.6z"/>
<path d="M76 143.5h1.1z"/>
<path d="M78 141.9h.5z"/>
<path d="M77.7 142.1l.3-.2z"/>
<path d="M77.7 142.1v1.1z"/>
<path d="M77.7 143.2l.3 .3z"/>
<path d="M78 143.5h.5z"/>
<path d="M78.5 143.5l.3-.3z"/>
<path d="M78.8 142.1v1.1z"/>
<path d="M78.5 141.9l.3 .2z"/>
<path d="M80.1 141.9l.3 .2z"/>
<path d="M79.6 141.9h.5z"/>
<path d="M79.6 141.9l-.3 .2z"/>
<path d="M79.3 142.1v1.1z"/>
<path d="M79.3 143.2l.3 .3z"/>
<path d="M79.6 143.5h.5z"/>
<path d="M80.4 143.2l-.3 .3z"/>
<path d="M80.9 141.9v1.6z"/>
<path d="M80.9 142.9l1.1-1z"/>
<path d="M81.2 142.7l.8 .8z"/>
<path d="M54.8 69.8h1.7z"/>
<path d="M56.5 69v.8z"/>
<path d="M56.2 68.7l.3 .3z"/>
<path d="M55.1 68.7h1.1z"/>
<path d="M55.1 68.7l-.3 .3z"/>
<path d="M54.8 69v.8z"/>
<path d="M55.4 68.2h1.1z"/>
<path d="M54.8 67.7l.6 .5z"/>
<path d="M54.8 67.7l.6-.6z"/>
<path d="M55.4 67.1h1.1z"/>
<path d="M55.7 67.1v1.1z"/>
<path d="M54.8 66h1.7z"/>
<path d="M54.8 65.5v1.1z"/>
<path d="M55.4 64.9h1.1z"/>
<path d="M54.8 64.4l.6 .5z"/>
<path d="M54.8 64.4l.6-.6z"/>
<path d="M55.4 63.8h1.1z"/>
<path d="M55.7 63.8v1.1z"/>
<path d="M56.7 62.2v1.1z"/>
<path d="M56.5 61.1v.6z"/>
<path d="M54.8 61.4h1.7z"/>
<path d="M54.8 61.1v.6z"/>
<path d="M54.8 60.6h1.7z"/>
<path d="M54.8 60.6l1.7-1.1z"/>
<path d="M54.8 59.5h1.7z"/>
<path d="M74.4 136.8v1.6z"/>
<path d="M74.4 138.4h.8z"/>
<path d="M75.5 138.1l-.3 .3z"/>
<path d="M75.5 137.1v1z"/>
<path d="M75.2 136.8l.3 .3z"/>
<path d="M74.4 136.8h.8z"/>
<path d="M76 137.3v1.1z"/>
<path d="M76 137.3l.6-.5z"/>
<path d="M76.6 136.8l.5 .5z"/>
<path d="M77.1 137.3v1.1z"/>
<path d="M76 137.6h1.1z"/>
<path d="M78.2 136.8v1.6z"/>
<path d="M77.7 136.8h1.1z"/>
<path d="M79.3 137.3v1.1z"/>
<path d="M79.3 137.3l.6-.5z"/>
<path d="M79.9 136.8l.5 .5z"/>
<path d="M80.4 137.3v1.1z"/>
<path d="M79.3 137.6h1.1z"/>
<path d="M80.9 138.7h1.1z"/>
<path d="M82.6 138.4h.5z"/>
<path d="M82.9 136.8v1.6z"/>
<path d="M82.6 136.8h.5z"/>
<path d="M83.7 136.8v1.6z"/>
<path d="M83.7 136.8l1.1 1.6z"/>
<path d="M84.8 136.8v1.6z"/>
<path d="M62.5 69.8h1.6z"/>
<path d="M64.1 69v.8z"/>
<path d="M63.8 68.7l.3 .3z"/>
<path d="M62.7 68.7h1.1z"/>
<path d="M62.7 68.7l-.2 .3z"/>
<path d="M62.5 69v.8z"/>
<path d="M63 68.2h1.1z"/>
<path d="M62.5 67.7l.5 .5z"/>
<path d="M62.5 67.7l.5-.6z"/>
<path d="M63 67.1h1.1z"/>
<path d="M63.3 67.1v1.1z"/>
<path d="M62.5 66h1.6z"/>
<path d="M62.5 65.5v1.1z"/>
<path d="M63 64.9h1.1z"/>
<path d="M62.5 64.4l.5 .5z"/>
<path d="M62.5 64.4l.5-.6z"/>
<path d="M63 63.8h1.1z"/>
<path d="M63.3 63.8v1.1z"/>
<path d="M64.4 62.2v1.1z"/>
<path d="M62.5 60.9v.5z"/>
<path d="M62.5 61.4l.2 .3z"/>
<path d="M62.7 61.7h1.1z"/>
<path d="M63.8 61.7l.3-.3z"/>
<path d="M64.1 60.9v.5z"/>
<path d="M63.8 60.6l.3 .3z"/>
<path d="M62.7 60.6h1.1z"/>
<path d="M62.7 60.6l-.2 .3z"/>
<path d="M62.5 60h1.3z"/>
<path d="M63.8 60l.3-.2z"/>
<path d="M64.1 59.2v.6z"/>
<path d="M63.8 58.9l.3 .3z"/>
<path d="M62.5 58.9h1.3z"/>
<path d="M62.5 57.8h1.6z"/>
<path d="M62.5 57.3v1.1z"/>
<path d="M127.7 159.6v1.7z"/>
<path d="M127.7 161.3h.8z"/>
<path d="M128.5 161.3l.3-.3z"/>
<path d="M128.8 159.9v1.1z"/>
<path d="M128.5 159.6l.3 .3z"/>
<path d="M127.7 159.6h.8z"/>
<path d="M129.4 160.2v1.1z"/>
<path d="M129.4 160.2l.5-.6z"/>
<path d="M129.9 159.6l.5 .6z"/>
<path d="M130.4 160.2v1.1z"/>
<path d="M129.4 160.4h1z"/>
<path d="M131.5 159.6v1.7z"/>
<path d="M131 159.6h1.1z"/>
<path d="M132.6 160.2v1.1z"/>
<path d="M133.2 159.6l-.6 .6z"/>
<path d="M133.2 159.6l.5 .6z"/>
<path d="M133.7 160.2v1.1z"/>
<path d="M132.6 160.4h1.1z"/>
<path d="M134.3 161.5h1.1z"/>
<path d="M136.2 159.6h.5z"/>
<path d="M136.2 159.6l-.3 .3z"/>
<path d="M135.9 159.9v1.1z"/>
<path d="M135.9 161l.3 .3z"/>
<path d="M136.2 161.3h.5z"/>
<path d="M136.7 161.3l.3-.3z"/>
<path d="M137 159.9v1.1z"/>
<path d="M136.7 159.6l.3 .3z"/>
<path d="M137.6 159.6v1.4z"/>
<path d="M137.6 161l.2 .3z"/>
<path d="M137.8 161.3h.6z"/>
<path d="M138.6 161l-.2 .3z"/>
<path d="M138.6 159.6v1.4z"/>
<path d="M139.7 159.6v1.7z"/>
<path d="M139.2 159.6h1.1z"/>
<path d="M137.9 137.3v1.1z"/>
<path d="M138.4 136.8l-.5 .5z"/>
<path d="M138.4 136.8l.6 .5z"/>
<path d="M139 137.3v1.1z"/>
<path d="M137.9 137.6h1.1z"/>
<path d="M193.8 71.3v1.1z"/>
<path d="M193.8 71.3l.5-.5z"/>
<path d="M194.3 70.8l.5 .5z"/>
<path d="M194.8 71.3v1.1z"/>
<path d="M193.8 71.6h1z"/>
<path d="M137.9 139.3v1.6z"/>
<path d="M137.9 139.3h.8z"/>
<path d="M138.7 139.3l.3 .3z"/>
<path d="M139 139.6v.3z"/>
<path d="M139 139.9l-.3 .2z"/>
<path d="M138.7 140.1l.3 .3z"/>
<path d="M139 140.4v.3z"/>
<path d="M139 140.7l-.3 .2z"/>
<path d="M137.9 140.9h.8z"/>
<path d="M137.9 140.1h.8z"/>
<path d="M193.8 73.3v1.6z"/>
<path d="M193.8 73.3h.8z"/>
<path d="M194.6 73.3l.2 .3z"/>
<path d="M194.8 73.6v.2z"/>
<path d="M194.8 73.8l-.2 .3z"/>
<path d="M194.6 74.1l.2 .3z"/>
<path d="M194.8 74.4v.3z"/>
<path d="M194.8 74.7l-.2 .2z"/>
<path d="M193.8 74.9h.8z"/>
<path d="M193.8 74.1h.8z"/>
<path d="M138.7 141.9l.3 .2z"/>
<path d="M138.2 141.9h.5z"/>
<path d="M138.2 141.9l-.3 .2z"/>
<path d="M137.9 142.1v1.1z"/>
<path d="M137.9 143.2l.3 .3z"/>
<path d="M138.2 143.5h.5z"/>
<path d="M138.7 143.5l.3-.3z"/>
<path d="M194.6 75.8l.2 .3z"/>
<path d="M194 75.8h.6z"/>
<path d="M194 75.8l-.2 .3z"/>
<path d="M193.8 76.1v1.1z"/>
<path d="M193.8 77.2l.2 .3z"/>
<path d="M194 77.5h.6z"/>
<path d="M194.8 77.2l-.2 .3z"/>
<path d="M137.9 144.4v1.6z"/>
<path d="M137.9 146h.8z"/>
<path d="M139 145.8l-.3 .2z"/>
<path d="M139 144.7v1.1z"/>
<path d="M138.7 144.4l.3 .3z"/>
<path d="M137.9 144.4h.8z"/>
<path d="M193.8 78.4v1.6z"/>
<path d="M193.8 80h.8z"/>
<path d="M194.8 79.7l-.2 .3z"/>
<path d="M194.8 78.7v1z"/>
<path d="M194.6 78.4l.2 .3z"/>
<path d="M193.8 78.4h.8z"/>
<path d="M137.9 146.9h1.1z"/>
<path d="M137.9 146.9v1.7z"/>
<path d="M137.9 148.6h1.1z"/>
<path d="M137.9 147.7h.5z"/>
<path d="M193.8 80.9h1z"/>
<path d="M193.8 80.9v1.6z"/>
<path d="M193.8 82.5h1z"/>
<path d="M193.8 81.7h.5z"/>
<path d="M137.9 149.5v1.6z"/>
<path d="M137.9 149.5h1.1z"/>
<path d="M137.9 150.3h.5z"/>
<path d="M193.8 83.5v1.6z"/>
<path d="M193.8 83.5h1z"/>
<path d="M193.8 84.3h.5z"/>
<path d="M138.7 152l.3 .3z"/>
<path d="M138.2 152h.5z"/>
<path d="M138.2 152l-.3 .3z"/>
<path d="M137.9 152.3v1.1z"/>
<path d="M137.9 153.4l.3 .2z"/>
<path d="M138.2 153.6h.5z"/>
<path d="M139 153.4l-.3 .2z"/>
<path d="M139 152.8v.6z"/>
<path d="M138.4 152.8h.6z"/>
<path d="M194.6 86l.2 .3z"/>
<path d="M194 86h.6z"/>
<path d="M193.8 86.3l.2-.3z"/>
<path d="M193.8 86.3v1.1z"/>
<path d="M193.8 87.4l.2 .2z"/>
<path d="M194 87.6h.6z"/>
<path d="M194.6 87.6l.2-.2z"/>
<path d="M194.8 86.8v.6z"/>
<path d="M194.3 86.8h.5z"/>
<path d="M137.9 154.6v1.6z"/>
<path d="M137.9 155.4h1.1z"/>
<path d="M139 154.6v1.6z"/>
<path d="M193.8 88.5v1.6z"/>
<path d="M193.8 89.3h1z"/>
<path d="M194.8 88.5v1.6z"/>
<path d="M117.6 53.5v1.1z"/>
<path d="M118.1 53l-.5 .5z"/>
<path d="M118.1 53l.6 .5z"/>
<path d="M118.7 53.5v1.1z"/>
<path d="M117.6 53.8h1.1z"/>
<path d="M119.2 54.9h1.1z"/>
<path d="M121.1 53h.6z"/>
<path d="M121.1 53l-.3 .3z"/>
<path d="M120.8 53.3v1z"/>
<path d="M120.8 54.3l.3 .3z"/>
<path d="M121.1 54.6h.6z"/>
<path d="M121.7 54.6l.2-.3z"/>
<path d="M121.9 53.3v1z"/>
<path d="M121.7 53l.2 .3z"/>
<path d="M122.5 53v1.3z"/>
<path d="M122.5 54.3l.3 .3z"/>
<path d="M122.8 54.6h.5z"/>
<path d="M123.3 54.6l.3-.3z"/>
<path d="M123.6 53v1.3z"/>
<path d="M124.7 53v1.6z"/>
<path d="M124.1 53h1.1z"/>
<path d="M234.4 71.3v1.1z"/>
<path d="M234.4 71.3l.5-.5z"/>
<path d="M234.9 70.8l.6 .5z"/>
<path d="M235.5 71.3v1.1z"/>
<path d="M234.4 71.6h1.1z"/>
<path d="M236 72.6h1.1z"/>
<path d="M237.9 70.8h.6z"/>
<path d="M237.9 70.8l-.2 .2z"/>
<path d="M237.7 71v1.1z"/>
<path d="M237.7 72.1l.2 .3z"/>
<path d="M237.9 72.4h.6z"/>
<path d="M238.5 72.4l.3-.3z"/>
<path d="M238.8 71v1.1z"/>
<path d="M238.5 70.8l.3 .2z"/>
<path d="M239.3 70.8v1.3z"/>
<path d="M239.3 72.1l.3 .3z"/>
<path d="M239.6 72.4h.5z"/>
<path d="M240.1 72.4l.3-.3z"/>
<path d="M240.4 70.8v1.3z"/>
<path d="M241.5 70.8v1.6z"/>
<path d="M240.9 70.8h1.1z"/>
<path d="M117.6 58.1v1.6z"/>
<path d="M117.6 58.1h.8z"/>
<path d="M118.4 58.1l.3 .2z"/>
<path d="M118.7 58.3v.3z"/>
<path d="M118.4 58.9l.3-.3z"/>
<path d="M118.4 58.9l.3 .2z"/>
<path d="M118.7 59.1v.3z"/>
<path d="M118.7 59.4l-.3 .3z"/>
<path d="M117.6 59.7h.8z"/>
<path d="M117.6 58.9h.8z"/>
<path d="M119.2 60h1.1z"/>
<path d="M121.1 58.1h.6z"/>
<path d="M121.1 58.1l-.3 .2z"/>
<path d="M120.8 58.3v1.1z"/>
<path d="M120.8 59.4l.3 .3z"/>
<path d="M121.1 59.7h.6z"/>
<path d="M121.7 59.7l.2-.3z"/>
<path d="M121.9 58.3v1.1z"/>
<path d="M121.7 58.1l.2 .2z"/>
<path d="M122.5 58.1v1.3z"/>
<path d="M122.5 59.4l.3 .3z"/>
<path d="M122.8 59.7h.5z"/>
<path d="M123.3 59.7l.3-.3z"/>
<path d="M123.6 58.1v1.3z"/>
<path d="M124.7 58.1v1.6z"/>
<path d="M124.1 58.1h1.1z"/>
<path d="M234.4 73.3v1.6z"/>
<path d="M234.4 73.3h.8z"/>
<path d="M235.2 73.3l.3 .3z"/>
<path d="M235.5 73.6v.2z"/>
<path d="M235.2 74.1l.3-.3z"/>
<path d="M235.2 74.1l.3 .3z"/>
<path d="M235.5 74.4v.3z"/>
<path d="M235.2 74.9l.3-.2z"/>
<path d="M234.4 74.9h.8z"/>
<path d="M234.4 74.1h.8z"/>
<path d="M236 75.2h1.1z"/>
<path d="M237.9 73.3h.6z"/>
<path d="M237.9 73.3l-.2 .3z"/>
<path d="M237.7 73.6v1.1z"/>
<path d="M237.7 74.7l.2 .2z"/>
<path d="M237.9 74.9h.6z"/>
<path d="M238.5 74.9l.3-.2z"/>
<path d="M238.8 73.6v1.1z"/>
<path d="M238.5 73.3l.3 .3z"/>
<path d="M239.3 73.3v1.4z"/>
<path d="M239.3 74.7l.3 .2z"/>
<path d="M239.6 74.9h.5z"/>
<path d="M240.1 74.9l.3-.2z"/>
<path d="M240.4 73.3v1.4z"/>
<path d="M241.5 73.3v1.6z"/>
<path d="M240.9 73.3h1.1z"/>
<path d="M118.4 63.1l.3 .3z"/>
<path d="M117.9 63.1h.5z"/>
<path d="M117.9 63.1l-.3 .3z"/>
<path d="M117.6 63.4v1.1z"/>
<path d="M117.6 64.5l.3 .3z"/>
<path d="M117.9 64.8h.5z"/>
<path d="M118.7 64.5l-.3 .3z"/>
<path d="M119.2 65h1.1z"/>
<path d="M121.1 63.1h.6z"/>
<path d="M121.1 63.1l-.3 .3z"/>
<path d="M120.8 63.4v1.1z"/>
<path d="M120.8 64.5l.3 .3z"/>
<path d="M121.1 64.8h.6z"/>
<path d="M121.7 64.8l.2-.3z"/>
<path d="M121.9 63.4v1.1z"/>
<path d="M121.7 63.1l.2 .3z"/>
<path d="M122.5 63.1v1.4z"/>
<path d="M122.5 64.5l.3 .3z"/>
<path d="M122.8 64.8h.5z"/>
<path d="M123.3 64.8l.3-.3z"/>
<path d="M123.6 63.1v1.4z"/>
<path d="M124.7 63.1v1.7z"/>
<path d="M124.1 63.1h1.1z"/>
<path d="M235.2 75.8l.3 .3z"/>
<path d="M234.7 75.8h.5z"/>
<path d="M234.7 75.8l-.3 .3z"/>
<path d="M234.4 76.1v1.1z"/>
<path d="M234.4 77.2l.3 .3z"/>
<path d="M234.7 77.5h.5z"/>
<path d="M235.2 77.5l.3-.3z"/>
<path d="M236 77.7h1.1z"/>
<path d="M237.9 75.8h.6z"/>
<path d="M237.9 75.8l-.2 .3z"/>
<path d="M237.7 76.1v1.1z"/>
<path d="M237.7 77.2l.2 .3z"/>
<path d="M237.9 77.5h.6z"/>
<path d="M238.5 77.5l.3-.3z"/>
<path d="M238.8 76.1v1.1z"/>
<path d="M238.5 75.8l.3 .3z"/>
<path d="M239.3 75.8v1.4z"/>
<path d="M239.3 77.2l.3 .3z"/>
<path d="M239.6 77.5h.5z"/>
<path d="M240.1 77.5l.3-.3z"/>
<path d="M240.4 75.8v1.4z"/>
<path d="M241.5 75.8v1.7z"/>
<path d="M240.9 75.8h1.1z"/>
<path d="M117.6 68.2v1.6z"/>
<path d="M117.6 69.8h.8z"/>
<path d="M118.4 69.8l.3-.2z"/>
<path d="M118.7 68.5v1.1z"/>
<path d="M118.4 68.2l.3 .3z"/>
<path d="M117.6 68.2h.8z"/>
<path d="M119.2 70.1h1.1z"/>
<path d="M121.1 68.2h.6z"/>
<path d="M121.1 68.2l-.3 .3z"/>
<path d="M120.8 68.5v1.1z"/>
<path d="M120.8 69.6l.3 .2z"/>
<path d="M121.1 69.8h.6z"/>
<path d="M121.7 69.8l.2-.2z"/>
<path d="M121.9 68.5v1.1z"/>
<path d="M121.7 68.2l.2 .3z"/>
<path d="M122.5 68.2v1.4z"/>
<path d="M122.5 69.6l.3 .2z"/>
<path d="M122.8 69.8h.5z"/>
<path d="M123.3 69.8l.3-.2z"/>
<path d="M123.6 68.2v1.4z"/>
<path d="M124.7 68.2v1.6z"/>
<path d="M124.1 68.2h1.1z"/>
<path d="M234.4 78.4v1.6z"/>
<path d="M234.4 80h.8z"/>
<path d="M235.2 80l.3-.3z"/>
<path d="M235.5 78.7v1z"/>
<path d="M235.2 78.4l.3 .3z"/>
<path d="M234.4 78.4h.8z"/>
<path d="M236 80.3h1.1z"/>
<path d="M237.9 78.4h.6z"/>
<path d="M237.9 78.4l-.2 .3z"/>
<path d="M237.7 78.7v1z"/>
<path d="M237.7 79.7l.2 .3z"/>
<path d="M237.9 80h.6z"/>
<path d="M238.5 80l.3-.3z"/>
<path d="M238.8 78.7v1z"/>
<path d="M238.5 78.4l.3 .3z"/>
<path d="M239.3 78.4v1.3z"/>
<path d="M239.3 79.7l.3 .3z"/>
<path d="M239.6 80h.5z"/>
<path d="M240.1 80l.3-.3z"/>
<path d="M240.4 78.4v1.3z"/>
<path d="M241.5 78.4v1.6z"/>
<path d="M240.9 78.4h1.1z"/>
<path d="M117.6 73.3h1.1z"/>
<path d="M117.6 73.3v1.6z"/>
<path d="M117.6 74.9h1.1z"/>
<path d="M117.6 74.1h.5z"/>
<path d="M119.2 75.2h1.1z"/>
<path d="M121.1 73.3h.6z"/>
<path d="M121.1 73.3l-.3 .3z"/>
<path d="M120.8 73.6v1.1z"/>
<path d="M120.8 74.7l.3 .2z"/>
<path d="M121.1 74.9h.6z"/>
<path d="M121.7 74.9l.2-.2z"/>
<path d="M121.9 73.6v1.1z"/>
<path d="M121.7 73.3l.2 .3z"/>
<path d="M122.5 73.3v1.4z"/>
<path d="M122.5 74.7l.3 .2z"/>
<path d="M122.8 74.9h.5z"/>
<path d="M123.3 74.9l.3-.2z"/>
<path d="M123.6 73.3v1.4z"/>
<path d="M124.7 73.3v1.6z"/>
<path d="M124.1 73.3h1.1z"/>
<path d="M234.4 80.9h1.1z"/>
<path d="M234.4 80.9v1.6z"/>
<path d="M234.4 82.5h1.1z"/>
<path d="M234.4 81.7h.5z"/>
<path d="M236 82.8h1.1z"/>
<path d="M237.9 80.9h.6z"/>
<path d="M237.9 80.9l-.2 .3z"/>
<path d="M237.7 81.2v1.1z"/>
<path d="M237.7 82.3l.2 .2z"/>
<path d="M237.9 82.5h.6z"/>
<path d="M238.5 82.5l.3-.2z"/>
<path d="M238.8 81.2v1.1z"/>
<path d="M238.5 80.9l.3 .3z"/>
<path d="M239.3 80.9v1.4z"/>
<path d="M239.3 82.3l.3 .2z"/>
<path d="M239.6 82.5h.5z"/>
<path d="M240.1 82.5l.3-.2z"/>
<path d="M240.4 80.9v1.4z"/>
<path d="M241.5 80.9v1.6z"/>
<path d="M240.9 80.9h1.1z"/>
<path d="M117.6 78.4v1.6z"/>
<path d="M117.6 78.4h1.1z"/>
<path d="M117.6 79.2h.5z"/>
<path d="M119.2 80.3h1.1z"/>
<path d="M121.1 78.4h.6z"/>
<path d="M121.1 78.4l-.3 .3z"/>
<path d="M120.8 78.7v1z"/>
<path d="M120.8 79.7l.3 .3z"/>
<path d="M121.1 80h.6z"/>
<path d="M121.7 80l.2-.3z"/>
<path d="M121.9 78.7v1z"/>
<path d="M121.7 78.4l.2 .3z"/>
<path d="M122.5 78.4v1.3z"/>
<path d="M122.5 79.7l.3 .3z"/>
<path d="M122.8 80h.5z"/>
<path d="M123.3 80l.3-.3z"/>
<path d="M123.6 78.4v1.3z"/>
<path d="M124.7 78.4v1.6z"/>
<path d="M124.1 78.4h1.1z"/>
<path d="M234.4 83.5v1.6z"/>
<path d="M234.4 83.5h1.1z"/>
<path d="M234.4 84.3h.5z"/>
<path d="M236 85.3h1.1z"/>
<path d="M237.9 83.5h.6z"/>
<path d="M237.9 83.5l-.2 .2z"/>
<path d="M237.7 83.7v1.1z"/>
<path d="M237.7 84.8l.2 .3z"/>
<path d="M237.9 85.1h.6z"/>
<path d="M238.5 85.1l.3-.3z"/>
<path d="M238.8 83.7v1.1z"/>
<path d="M238.5 83.5l.3 .2z"/>
<path d="M239.3 83.5v1.3z"/>
<path d="M239.3 84.8l.3 .3z"/>
<path d="M239.6 85.1h.5z"/>
<path d="M240.1 85.1l.3-.3z"/>
<path d="M240.4 83.5v1.3z"/>
<path d="M241.5 83.5v1.6z"/>
<path d="M240.9 83.5h1.1z"/>
<path d="M118.4 83.5l.3 .2z"/>
<path d="M117.9 83.5h.5z"/>
<path d="M117.6 83.7l.3-.2z"/>
<path d="M117.6 83.7v1.1z"/>
<path d="M117.6 84.8l.3 .3z"/>
<path d="M117.9 85.1h.5z"/>
<path d="M118.4 85.1l.3-.3z"/>
<path d="M118.7 84.3v.5z"/>
<path d="M118.1 84.3h.6z"/>
<path d="M119.2 85.3h1.1z"/>
<path d="M121.1 83.5h.6z"/>
<path d="M120.8 83.7l.3-.2z"/>
<path d="M120.8 83.7v1.1z"/>
<path d="M120.8 84.8l.3 .3z"/>
<path d="M121.1 85.1h.6z"/>
<path d="M121.7 85.1l.2-.3z"/>
<path d="M121.9 83.7v1.1z"/>
<path d="M121.7 83.5l.2 .2z"/>
<path d="M122.5 83.5v1.3z"/>
<path d="M122.5 84.8l.3 .3z"/>
<path d="M122.8 85.1h.5z"/>
<path d="M123.3 85.1l.3-.3z"/>
<path d="M123.6 83.5v1.3z"/>
<path d="M124.7 83.5v1.6z"/>
<path d="M124.1 83.5h1.1z"/>
<path d="M235.2 86l.3 .3z"/>
<path d="M234.7 86h.5z"/>
<path d="M234.4 86.3l.3-.3z"/>
<path d="M234.4 86.3v1.1z"/>
<path d="M234.4 87.4l.3 .2z"/>
<path d="M234.7 87.6h.5z"/>
<path d="M235.2 87.6l.3-.2z"/>
<path d="M235.5 86.8v.6z"/>
<path d="M234.9 86.8h.6z"/>
<path d="M236 87.9h1.1z"/>
<path d="M237.9 86h.6z"/>
<path d="M237.9 86l-.2 .3z"/>
<path d="M237.7 86.3v1.1z"/>
<path d="M237.7 87.4l.2 .2z"/>
<path d="M237.9 87.6h.6z"/>
<path d="M238.5 87.6l.3-.2z"/>
<path d="M238.8 86.3v1.1z"/>
<path d="M238.5 86l.3 .3z"/>
<path d="M239.3 86v1.4z"/>
<path d="M239.3 87.4l.3 .2z"/>
<path d="M239.6 87.6h.5z"/>
<path d="M240.1 87.6l.3-.2z"/>
<path d="M240.4 86v1.4z"/>
<path d="M241.5 86v1.6z"/>
<path d="M240.9 86h1.1z"/>
<path d="M117.6 88.5v1.6z"/>
<path d="M117.6 89.3h1.1z"/>
<path d="M118.7 88.5v1.6z"/>
<path d="M119.2 90.4h1.1z"/>
<path d="M121.1 88.5h.6z"/>
<path d="M120.8 88.8l.3-.3z"/>
<path d="M120.8 88.8v1.1z"/>
<path d="M120.8 89.9l.3 .2z"/>
<path d="M121.1 90.1h.6z"/>
<path d="M121.7 90.1l.2-.2z"/>
<path d="M121.9 88.8v1.1z"/>
<path d="M121.7 88.5l.2 .3z"/>
<path d="M122.5 88.5v1.4z"/>
<path d="M122.5 89.9l.3 .2z"/>
<path d="M122.8 90.1h.5z"/>
<path d="M123.3 90.1l.3-.2z"/>
<path d="M123.6 88.5v1.4z"/>
<path d="M124.7 88.5v1.6z"/>
<path d="M124.1 88.5h1.1z"/>
<path d="M234.4 88.5v1.6z"/>
<path d="M234.4 89.3h1.1z"/>
<path d="M235.5 88.5v1.6z"/>
<path d="M236 90.4h1.1z"/>
<path d="M237.9 88.5h.6z"/>
<path d="M237.9 88.5l-.2 .3z"/>
<path d="M237.7 88.8v1.1z"/>
<path d="M237.7 89.9l.2 .2z"/>
<path d="M237.9 90.1h.6z"/>
<path d="M238.5 90.1l.3-.2z"/>
<path d="M238.8 88.8v1.1z"/>
<path d="M238.5 88.5l.3 .3z"/>
<path d="M239.3 88.5v1.4z"/>
<path d="M239.3 89.9l.3 .2z"/>
<path d="M239.6 90.1h.5z"/>
<path d="M240.1 90.1l.3-.2z"/>
<path d="M240.4 88.5v1.4z"/>
<path d="M241.5 88.5v1.6z"/>
<path d="M240.9 88.5h1.1z"/>
</g>
<g fill="#800000" stroke="#800000" stroke-width=".21">
<path d="M75.2 174.9l.3 .3z"/>
<path d="M74.7 174.9h.5z"/>
<path d="M74.7 174.9l-.3 .3z"/>
<path d="M74.4 175.2v.2z"/>
<path d="M74.4 175.4l.3 .3z"/>
<path d="M74.7 175.7h.5z"/>
<path d="M75.2 175.7l.3 .3z"/>
<path d="M75.5 176v.2z"/>
<path d="M75.5 176.2l-.3 .3z"/>
<path d="M74.7 176.5h.5z"/>
<path d="M74.4 176.2l.3 .3z"/>
<path d="M76 174.9v1.6z"/>
<path d="M76 175.7l.3-.3z"/>
<path d="M76.3 175.4h.6z"/>
<path d="M76.9 175.4l.2 .3z"/>
<path d="M77.1 175.7v.8z"/>
<path d="M77.7 175.4h.3z"/>
<path d="M78 175.4v1.1z"/>
<path d="M77.7 176.5h.5z"/>
<path d="M78 174.6v.3z"/>
<path d="M79 175.2v1.3z"/>
<path d="M79 175.2l.3-.3z"/>
<path d="M78.8 175.7h.5z"/>
<path d="M80.1 175.2v1z"/>
<path d="M80.1 176.2l.3 .3z"/>
<path d="M79.9 175.4h.5z"/>
<path d="M82.6 174.9v1.6z"/>
<path d="M82.6 174.9h.8z"/>
<path d="M83.4 174.9l.3 .3z"/>
<path d="M83.7 175.2v.5z"/>
<path d="M83.7 175.7l-.3 .3z"/>
<path d="M82.6 176h.8z"/>
<path d="M83.1 176l.6 .5z"/>
<path d="M84.5 176.5h.5z"/>
<path d="M84.2 176.2l.3 .3z"/>
<path d="M84.2 175.7v.5z"/>
<path d="M84.2 175.7l.3-.3z"/>
<path d="M84.5 175.4h.5z"/>
<path d="M85 175.4l.3 .3z"/>
<path d="M85.3 175.7v.3z"/>
<path d="M84.2 176h1.1z"/>
<path d="M86.4 177h.3z"/>
<path d="M86.7 177l.3-.2z"/>
<path d="M87 175.4v1.4z"/>
<path d="M86.1 175.4h.9z"/>
<path d="M86.1 175.4l-.2 .3z"/>
<path d="M85.9 175.7v.5z"/>
<path d="M85.9 176.2l.2 .3z"/>
<path d="M86.1 176.5h.9z"/>
<path d="M87.5 175.4h.3z"/>
<path d="M87.8 175.4v1.1z"/>
<path d="M87.5 176.5h.5z"/>
<path d="M87.8 174.6v.3z"/>
<path d="M88.6 176.5h.8z"/>
<path d="M89.7 176.2l-.3 .3z"/>
<path d="M89.4 176l.3 .2z"/>
<path d="M88.9 176h.5z"/>
<path d="M88.6 175.7l.3 .3z"/>
<path d="M88.6 175.7l.3-.3z"/>
<path d="M88.9 175.4h.8z"/>
<path d="M90.5 175.2v1z"/>
<path d="M90.5 176.2l.3 .3z"/>
<path d="M90.2 175.4h.6z"/>
<path d="M91.6 176.5h.5z"/>
<path d="M91.3 176.2l.3 .3z"/>
<path d="M91.3 175.7v.5z"/>
<path d="M91.3 175.7l.3-.3z"/>
<path d="M91.6 175.4h.5z"/>
<path d="M92.1 175.4l.3 .3z"/>
<path d="M92.4 175.7v.3z"/>
<path d="M91.3 176h1.1z"/>
<path d="M93 175.4v1.1z"/>
<path d="M93.5 175.4l-.5 .6z"/>
<path d="M93.5 175.4h.3z"/>
<path d="M72.7 63.1l.2 .3z"/>
<path d="M72.1 63.1h.6z"/>
<path d="M72.1 63.1l-.2 .3z"/>
<path d="M71.9 63.4v1.1z"/>
<path d="M71.9 64.5l.2 .3z"/>
<path d="M72.1 64.8h.6z"/>
<path d="M72.9 64.5l-.2 .3z"/>
<path d="M73.5 63.1v1.7z"/>
<path d="M73.5 63.9l.3-.2z"/>
<path d="M73.8 63.7h.5z"/>
<path d="M74.3 63.7l.3 .2z"/>
<path d="M74.6 63.9v.9z"/>
<path d="M75.4 63.7h.5z"/>
<path d="M75.9 63.7l.3 .2z"/>
<path d="M76.2 63.9v.9z"/>
<path d="M75.4 64.8h.8z"/>
<path d="M75.1 64.5l.3 .3z"/>
<path d="M75.1 64.5l.3-.3z"/>
<path d="M75.4 64.2h.8z"/>
<path d="M76.8 63.7h.2z"/>
<path d="M77 63.7v1.1z"/>
<path d="M76.8 64.8h.5z"/>
<path d="M77 62.9v.2z"/>
<path d="M77.9 63.7v1.1z"/>
<path d="M77.9 63.7h.8z"/>
<path d="M78.7 63.7l.3 .2z"/>
<path d="M79 63.9v.9z"/>
<path d="M79.5 63.7h.3z"/>
<path d="M79.8 63.7v1.1z"/>
<path d="M79.5 64.8h.6z"/>
<path d="M79.8 62.9v.2z"/>
<path d="M80.6 63.7v1.1z"/>
<path d="M80.6 63.7h.8z"/>
<path d="M81.4 63.7l.3 .2z"/>
<path d="M81.7 63.9v.9z"/>
<path d="M82.8 65.3h.2z"/>
<path d="M83 65.3l.3-.3z"/>
<path d="M83.3 63.7v1.3z"/>
<path d="M82.5 63.7h.8z"/>
<path d="M82.5 63.7l-.3 .2z"/>
<path d="M82.2 63.9v.6z"/>
<path d="M82.2 64.5l.3 .3z"/>
<path d="M82.5 64.8h.8z"/>
<path d="M86.3 63.1l.3 .3z"/>
<path d="M85.8 63.1h.5z"/>
<path d="M85.8 63.1l-.3 .3z"/>
<path d="M85.5 63.4v1.1z"/>
<path d="M85.5 64.5l.3 .3z"/>
<path d="M85.8 64.8h.5z"/>
<path d="M86.3 64.8l.3-.3z"/>
<path d="M87.4 64.8h.5z"/>
<path d="M87.9 64.8l.3-.3z"/>
<path d="M88.2 63.9v.6z"/>
<path d="M87.9 63.7l.3 .2z"/>
<path d="M87.4 63.7h.5z"/>
<path d="M87.4 63.7l-.3 .2z"/>
<path d="M87.1 63.9v.6z"/>
<path d="M87.1 64.5l.3 .3z"/>
<path d="M88.8 63.7v1.1z"/>
<path d="M88.8 63.7h.8z"/>
<path d="M89.6 63.7l.3 .2z"/>
<path d="M89.9 63.9v.9z"/>
<path d="M90.4 63.7v1.1z"/>
<path d="M90.4 63.7h.8z"/>
<path d="M91.2 63.7l.3 .2z"/>
<path d="M91.5 63.9v.9z"/>
<path d="M92.3 64.8h.6z"/>
<path d="M92.1 64.5l.2 .3z"/>
<path d="M92.1 63.9v.6z"/>
<path d="M92.1 63.9l.2-.2z"/>
<path d="M92.3 63.7h.6z"/>
<path d="M92.9 63.7l.2 .2z"/>
<path d="M93.1 63.9v.3z"/>
<path d="M92.1 64.2h1z"/>
<path d="M94 63.7h.8z"/>
<path d="M94 63.7l-.3 .2z"/>
<path d="M93.7 63.9v.6z"/>
<path d="M93.7 64.5l.3 .3z"/>
<path d="M94 64.8h.8z"/>
<path d="M95.6 63.4v1.1z"/>
<path d="M95.6 64.5l.3 .3z"/>
<path d="M95.3 63.7h.6z"/>
<path d="M96.7 64.8h.5z"/>
<path d="M97.5 64.5l-.3 .3z"/>
<path d="M97.5 63.9v.6z"/>
<path d="M97.2 63.7l.3 .2z"/>
<path d="M96.7 63.7h.5z"/>
<path d="M96.7 63.7l-.3 .2z"/>
<path d="M96.4 63.9v.6z"/>
<path d="M96.4 64.5l.3 .3z"/>
<path d="M98 63.7v1.1z"/>
<path d="M98 64.2l.6-.5z"/>
<path d="M98.6 63.7h.3z"/>
<path d="M99.4 64.8h.8z"/>
<path d="M100.5 64.5l-.3 .3z"/>
<path d="M100.2 64.2l.3 .3z"/>
<path d="M99.7 64.2h.5z"/>
<path d="M99.4 63.9l.3 .3z"/>
<path d="M99.4 63.9l.3-.2z"/>
<path d="M99.7 63.7h.8z"/>
<path d="M122.9 101.2h.6z"/>
<path d="M122.9 101.2l-.2 .3z"/>
<path d="M122.7 101.5v1.1z"/>
<path d="M122.7 102.6l.2 .2z"/>
<path d="M122.9 102.8h.6z"/>
<path d="M123.5 102.8l.2-.2z"/>
<path d="M123.7 101.5v1.1z"/>
<path d="M123.5 101.2l.2 .3z"/>
<path d="M124.3 101.8v.8z"/>
<path d="M124.3 102.6l.3 .2z"/>
<path d="M124.6 102.8h.8z"/>
<path d="M125.4 101.8v1z"/>
<path d="M126.2 101.5v1.1z"/>
<path d="M126.2 102.6l.3 .2z"/>
<path d="M125.9 101.8h.6z"/>
<path d="M127 101.8v1.6z"/>
<path d="M127 101.8h.8z"/>
<path d="M127.8 101.8l.3 .2z"/>
<path d="M128.1 102v.6z"/>
<path d="M127.8 102.8l.3-.2z"/>
<path d="M127 102.8h.8z"/>
<path d="M128.6 101.8v.8z"/>
<path d="M128.6 102.6l.3 .2z"/>
<path d="M128.9 102.8h.8z"/>
<path d="M129.7 101.8v1z"/>
<path d="M130.6 101.5v1.1z"/>
<path d="M130.6 102.6l.2 .2z"/>
<path d="M130.3 101.8h.5z"/>
<path d="M133 101.2v1.6z"/>
<path d="M133 101.2h.8z"/>
<path d="M133.8 101.2l.3 .3z"/>
<path d="M134.1 101.5v.5z"/>
<path d="M134.1 102l-.3 .3z"/>
<path d="M133 102.3h.8z"/>
<path d="M134.9 102.8h.6z"/>
<path d="M135.5 102.8l.2-.2z"/>
<path d="M135.7 102v.6z"/>
<path d="M135.5 101.8l.2 .2z"/>
<path d="M134.9 101.8h.6z"/>
<path d="M134.9 101.8l-.2 .2z"/>
<path d="M134.7 102v.6z"/>
<path d="M134.7 102.6l.2 .2z"/>
<path d="M136.3 101.8v1z"/>
<path d="M136.3 102.3l.5-.5z"/>
<path d="M136.8 101.8h.3z"/>
<path d="M137.9 101.5v1.1z"/>
<path d="M137.9 102.6l.3 .2z"/>
<path d="M137.7 101.8h.5z"/>
<path d="M138.7 102.8h.9z"/>
<path d="M139.6 102.8l.2-.2z"/>
<path d="M139.6 102.3l.2 .3z"/>
<path d="M139 102.3h.6z"/>
<path d="M138.7 102l.3 .3z"/>
<path d="M138.7 102l.3-.2z"/>
<path d="M139 101.8h.8z"/>
<path d="M196.3 119v1.6z"/>
<path d="M196.3 120.6h.8z"/>
<path d="M197.4 120.4l-.3 .2z"/>
<path d="M197.4 119.3v1.1z"/>
<path d="M197.1 119l.3 .3z"/>
<path d="M196.3 119h.8z"/>
<path d="M198.2 119.5h.6z"/>
<path d="M198.8 119.5l.2 .3z"/>
<path d="M199 119.8v.8z"/>
<path d="M198.2 120.6h.8z"/>
<path d="M197.9 120.4l.3 .2z"/>
<path d="M197.9 120.4l.3-.3z"/>
<path d="M198.2 120.1h.8z"/>
<path d="M199.6 119.5v1.1z"/>
<path d="M200.1 119.5l-.5 .6z"/>
<path d="M200.1 119.5h.3z"/>
<path d="M200.9 119h.3z"/>
<path d="M201.2 119v1.6z"/>
<path d="M200.9 120.6h.6z"/>
<path d="M202 119.5h.3z"/>
<path d="M202.3 119.5v1.1z"/>
<path d="M202 120.6h.6z"/>
<path d="M202.3 118.7v.3z"/>
<path d="M203.1 119.5v1.1z"/>
<path d="M203.1 119.5h.8z"/>
<path d="M203.9 119.5l.3 .3z"/>
<path d="M204.2 119.8v.8z"/>
<path d="M205.3 121.2h.3z"/>
<path d="M205.6 121.2l.2-.3z"/>
<path d="M205.8 119.5v1.4z"/>
<path d="M205 119.5h.8z"/>
<path d="M205 119.5l-.2 .3z"/>
<path d="M204.8 119.8v.6z"/>
<path d="M204.8 120.4l.2 .2z"/>
<path d="M205 120.6h.8z"/>
<path d="M206.7 119.3v1.1z"/>
<path d="M206.7 120.4l.2 .2z"/>
<path d="M206.4 119.5h.5z"/>
<path d="M207.7 120.6h.6z"/>
<path d="M208.3 120.6l.3-.2z"/>
<path d="M208.6 119.8v.6z"/>
<path d="M208.3 119.5l.3 .3z"/>
<path d="M207.7 119.5h.6z"/>
<path d="M207.7 119.5l-.2 .3z"/>
<path d="M207.5 119.8v.6z"/>
<path d="M207.5 120.4l.2 .2z"/>
<path d="M209.1 119.5v1.1z"/>
<path d="M209.1 119.5h.8z"/>
<path d="M209.9 119.5l.3 .3z"/>
<path d="M210.2 119.8v.8z"/>
<path d="M213.2 119l.3 .3z"/>
<path d="M212.7 119h.5z"/>
<path d="M212.7 119l-.3 .3z"/>
<path d="M212.4 119.3v.2z"/>
<path d="M212.4 119.5l.3 .3z"/>
<path d="M212.7 119.8h.5z"/>
<path d="M213.2 119.8l.3 .3z"/>
<path d="M213.5 120.1v.3z"/>
<path d="M213.5 120.4l-.3 .2z"/>
<path d="M212.7 120.6h.5z"/>
<path d="M212.4 120.4l.3 .2z"/>
<path d="M214 119.5v.9z"/>
<path d="M214 120.4l.3 .2z"/>
<path d="M214.3 120.6l.3-.2z"/>
<path d="M214.6 120.4l.2 .2z"/>
<path d="M215.1 120.4l-.3 .2z"/>
<path d="M215.1 119.5v.9z"/>
<path d="M215.7 119.5h.2z"/>
<path d="M215.9 119.5v1.1z"/>
<path d="M215.7 120.6h.5z"/>
<path d="M215.9 118.7v.3z"/>
<path d="M217 119.3v1.1z"/>
<path d="M217 120.4l.3 .2z"/>
<path d="M216.8 119.5h.5z"/>
<path d="M218.1 119.5h.8z"/>
<path d="M218.1 119.5l-.3 .3z"/>
<path d="M217.8 119.8v.6z"/>
<path d="M217.8 120.4l.3 .2z"/>
<path d="M218.1 120.6h.8z"/>
<path d="M219.5 119v1.6z"/>
<path d="M219.5 119.8l.3-.3z"/>
<path d="M219.8 119.5h.5z"/>
<path d="M220.3 119.5l.3 .3z"/>
<path d="M220.6 119.8v.8z"/>
<path d="M221.1 119.5h.3z"/>
<path d="M221.4 119.5v1.1z"/>
<path d="M221.1 120.6h.6z"/>
<path d="M221.4 118.7v.3z"/>
<path d="M222.2 119.5v1.1z"/>
<path d="M222.2 119.5h.8z"/>
<path d="M223 119.5l.3 .3z"/>
<path d="M223.3 119.8v.8z"/>
<path d="M224.4 121.2h.3z"/>
<path d="M224.7 121.2l.2-.3z"/>
<path d="M224.9 119.5v1.4z"/>
<path d="M224.1 119.5h.8z"/>
<path d="M224.1 119.5l-.2 .3z"/>
<path d="M223.9 119.8v.6z"/>
<path d="M223.9 120.4l.2 .2z"/>
<path d="M224.1 120.6h.8z"/>
<path d="M227.9 119l.3 .3z"/>
<path d="M227.4 119h.5z"/>
<path d="M227.4 119l-.3 .3z"/>
<path d="M227.1 119.3v.2z"/>
<path d="M227.1 119.5l.3 .3z"/>
<path d="M227.4 119.8h.5z"/>
<path d="M227.9 119.8l.3 .3z"/>
<path d="M228.2 120.1v.3z"/>
<path d="M228.2 120.4l-.3 .2z"/>
<path d="M227.4 120.6h.5z"/>
<path d="M227.1 120.4l.3 .2z"/>
<path d="M229 120.6h.6z"/>
<path d="M228.8 120.4l.2 .2z"/>
<path d="M228.8 119.8v.6z"/>
<path d="M228.8 119.8l.2-.3z"/>
<path d="M229 119.5h.6z"/>
<path d="M229.6 119.5l.2 .3z"/>
<path d="M229.8 119.8v.3z"/>
<path d="M228.8 120.1h1z"/>
<path d="M230.9 121.2h.3z"/>
<path d="M231.5 120.9l-.3 .3z"/>
<path d="M231.5 119.5v1.4z"/>
<path d="M230.7 119.5h.8z"/>
<path d="M230.7 119.5l-.3 .3z"/>
<path d="M230.4 119.8v.6z"/>
<path d="M230.4 120.4l.3 .2z"/>
<path d="M230.7 120.6h.8z"/>
<path d="M232 119.5v1.1z"/>
<path d="M232 119.5h.3z"/>
<path d="M232.3 119.5l.3 .3z"/>
<path d="M232.6 119.8v.8z"/>
<path d="M232.6 119.8l.3-.3z"/>
<path d="M232.9 119.5l.2 .3z"/>
<path d="M233.1 119.8v.8z"/>
<path d="M234 120.6h.5z"/>
<path d="M233.7 120.4l.3 .2z"/>
<path d="M233.7 119.8v.6z"/>
<path d="M233.7 119.8l.3-.3z"/>
<path d="M234 119.5h.5z"/>
<path d="M234.5 119.5l.3 .3z"/>
<path d="M234.8 119.8v.3z"/>
<path d="M233.7 120.1h1.1z"/>
<path d="M235.3 119.5v1.1z"/>
<path d="M235.3 119.5h.8z"/>
<path d="M236.1 119.5l.3 .3z"/>
<path d="M236.4 119.8v.8z"/>
<path d="M237.2 119.3v1.1z"/>
<path d="M237.2 120.4l.3 .2z"/>
<path d="M237 119.5h.5z"/>
<path d="M182.3 171.6l.3 .4z"/>
<path d="M181.5 171.6h.8z"/>
<path d="M181.1 172l.4-.4z"/>
<path d="M181.1 172v1.5z"/>
<path d="M181.1 173.5l.4 .4z"/>
<path d="M181.5 173.9h.8z"/>
<path d="M182.3 173.9l.3-.4z"/>
<path d="M183.4 171.6v2.3z"/>
<path d="M183.4 172.8l.4-.4z"/>
<path d="M183.8 172.4h.8z"/>
<path d="M184.6 172.4l.4 .4z"/>
<path d="M185 172.8v1.1z"/>
<path d="M186.2 172.4h.7z"/>
<path d="M186.9 172.4l.4 .4z"/>
<path d="M187.3 172.8v1.1z"/>
<path d="M186.2 173.9h1.1z"/>
<path d="M185.8 173.5l.4 .4z"/>
<path d="M185.8 173.5l.4-.3z"/>
<path d="M186.2 173.2h1.1z"/>
<path d="M188.1 172.4h.4z"/>
<path d="M188.5 172.4v1.5z"/>
<path d="M188.1 173.9h.8z"/>
<path d="M188.5 171.2v.4z"/>
<path d="M189.7 172.4v1.5z"/>
<path d="M189.7 172.4h1.1z"/>
<path d="M190.8 172.4l.4 .4z"/>
<path d="M191.2 172.8v1.1z"/>
<path d="M192.4 172.4h.8z"/>
<path d="M193.2 172.4l.4 .4z"/>
<path d="M193.6 172.8v1.1z"/>
<path d="M192.4 173.9h1.2z"/>
<path d="M192 173.5l.4 .4z"/>
<path d="M192 173.5l.4-.3z"/>
<path d="M192.4 173.2h1.2z"/>
<path d="M194.3 171.6v2.3z"/>
<path d="M194.3 173.9h1.2z"/>
<path d="M195.5 173.9l.4-.4z"/>
<path d="M195.9 172.8v.7z"/>
<path d="M195.5 172.4l.4 .4z"/>
<path d="M194.3 172.4h1.2z"/>
<path d="M196.7 171.6h.4z"/>
<path d="M197.1 171.6v2.3z"/>
<path d="M196.7 173.9h.8z"/>
<path d="M198.6 173.9h.8z"/>
<path d="M198.2 173.5l.4 .4z"/>
<path d="M198.2 172.8v.7z"/>
<path d="M198.2 172.8l.4-.4z"/>
<path d="M198.6 172.4h.8z"/>
<path d="M199.4 172.4l.4 .4z"/>
<path d="M199.8 172.8v.4z"/>
<path d="M198.2 173.2h1.6z"/>
<path d="M202.9 171.6h1.6z"/>
<path d="M204.5 171.6v.4z"/>
<path d="M204.5 172l-1.6 1.5z"/>
<path d="M202.9 173.5v.4z"/>
<path d="M206.4 171.6v2.3z"/>
<path d="M206.4 171.6l-1.2 1.2z"/>
<path d="M205.2 172.8h1.6z"/>
<path d="M207.6 171.6v2.3z"/>
<path d="M207.6 172.8h1.5z"/>
<path d="M209.1 171.6v2.3z"/>
<path d="M211.1 171.6l.4 .4z"/>
<path d="M210.3 171.6h.8z"/>
<path d="M209.9 172l.4-.4z"/>
<path d="M209.9 172v1.5z"/>
<path d="M209.9 173.5l.4 .4z"/>
<path d="M210.3 173.9h.8z"/>
<path d="M211.1 173.9l.4-.4z"/>
<path d="M212.3 171.6h1.5z"/>
<path d="M212.3 171.6v1.2z"/>
<path d="M212.3 172.8l.7-.4z"/>
<path d="M213 172.4h.4z"/>
<path d="M213.4 172.4l.4 .4z"/>
<path d="M213.8 172.8v.7z"/>
<path d="M213.8 173.5l-.4 .4z"/>
<path d="M212.7 173.9h.7z"/>
<path d="M212.3 173.5l.4 .4z"/>
<path d="M214.6 173.5l.4 .4z"/>
<path d="M215 173.9h.8z"/>
<path d="M215.8 173.9l.4-.4z"/>
<path d="M216.2 172v1.5z"/>
<path d="M215.8 171.6l.4 .4z"/>
<path d="M215 171.6h.8z"/>
<path d="M214.6 172l.4-.4z"/>
<path d="M214.6 172v.4z"/>
<path d="M214.6 172.4l.4 .4z"/>
<path d="M215 172.8h1.2z"/>
<path d="M216.9 171.6h1.6z"/>
<path d="M216.9 171.6v1.2z"/>
<path d="M216.9 172.8l.8-.4z"/>
<path d="M217.7 172.4h.4z"/>
<path d="M218.1 172.4l.4 .4z"/>
<path d="M218.5 172.8v.7z"/>
<path d="M218.5 173.5l-.4 .4z"/>
<path d="M217.3 173.9h.8z"/>
<path d="M216.9 173.5l.4 .4z"/>
<path d="M221.6 171.6v2.3z"/>
<path d="M221.6 173.9h1.2z"/>
<path d="M222.8 173.9l.4-.4z"/>
<path d="M223.2 172.8v.7z"/>
<path d="M222.8 172.4l.4 .4z"/>
<path d="M221.6 172.4h1.2z"/>
<path d="M224.3 173.9h.8z"/>
<path d="M225.1 173.9l.4-.4z"/>
<path d="M225.5 172.8v.7z"/>
<path d="M225.1 172.4l.4 .4z"/>
<path d="M224.3 172.4h.8z"/>
<path d="M224.3 172.4l-.3 .4z"/>
<path d="M224 172.8v.7z"/>
<path d="M224 173.5l.3 .4z"/>
<path d="M226.7 172.4h.8z"/>
<path d="M227.5 172.4l.4 .4z"/>
<path d="M227.9 172.8v1.1z"/>
<path d="M226.7 173.9h1.2z"/>
<path d="M226.3 173.5l.4 .4z"/>
<path d="M226.3 173.5l.4-.3z"/>
<path d="M226.7 173.2h1.2z"/>
<path d="M228.6 172.4v1.5z"/>
<path d="M228.6 173.2l.8-.8z"/>
<path d="M229.4 172.4h.4z"/>
<path d="M232.1 171.6v2.3z"/>
<path d="M231 173.9h1.1z"/>
<path d="M230.6 173.5l.4 .4z"/>
<path d="M230.6 172.8v.7z"/>
<path d="M230.6 172.8l.4-.4z"/>
<path d="M231 172.4h1.1z"/>
<path d="M181.1 177.5v1.1z"/>
<path d="M181.1 178.6l.4 .4z"/>
<path d="M181.5 179l.4-.4z"/>
<path d="M181.9 178.6l.4 .4z"/>
<path d="M182.3 179l.3-.4z"/>
<path d="M182.6 177.5v1.1z"/>
<path d="M183.4 177.5h.4z"/>
<path d="M183.8 177.5v1.5z"/>
<path d="M183.4 179h.8z"/>
<path d="M183.8 176.3v.4z"/>
<path d="M185.4 177.1v1.5z"/>
<path d="M185.4 178.6l.4 .4z"/>
<path d="M185 177.5h.8z"/>
<path d="M186.5 176.7v2.3z"/>
<path d="M186.5 177.8l.4-.3z"/>
<path d="M186.9 177.5h.8z"/>
<path d="M187.7 177.5l.4 .3z"/>
<path d="M188.1 177.8v1.2z"/>
<path d="M191.2 179h1.2z"/>
<path d="M192.4 179l.4-.4z"/>
<path d="M192.4 178.2l.4 .4z"/>
<path d="M191.6 178.2h.8z"/>
<path d="M191.2 177.8l.4 .4z"/>
<path d="M191.2 177.8l.4-.3z"/>
<path d="M191.6 177.5h1.2z"/>
<path d="M193.9 177.5h1.2z"/>
<path d="M193.9 177.5l-.3 .3z"/>
<path d="M193.6 177.8v.8z"/>
<path d="M193.6 178.6l.3 .4z"/>
<path d="M193.9 179h1.2z"/>
<path d="M195.9 177.5v1.5z"/>
<path d="M195.9 178.2l.8-.7z"/>
<path d="M196.7 177.5h.4z"/>
<path d="M198.2 179h.8z"/>
<path d="M197.8 178.6l.4 .4z"/>
<path d="M197.8 177.8v.8z"/>
<path d="M197.8 177.8l.4-.3z"/>
<path d="M198.2 177.5h.8z"/>
<path d="M199 177.5l.4 .3z"/>
<path d="M199.4 177.8v.4z"/>
<path d="M197.8 178.2h1.6z"/>
<path d="M200.2 177.5v1.1z"/>
<path d="M200.2 178.6l.4 .4z"/>
<path d="M200.6 179l.4-.4z"/>
<path d="M201 178.6l.4 .4z"/>
<path d="M201.4 179l.3-.4z"/>
<path d="M201.7 177.5v1.1z"/>
<path d="M205.2 179h.8z"/>
<path d="M206 179l.4-.4z"/>
<path d="M206.4 177.8v.8z"/>
<path d="M206 177.5l.4 .3z"/>
<path d="M205.2 177.5h.8z"/>
<path d="M205.2 177.5l-.3 .3z"/>
<path d="M204.9 177.8v.8z"/>
<path d="M204.9 178.6l.3 .4z"/>
<path d="M207.2 177.5v1.1z"/>
<path d="M207.2 178.6l.4 .4z"/>
<path d="M207.6 179h1.2z"/>
<path d="M208.8 177.5v1.5z"/>
<path d="M209.9 177.1v1.5z"/>
<path d="M209.9 178.6l.4 .4z"/>
<path d="M209.5 177.5h.8z"/>
<path d="M211.1 177.5v2.3z"/>
<path d="M211.1 177.5h1.2z"/>
<path d="M212.3 177.5l.4 .3z"/>
<path d="M212.7 177.8v.8z"/>
<path d="M212.3 179l.4-.4z"/>
<path d="M211.1 179h1.2z"/>
<path d="M213.4 177.5v1.1z"/>
<path d="M213.4 178.6l.4 .4z"/>
<path d="M213.8 179h1.2z"/>
<path d="M215 177.5v1.5z"/>
<path d="M216.2 177.1v1.5z"/>
<path d="M216.2 178.6l.4 .4z"/>
<path d="M215.8 177.5h.8z"/>
<path d="M217.3 179h1.2z"/>
<path d="M218.5 179l.4-.4z"/>
<path d="M218.5 178.2l.4 .4z"/>
<path d="M217.7 178.2h.8z"/>
<path d="M217.3 177.8l.4 .4z"/>
<path d="M217.3 177.8l.4-.3z"/>
<path d="M217.7 177.5h1.2z"/>
<path d="M188.7 185v1.6z"/>
<path d="M188.7 185.8l.3-.2z"/>
<path d="M189 185.6h.5z"/>
<path d="M189.5 185.6l.3 .2z"/>
<path d="M189.8 185.8v.8z"/>
<path d="M190.6 185.3v1.1z"/>
<path d="M190.6 186.4l.3 .2z"/>
<path d="M190.3 185.6h.6z"/>
<path d="M191.7 185.3v1.1z"/>
<path d="M191.7 186.4l.3 .2z"/>
<path d="M191.4 185.6h.6z"/>
<path d="M192.5 185.6v1.6z"/>
<path d="M192.5 185.6h.8z"/>
<path d="M193.3 185.6l.3 .2z"/>
<path d="M193.6 185.8v.6z"/>
<path d="M193.3 186.6l.3-.2z"/>
<path d="M192.5 186.6h.8z"/>
<path d="M194.1 185.6h.3z"/>
<path d="M194.4 185.6v.2z"/>
<path d="M194.1 185.8h.3z"/>
<path d="M194.1 185.6v.2z"/>
<path d="M194.1 186.4h.3z"/>
<path d="M194.4 186.4v.2z"/>
<path d="M194.1 186.6h.3z"/>
<path d="M194.1 186.4v.2z"/>
<path d="M196 185l-1 1.6z"/>
<path d="M197.7 185l-1.1 1.6z"/>
<path d="M198.2 185.6v.8z"/>
<path d="M198.2 186.4l.3 .2z"/>
<path d="M198.5 186.6l.3-.2z"/>
<path d="M198.8 186.4l.2 .2z"/>
<path d="M199 186.6l.3-.2z"/>
<path d="M199.3 185.6v.8z"/>
<path d="M199.9 185.6v.8z"/>
<path d="M199.9 186.4l.2 .2z"/>
<path d="M200.1 186.6l.3-.2z"/>
<path d="M200.4 186.4l.3 .2z"/>
<path d="M200.7 186.6l.3-.2z"/>
<path d="M201 185.6v.8z"/>
<path d="M201.5 185.6v.8z"/>
<path d="M201.5 186.4l.3 .2z"/>
<path d="M201.8 186.6l.3-.2z"/>
<path d="M202.1 186.4l.2 .2z"/>
<path d="M202.3 186.6l.3-.2z"/>
<path d="M202.6 185.6v.8z"/>
<path d="M203.1 186.4v.2z"/>
<path d="M203.1 186.4h.3z"/>
<path d="M203.4 186.4v.2z"/>
<path d="M203.1 186.6h.3z"/>
<path d="M204 185.6h.2z"/>
<path d="M204.2 185.6v1z"/>
<path d="M204 186.6h.5z"/>
<path d="M204.2 184.8v.2z"/>
<path d="M205.3 185.6h.8z"/>
<path d="M205.3 185.6l-.2 .2z"/>
<path d="M205.1 185.8v.6z"/>
<path d="M205.1 186.4l.2 .2z"/>
<path d="M205.3 186.6h.8z"/>
<path d="M207 185.6h.5z"/>
<path d="M207.5 185.6l.3 .2z"/>
<path d="M207.8 185.8v.8z"/>
<path d="M207 186.6h.8z"/>
<path d="M206.7 186.4l.3 .2z"/>
<path d="M206.7 186.4l.3-.3z"/>
<path d="M207 186.1h.8z"/>
<path d="M208.3 185.6v1z"/>
<path d="M208.3 185.6h.8z"/>
<path d="M209.1 185.6l.3 .2z"/>
<path d="M209.4 185.8v.8z"/>
<path d="M210 185.6v1z"/>
<path d="M210 185.6h.2z"/>
<path d="M210.2 185.6l.3 .2z"/>
<path d="M210.5 185.8v.8z"/>
<path d="M210.5 185.8l.3-.2z"/>
<path d="M210.8 185.6l.2 .2z"/>
<path d="M211 185.8v.8z"/>
<path d="M211.9 185.6h.5z"/>
<path d="M212.4 185.6l.3 .2z"/>
<path d="M212.7 185.8v.8z"/>
<path d="M211.9 186.6h.8z"/>
<path d="M211.6 186.4l.3 .2z"/>
<path d="M211.6 186.4l.3-.3z"/>
<path d="M211.9 186.1h.8z"/>
<path d="M213.2 185v1.6z"/>
<path d="M213.2 186.1l.9 .5z"/>
<path d="M213.2 186.1l.9-.5z"/>
<path d="M214.9 186.6h.5z"/>
<path d="M214.6 186.4l.3 .2z"/>
<path d="M214.6 185.8v.6z"/>
<path d="M214.9 185.6l-.3 .2z"/>
<path d="M214.9 185.6h.5z"/>
<path d="M215.4 185.6l.3 .2z"/>
<path d="M215.7 185.8v.3z"/>
<path d="M214.6 186.1h1.1z"/>
<path d="M216.2 185.6h.3z"/>
<path d="M216.5 185.6v1z"/>
<path d="M216.2 186.6h.6z"/>
<path d="M216.5 184.8v.2z"/>
<path d="M217.6 185.3v1.1z"/>
<path d="M217.6 186.4l.3 .2z"/>
<path d="M217.3 185.6h.6z"/>
<path d="M218.4 186.4v.2z"/>
<path d="M218.4 186.4h.3z"/>
<path d="M218.7 186.4v.2z"/>
<path d="M218.4 186.6h.3z"/>
<path d="M220.3 185v1.6z"/>
<path d="M219.5 186.6h.8z"/>
<path d="M219.2 186.4l.3 .2z"/>
<path d="M219.2 185.8v.6z"/>
<path d="M219.2 185.8l.3-.2z"/>
<path d="M219.5 185.6h.8z"/>
<path d="M221.1 186.6h.6z"/>
<path d="M220.9 186.4l.2 .2z"/>
<path d="M220.9 185.8v.6z"/>
<path d="M220.9 185.8l.2-.2z"/>
<path d="M221.1 185.6h.6z"/>
<path d="M221.7 185.6l.2 .2z"/>
<path d="M221.9 185.8v.3z"/>
<path d="M220.9 186.1h1z"/>
<path d="M186.1 182.5v1.6z"/>
<path d="M186.1 183.3l.3-.3z"/>
<path d="M186.4 183h.6z"/>
<path d="M187 183l.2 .3z"/>
<path d="M187.2 183.3v.8z"/>
<path d="M188 182.7v1.2z"/>
<path d="M188 183.9l.3 .2z"/>
<path d="M187.8 183h.5z"/>
<path d="M189.1 182.7v1.2z"/>
<path d="M189.1 183.9l.3 .2z"/>
<path d="M188.9 183h.5z"/>
<path d="M190 183v1.7z"/>
<path d="M190 183h.8z"/>
<path d="M190.8 183l.2 .3z"/>
<path d="M191 183.3v.6z"/>
<path d="M191 183.9l-.2 .2z"/>
<path d="M190 184.1h.8z"/>
<path d="M191.6 184.1h.8z"/>
<path d="M192.7 183.9l-.3 .2z"/>
<path d="M192.4 183.6l.3 .3z"/>
<path d="M191.9 183.6h.5z"/>
<path d="M191.6 183.3l.3 .3z"/>
<path d="M191.6 183.3l.3-.3z"/>
<path d="M191.9 183h.8z"/>
<path d="M193.2 183h.3z"/>
<path d="M193.5 183v.3z"/>
<path d="M193.2 183.3h.3z"/>
<path d="M193.2 183v.3z"/>
<path d="M193.2 183.9h.3z"/>
<path d="M193.5 183.9v.2z"/>
<path d="M193.2 184.1h.3z"/>
<path d="M193.2 183.9v.2z"/>
<path d="M195.1 182.5l-1 1.6z"/>
<path d="M196.8 182.5l-1.1 1.6z"/>
<path d="M197.9 184.7h.2z"/>
<path d="M198.1 184.7l.3-.3z"/>
<path d="M198.4 183v1.4z"/>
<path d="M197.6 183h.8z"/>
<path d="M197.6 183l-.3 .3z"/>
<path d="M197.3 183.3v.6z"/>
<path d="M197.3 183.9l.3 .2z"/>
<path d="M197.6 184.1h.8z"/>
<path d="M199 183h.2z"/>
<path d="M199.2 183v1.1z"/>
<path d="M199 184.1h.5z"/>
<path d="M199.2 182.2v.3z"/>
<path d="M200.3 182.7v1.2z"/>
<path d="M200.3 183.9l.3 .2z"/>
<path d="M200.1 183h.5z"/>
<path d="M201.1 182.5v1.6z"/>
<path d="M201.1 183.3l.3-.3z"/>
<path d="M201.4 183h.6z"/>
<path d="M202 183l.2 .3z"/>
<path d="M202.2 183.3v.8z"/>
<path d="M202.8 183v.9z"/>
<path d="M202.8 183.9l.2 .2z"/>
<path d="M203 184.1h.9z"/>
<path d="M203.9 183v1.1z"/>
<path d="M204.4 182.5v1.6z"/>
<path d="M204.4 184.1h.8z"/>
<path d="M205.2 184.1l.3-.2z"/>
<path d="M205.5 183.3v.6z"/>
<path d="M205.2 183l.3 .3z"/>
<path d="M204.4 183h.8z"/>
<path d="M206.1 183.9v.2z"/>
<path d="M206.1 183.9h.2z"/>
<path d="M206.3 183.9v.2z"/>
<path d="M206.1 184.1h.2z"/>
<path d="M207.2 183h.8z"/>
<path d="M207.2 183l-.3 .3z"/>
<path d="M206.9 183.3v.6z"/>
<path d="M206.9 183.9l.3 .2z"/>
<path d="M207.2 184.1h.8z"/>
<path d="M208.8 184.1h.5z"/>
<path d="M209.6 183.9l-.3 .2z"/>
<path d="M209.6 183.3v.6z"/>
<path d="M209.3 183l.3 .3z"/>
<path d="M208.8 183h.5z"/>
<path d="M208.8 183l-.3 .3z"/>
<path d="M208.5 183.3v.6z"/>
<path d="M208.5 183.9l.3 .2z"/>
<path d="M210.1 183v1.1z"/>
<path d="M210.1 183h.3z"/>
<path d="M210.4 183l.3 .3z"/>
<path d="M210.7 183.3v.8z"/>
<path d="M210.7 183.3l.3-.3z"/>
<path d="M211 183l.2 .3z"/>
<path d="M211.2 183.3v.8z"/>
<path d="M212.9 182.5l-1.1 1.6z"/>
<path d="M213.4 182.5v1.6z"/>
<path d="M213.4 183.3l.3-.3z"/>
<path d="M213.7 183h.5z"/>
<path d="M214.2 183l.3 .3z"/>
<path d="M214.5 183.3v.8z"/>
<path d="M215 183v1.1z"/>
<path d="M215 183h.3z"/>
<path d="M215.3 183l.3 .3z"/>
<path d="M215.6 183.3v.8z"/>
<path d="M215.6 183.3l.3-.3z"/>
<path d="M215.9 183l.3 .3z"/>
<path d="M216.2 183.3v.8z"/>
<path d="M216.7 182.5v1.6z"/>
<path d="M216.7 184.1h.8z"/>
<path d="M217.5 184.1l.3-.2z"/>
<path d="M217.8 183.3v.6z"/>
<path d="M217.5 183l.3 .3z"/>
<path d="M216.7 183h.8z"/>
<path d="M218.3 183v.9z"/>
<path d="M218.3 183.9l.3 .2z"/>
<path d="M218.6 184.1h.8z"/>
<path d="M219.4 183v1.1z"/>
<path d="M220 184.1h.8z"/>
<path d="M221.1 183.9l-.3 .2z"/>
<path d="M220.8 183.6l.3 .3z"/>
<path d="M220.2 183.6h.6z"/>
<path d="M220 183.3l.2 .3z"/>
<path d="M220 183.3l.2-.3z"/>
<path d="M220.2 183h.9z"/>
<path d="M221.9 183h.8z"/>
<path d="M221.9 183l-.3 .3z"/>
<path d="M221.6 183.3v.6z"/>
<path d="M221.6 183.9l.3 .2z"/>
<path d="M221.9 184.1h.8z"/>
<path d="M223.2 182.5v1.6z"/>
<path d="M223.2 183.3l.3-.3z"/>
<path d="M223.5 183h.6z"/>
<path d="M224.1 183l.2 .3z"/>
<path d="M224.3 183.3v.8z"/>
<path d="M226 182.5l-1.1 1.6z"/>
<path d="M115 141h5z"/>
<path d="M115 143.6h5z"/>
<path d="M115 146.1h5z"/>
<path d="M115 148.6h5z"/>
<path d="M115 151.2h5z"/>
<path d="M115 153.7h5z"/>
<path d="M115 156.2h5z"/>
<path d="M94.6 146.1h3.1z"/>
<path d="M99.7 142.6l2 1z"/>
<path d="M99.7 144.5l2-.9z"/>
<path d="M94.6 143.6h5.1z"/>
<path d="M99.7 150.2l2 1z"/>
<path d="M99.7 152.2l2-1z"/>
<path d="M94.6 151.2h5.1z"/>
<path d="M94.6 161.3h3.1z"/>
<path d="M94.6 138.5h5.1z"/>
<path d="M115 138.5h5z"/>
<path d="M115 161.3h5z"/>
<path d="M56.6 151.2v5z"/>
<path d="M56.6 141v5.1z"/>
<path d="M56.6 163.9v2.5z"/>
<path d="M48.9 57.2v2.6z"/>
<path d="M56.6 128.3v2.6z"/>
<path d="M48.9 31.8v2.6z"/>
<path d="M38.2 42h.6z"/>
<path d="M38.2 44.5h.6z"/>
<path d="M38.2 47.1h.6z"/>
<path d="M38.2 49.6h.6z"/>
<path d="M38.2 52.1h.6z"/>
<path d="M79.4 42h.6z"/>
<path d="M79.4 44.5h.6z"/>
<path d="M79.4 47.1h.6z"/>
<path d="M79.4 49.6h.6z"/>
<path d="M79.4 52.1h.6z"/>
<path d="M89.6 163.9v2.5z"/>
<path d="M89.6 128.3v2.6z"/>
<path d="M275 185.5v5z"/>
<path d="M275 180.4v5.1z"/>
<path d="M275 175.3v5.1z"/>
<path d="M275 170.2v5.1z"/>
<path d="M179.7 170.2v20.3z"/>
<path d="M179.7 170.2h54z"/>
<path d="M233.7 170.2h41.3z"/>
<path d="M264.8 185.5v5z"/>
<path d="M264.8 185.5h10.2z"/>
<path d="M233.7 185.5h31.1z"/>
<path d="M233.7 185.5v5z"/>
<path d="M233.7 180.4v5.1z"/>
<path d="M233.7 180.4h41.3z"/>
<path d="M233.7 175.3v5.1z"/>
<path d="M233.7 175.3h41.3z"/>
<path d="M233.7 170.2v5.1z"/>
<path d="M236.9 176.7l.4 .4z"/>
<path d="M236.1 176.7h.8z"/>
<path d="M235.7 177.1l.4-.4z"/>
<path d="M235.7 177.1v1.5z"/>
<path d="M235.7 178.6l.4 .4z"/>
<path d="M236.1 179h.8z"/>
<path d="M236.9 179l.4-.4z"/>
<path d="M238 176.7v2.3z"/>
<path d="M238 177.8l.4-.3z"/>
<path d="M238.4 177.5h.8z"/>
<path d="M239.2 177.5l.4 .3z"/>
<path d="M239.6 177.8v1.2z"/>
<path d="M240.7 177.5h.8z"/>
<path d="M241.5 177.5l.4 .3z"/>
<path d="M241.9 177.8v1.2z"/>
<path d="M240.7 179h1.2z"/>
<path d="M240.4 178.6l.3 .4z"/>
<path d="M240.4 178.6l.3-.4z"/>
<path d="M240.7 178.2h1.2z"/>
<path d="M242.7 177.5h.4z"/>
<path d="M243.1 177.5v1.5z"/>
<path d="M242.7 179h.8z"/>
<path d="M243.1 176.3v.4z"/>
<path d="M244.3 177.5v1.5z"/>
<path d="M244.3 177.5h1.1z"/>
<path d="M245.4 177.5l.4 .3z"/>
<path d="M245.8 177.8v1.2z"/>
<path d="M247 177.5h.8z"/>
<path d="M247.8 177.5l.4 .3z"/>
<path d="M248.2 177.8v1.2z"/>
<path d="M247 179h1.2z"/>
<path d="M246.6 178.6l.4 .4z"/>
<path d="M247 178.2l-.4 .4z"/>
<path d="M247 178.2h1.2z"/>
<path d="M248.9 176.7v2.3z"/>
<path d="M248.9 179h1.2z"/>
<path d="M250.1 179l.4-.4z"/>
<path d="M250.5 177.8v.8z"/>
<path d="M250.1 177.5l.4 .3z"/>
<path d="M248.9 177.5h1.2z"/>
<path d="M251.3 176.7h.4z"/>
<path d="M251.7 176.7v2.3z"/>
<path d="M251.3 179h.7z"/>
<path d="M253.2 179h.8z"/>
<path d="M252.8 178.6l.4 .4z"/>
<path d="M252.8 177.8v.8z"/>
<path d="M252.8 177.8l.4-.3z"/>
<path d="M253.2 177.5h.8z"/>
<path d="M254 177.5l.4 .3z"/>
<path d="M254.4 177.8v.4z"/>
<path d="M252.8 178.2h1.6z"/>
<path d="M256.3 176.7l.4 .4z"/>
<path d="M255.6 176.7h.7z"/>
<path d="M255.6 176.7l-.4 .4z"/>
<path d="M255.2 177.1v.4z"/>
<path d="M255.2 177.5l.4 .3z"/>
<path d="M255.6 177.8h.7z"/>
<path d="M256.3 177.8l.4 .4z"/>
<path d="M256.7 178.2v.4z"/>
<path d="M256.7 178.6l-.4 .4z"/>
<path d="M255.6 179h.7z"/>
<path d="M255.2 178.6l.4 .4z"/>
<path d="M257.9 177.5h1.2z"/>
<path d="M257.5 177.8l.4-.3z"/>
<path d="M257.5 177.8v.8z"/>
<path d="M257.5 178.6l.4 .4z"/>
<path d="M257.9 179h1.2z"/>
<path d="M259.9 177.5v1.5z"/>
<path d="M260.6 177.5l-.7 .7z"/>
<path d="M260.6 177.5h.4z"/>
<path d="M262.2 179h.8z"/>
<path d="M261.8 178.6l.4 .4z"/>
<path d="M261.8 177.8v.8z"/>
<path d="M261.8 177.8l.4-.3z"/>
<path d="M262.2 177.5h.8z"/>
<path d="M263 177.5l.4 .3z"/>
<path d="M263.4 177.8v.4z"/>
<path d="M261.8 178.2h1.6z"/>
<path d="M264.1 177.5v1.1z"/>
<path d="M264.1 178.6l.4 .4z"/>
<path d="M264.5 179l.4-.4z"/>
<path d="M264.9 178.6l.4 .4z"/>
<path d="M265.3 179l.4-.4z"/>
<path d="M265.7 177.5v1.1z"/>
<path d="M266.5 176.7h1.5z"/>
<path d="M266.5 176.7v1.1z"/>
<path d="M266.5 177.8l.7-.3z"/>
<path d="M267.2 177.5h.4z"/>
<path d="M267.6 177.5l.4 .3z"/>
<path d="M268 177.8v.8z"/>
<path d="M268 178.6l-.4 .4z"/>
<path d="M266.9 179h.7z"/>
<path d="M266.5 178.6l.4 .4z"/>
<path d="M268.8 178.6l.4 .4z"/>
<path d="M269.2 179h.8z"/>
<path d="M270 179l.4-.4z"/>
<path d="M270.4 177.1v1.5z"/>
<path d="M270 176.7l.4 .4z"/>
<path d="M269.2 176.7h.8z"/>
<path d="M268.8 177.1l.4-.4z"/>
<path d="M268.8 177.1v.4z"/>
<path d="M268.8 177.5l.4 .3z"/>
<path d="M269.2 177.8h1.2z"/>
<path d="M271.2 176.7h1.5z"/>
<path d="M271.2 176.7v1.1z"/>
<path d="M271.2 177.8l.7-.3z"/>
<path d="M271.9 177.5h.4z"/>
<path d="M272.3 177.5l.4 .3z"/>
<path d="M272.7 177.8v.8z"/>
<path d="M272.3 179l.4-.4z"/>
<path d="M271.5 179h.8z"/>
<path d="M271.2 178.6l.3 .4z"/>
<path d="M235.7 182.7l.7-.7z"/>
<path d="M236.4 182v2.1z"/>
<path d="M235.7 184.1h1.4z"/>
<path d="M237.8 182.3l.3-.3z"/>
<path d="M238.1 182h.7z"/>
<path d="M238.8 182l.4 .3z"/>
<path d="M239.2 182.3v.4z"/>
<path d="M239.2 182.7l-.4 .3z"/>
<path d="M238.8 183l.4 .4z"/>
<path d="M239.2 183.4v.3z"/>
<path d="M239.2 183.7l-.4 .4z"/>
<path d="M238.1 184.1h.7z"/>
<path d="M237.8 183.7l.3 .4z"/>
<path d="M237.8 183.4v.3z"/>
<path d="M237.8 183.4l.3-.4z"/>
<path d="M237.8 182.7l.3 .3z"/>
<path d="M237.8 182.3v.4z"/>
<path d="M238.1 183h.7z"/>
<path d="M239.9 183.7v.4z"/>
<path d="M239.9 183.7h.3z"/>
<path d="M240.2 183.7v.4z"/>
<path d="M239.9 184.1h.3z"/>
<path d="M240.9 182.3v1.4z"/>
<path d="M240.9 182.3l.4-.3z"/>
<path d="M241.3 182h.7z"/>
<path d="M242 182l.4 .3z"/>
<path d="M242.4 182.3v1.4z"/>
<path d="M242.4 183.7l-.4 .4z"/>
<path d="M241.3 184.1h.7z"/>
<path d="M240.9 183.7l.4 .4z"/>
<path d="M240.9 183.7l1.5-1.4z"/>
<path d="M243.4 182l-.3 .3z"/>
<path d="M243.4 182h.7z"/>
<path d="M244.1 182l.3 .3z"/>
<path d="M244.4 182.3v.4z"/>
<path d="M244.4 182.7l-.3 .3z"/>
<path d="M244.1 183l.3 .4z"/>
<path d="M244.4 183.4v.3z"/>
<path d="M244.4 183.7l-.3 .4z"/>
<path d="M243.4 184.1h.7z"/>
<path d="M243.1 183.7l.3 .4z"/>
<path d="M243.1 183.4v.3z"/>
<path d="M243.4 183l-.3 .4z"/>
<path d="M243.1 182.7l.3 .3z"/>
<path d="M243.1 182.3v.4z"/>
<path d="M243.4 183h.7z"/>
<path d="M245.1 183.7v.4z"/>
<path d="M245.1 183.7h.4z"/>
<path d="M245.5 183.7v.4z"/>
<path d="M245.1 184.1h.4z"/>
<path d="M246.2 182.7l.7-.7z"/>
<path d="M246.9 182v2.1z"/>
<path d="M246.2 184.1h1.4z"/>
<path d="M248.3 182.7l.7-.7z"/>
<path d="M249 182v2.1z"/>
<path d="M248.3 184.1h1.4z"/>
<path d="M252.5 182.3v1.4z"/>
<path d="M252.5 182.3l.4-.3z"/>
<path d="M252.9 182h.7z"/>
<path d="M253.6 182l.3 .3z"/>
<path d="M253.9 182.3v1.4z"/>
<path d="M253.9 183.7l-.3 .4z"/>
<path d="M252.9 184.1h.7z"/>
<path d="M252.5 183.7l.4 .4z"/>
<path d="M252.5 183.7l1.4-1.4z"/>
<path d="M254.6 182.3v1.4z"/>
<path d="M254.6 182.3l.4-.3z"/>
<path d="M255 182h.7z"/>
<path d="M255.7 182l.3 .3z"/>
<path d="M256 182.3v1.4z"/>
<path d="M256 183.7l-.3 .4z"/>
<path d="M255 184.1h.7z"/>
<path d="M254.6 183.7l.4 .4z"/>
<path d="M254.6 183.7l1.4-1.4z"/>
<path d="M256.7 182.7h.4z"/>
<path d="M257.1 182.7v.3z"/>
<path d="M256.7 183h.4z"/>
<path d="M256.7 182.7v.3z"/>
<path d="M256.7 183.7h.4z"/>
<path d="M257.1 183.7v.4z"/>
<path d="M256.7 184.1h.4z"/>
<path d="M256.7 183.7v.4z"/>
<path d="M257.8 182.7l.7-.7z"/>
<path d="M258.5 182v2.1z"/>
<path d="M257.8 184.1h1.4z"/>
<path d="M259.9 184.1h1.4z"/>
<path d="M261.3 182.7l-1.4 1.4z"/>
<path d="M261.3 182.3v.4z"/>
<path d="M260.9 182l.4 .3z"/>
<path d="M260.2 182h.7z"/>
<path d="M260.2 182l-.3 .3z"/>
<path d="M249 187.6l.8-.8z"/>
<path d="M249.8 186.8v2.4z"/>
<path d="M249 189.2h1.6z"/>
<path d="M252.9 186.8l-1.6 2.4z"/>
<path d="M253.7 187.6l.8-.8z"/>
<path d="M254.5 186.8v2.4z"/>
<path d="M253.7 189.2h1.6z"/>
<path d="M236.6 187l.4 .3z"/>
<path d="M235.8 187h.8z"/>
<path d="M235.4 187.3l.4-.3z"/>
<path d="M235.4 187.3v.4z"/>
<path d="M235.4 187.7l.4 .4z"/>
<path d="M235.8 188.1h.8z"/>
<path d="M236.6 188.1l.4 .4z"/>
<path d="M237 188.5v.4z"/>
<path d="M236.6 189.3l.4-.4z"/>
<path d="M235.8 189.3h.8z"/>
<path d="M235.4 188.9l.4 .4z"/>
<path d="M237.8 187v2.3z"/>
<path d="M237.8 188.1l.4-.4z"/>
<path d="M238.2 187.7h.7z"/>
<path d="M238.9 187.7l.4 .4z"/>
<path d="M239.3 188.1v1.2z"/>
<path d="M240.5 189.3h.8z"/>
<path d="M240.1 188.9l.4 .4z"/>
<path d="M240.1 188.1v.8z"/>
<path d="M240.1 188.1l.4-.4z"/>
<path d="M240.5 187.7h.8z"/>
<path d="M241.3 187.7l.4 .4z"/>
<path d="M241.7 188.1v.4z"/>
<path d="M240.1 188.5h1.6z"/>
<path d="M242.8 189.3h.8z"/>
<path d="M242.5 188.9l.3 .4z"/>
<path d="M242.5 188.1v.8z"/>
<path d="M242.5 188.1l.3-.4z"/>
<path d="M242.8 187.7h.8z"/>
<path d="M243.6 187.7l.4 .4z"/>
<path d="M244 188.1v.4z"/>
<path d="M242.5 188.5h1.5z"/>
<path d="M245.2 187.3v1.6z"/>
<path d="M245.2 188.9l.4 .4z"/>
<path d="M244.8 187.7h.8z"/>
<path d="M246.4 187.7h.3z"/>
<path d="M246.7 187.7v.4z"/>
<path d="M246.4 188.1h.3z"/>
<path d="M246.4 187.7v.4z"/>
<path d="M246.4 188.9h.3z"/>
<path d="M246.7 188.9v.4z"/>
<path d="M246.4 189.3h.3z"/>
<path d="M246.4 188.9v.4z"/>
<path d="M22.3 19.1v171.4z"/>
<path d="M18.5 62h3.8z"/>
<path d="M19.2 40.2v1.6z"/>
<path d="M20 39.3l-.8 .9z"/>
<path d="M20 39.3l.8 .9z"/>
<path d="M20.8 40.2v1.6z"/>
<path d="M19.2 40.6h1.6z"/>
<path d="M18.5 104.8h3.8z"/>
<path d="M19.2 82.2v2.4z"/>
<path d="M19.2 82.2h1.2z"/>
<path d="M20.4 82.2l.4 .4z"/>
<path d="M20.8 82.6v.4z"/>
<path d="M20.8 83l-.4 .4z"/>
<path d="M20.4 83.4l.4 .4z"/>
<path d="M20.8 83.8v.4z"/>
<path d="M20.8 84.2l-.4 .4z"/>
<path d="M19.2 84.6h1.2z"/>
<path d="M19.2 83.4h1.2z"/>
<path d="M18.5 147.7h3.8z"/>
<path d="M20.4 125.1l.4 .4z"/>
<path d="M19.6 125.1h.8z"/>
<path d="M19.6 125.1l-.4 .4z"/>
<path d="M19.2 125.5v1.6z"/>
<path d="M19.2 127.1l.4 .4z"/>
<path d="M19.6 127.5h.8z"/>
<path d="M20.4 127.5l.4-.4z"/>
<path d="M19.2 167.9v2.4z"/>
<path d="M19.2 170.3h1.2z"/>
<path d="M20.4 170.3l.4-.4z"/>
<path d="M20.8 168.3v1.6z"/>
<path d="M20.4 167.9l.4 .4z"/>
<path d="M19.2 167.9h1.2z"/>
<path d="M22.3 190.5h252.7z"/>
<path d="M64.4 190.5v3.8z"/>
<path d="M42.1 192l.8-.8z"/>
<path d="M42.9 191.2v2.5z"/>
<path d="M42.1 193.7h1.6z"/>
<path d="M106.5 190.5v3.8z"/>
<path d="M84.2 193.7h1.6z"/>
<path d="M85.8 192l-1.6 1.7z"/>
<path d="M85.8 191.6v.4z"/>
<path d="M85.4 191.2l.4 .4z"/>
<path d="M84.6 191.2h.8z"/>
<path d="M84.6 191.2l-.4 .4z"/>
<path d="M148.6 190.5v3.8z"/>
<path d="M126.3 191.6l.4-.4z"/>
<path d="M126.7 191.2h.8z"/>
<path d="M127.5 191.2l.5 .4z"/>
<path d="M128 191.6v.4z"/>
<path d="M128 192l-.5 .4z"/>
<path d="M127.1 192.4h.4z"/>
<path d="M127.5 192.4l.5 .4z"/>
<path d="M128 192.8v.4z"/>
<path d="M128 193.2l-.5 .5z"/>
<path d="M126.7 193.7h.8z"/>
<path d="M126.3 193.2l.4 .5z"/>
<path d="M190.7 190.5v3.8z"/>
<path d="M169.7 191.2v2.5z"/>
<path d="M169.7 191.2l-1.2 1.2z"/>
<path d="M168.5 192.4h1.6z"/>
<path d="M232.8 190.5v3.8z"/>
<path d="M210.6 191.2h1.6z"/>
<path d="M210.6 191.2v1.2z"/>
<path d="M210.6 192.4l.8-.4z"/>
<path d="M211.4 192h.4z"/>
<path d="M211.8 192l.4 .4z"/>
<path d="M212.2 192.4v.8z"/>
<path d="M212.2 193.2l-.4 .5z"/>
<path d="M211 193.7h.8z"/>
<path d="M210.6 193.2l.4 .5z"/>
<path d="M253.5 191.6l.8-.4z"/>
<path d="M253.5 191.6l-.8 .8z"/>
<path d="M252.7 192.4v.8z"/>
<path d="M252.7 193.2l.4 .5z"/>
<path d="M253.1 193.7h.8z"/>
<path d="M253.9 193.7l.4-.5z"/>
<path d="M254.3 192.8v.4z"/>
<path d="M253.9 192.4l.4 .4z"/>
<path d="M252.7 192.4h1.2z"/>
<path d="M275 19.1v171.4z"/>
<path d="M275 62h3.8z"/>
<path d="M275.6 40.2v1.6z"/>
<path d="M275.6 40.2l.9-.9z"/>
<path d="M276.5 39.3l.8 .9z"/>
<path d="M277.3 40.2v1.6z"/>
<path d="M275.6 40.6h1.7z"/>
<path d="M275 104.8h3.8z"/>
<path d="M275.6 82.2v2.4z"/>
<path d="M275.6 82.2h1.3z"/>
<path d="M276.9 82.2l.4 .4z"/>
<path d="M277.3 82.6v.4z"/>
<path d="M276.9 83.4l.4-.4z"/>
<path d="M276.9 83.4l.4 .4z"/>
<path d="M277.3 83.8v.4z"/>
<path d="M277.3 84.2l-.4 .4z"/>
<path d="M275.6 84.6h1.3z"/>
<path d="M275.6 83.4h1.3z"/>
<path d="M275 147.7h3.8z"/>
<path d="M276.9 125.1l.4 .4z"/>
<path d="M276.1 125.1h.8z"/>
<path d="M275.6 125.5l.5-.4z"/>
<path d="M275.6 125.5v1.6z"/>
<path d="M275.6 127.1l.5 .4z"/>
<path d="M276.1 127.5h.8z"/>
<path d="M276.9 127.5l.4-.4z"/>
<path d="M275.6 167.9v2.4z"/>
<path d="M275.6 170.3h1.3z"/>
<path d="M276.9 170.3l.4-.4z"/>
<path d="M277.3 168.3v1.6z"/>
<path d="M276.9 167.9l.4 .4z"/>
<path d="M275.6 167.9h1.3z"/>
<path d="M22.3 19.1h252.7z"/>
<path d="M64.4 15.3v3.8z"/>
<path d="M42.1 16.8l.8-.8z"/>
<path d="M42.9 16v2.4z"/>
<path d="M42.1 18.4h1.6z"/>
<path d="M106.5 15.3v3.8z"/>
<path d="M84.2 18.4h1.6z"/>
<path d="M85.8 16.8l-1.6 1.6z"/>
<path d="M85.8 16.4v.4z"/>
<path d="M85.4 16l.4 .4z"/>
<path d="M84.6 16h.8z"/>
<path d="M84.6 16l-.4 .4z"/>
<path d="M148.6 15.3v3.8z"/>
<path d="M126.3 16.4l.4-.4z"/>
<path d="M126.7 16h.8z"/>
<path d="M127.5 16l.5 .4z"/>
<path d="M128 16.4v.4z"/>
<path d="M128 16.8l-.5 .4z"/>
<path d="M127.1 17.2h.4z"/>
<path d="M127.5 17.2l.5 .4z"/>
<path d="M128 17.6v.4z"/>
<path d="M128 18l-.5 .4z"/>
<path d="M126.7 18.4h.8z"/>
<path d="M126.3 18l.4 .4z"/>
<path d="M190.7 15.3v3.8z"/>
<path d="M169.7 16v2.4z"/>
<path d="M169.7 16l-1.2 1.2z"/>
<path d="M168.5 17.2h1.6z"/>
<path d="M232.8 15.3v3.8z"/>
<path d="M210.6 16h1.6z"/>
<path d="M210.6 16v1.2z"/>
<path d="M210.6 17.2l.8-.4z"/>
<path d="M211.4 16.8h.4z"/>
<path d="M211.8 16.8l.4 .4z"/>
<path d="M212.2 17.2v.8z"/>
<path d="M212.2 18l-.4 .4z"/>
<path d="M211 18.4h.8z"/>
<path d="M210.6 18l.4 .4z"/>
<path d="M253.5 16.4l.8-.4z"/>
<path d="M253.5 16.4l-.8 .8z"/>
<path d="M252.7 17.2v.8z"/>
<path d="M252.7 18l.4 .4z"/>
<path d="M253.1 18.4h.8z"/>
<path d="M253.9 18.4l.4-.4z"/>
<path d="M254.3 17.6v.4z"/>
<path d="M253.9 17.2l.4 .4z"/>
<path d="M252.7 17.2h1.2z"/>
<path d="M132.7 54.7h2.6z"/>
<path d="M132.7 59.8h2.6z"/>
<path d="M132.7 64.8h2.6z"/>
<path d="M132.7 69.9h2.6z"/>
<path d="M132.7 75h2.6z"/>
<path d="M132.7 80.1h2.6z"/>
<path d="M132.7 85.2h2.6z"/>
<path d="M132.7 90.2h2.6z"/>
<path d="M132.7 95.3h2.6z"/>
<path d="M203.9 72.5h5z"/>
<path d="M203.9 75h5z"/>
<path d="M203.9 77.5h5z"/>
<path d="M203.9 80.1h5z"/>
<path d="M203.9 82.6h5z"/>
<path d="M203.9 85.2h5z"/>
<path d="M203.9 87.7h5z"/>
<path d="M203.9 90.2h5z"/>
<path d="M224.2 90.2h5z"/>
<path d="M224.2 72.5h5z"/>
<path d="M224.2 75h5z"/>
<path d="M224.2 77.5h5z"/>
<path d="M224.2 80.1h5z"/>
<path d="M224.2 82.6h5z"/>
<path d="M224.2 85.2h5z"/>
<path d="M224.2 87.7h5z"/>
<path d="M224.2 92.8h5z"/>
<path d="M203.9 92.8h5z"/>
<path d="M188.6 97.9v2.5z"/>
</g>
<g fill="none" stroke="#800000" stroke-width=".21">
<circle cx="37.2" cy="47.1" r=".99"/>
<circle cx="37.2" cy="42" r=".99"/>
<circle cx="37.2" cy="44.5" r=".99"/>
<circle cx="37.2" cy="52.1" r=".99"/>
<circle cx="37.2" cy="49.6" r=".99"/>
<circle cx="81" cy="49.6" r=".99"/>
<circle cx="81" cy="47.1" r=".99"/>
<circle cx="81" cy="52.1" r=".99"/>
<circle cx="81" cy="44.5" r=".99"/>
<circle cx="81" cy="42" r=".99"/>
<circle cx="98.7" cy="146.1" r=".99"/>
<circle cx="98.7" cy="161.3" r=".99"/>
</g>
<g fill="#800000" stroke="#800000" stroke-width=".42">
<path d="M99.7 163.9h15.3z"/>
<path d="M115 136v27.9z"/>
<path d="M99.7 136h15.3z"/>
<path d="M99.7 136v27.9z"/>
<path d="M35 54.7h7.6z"/>
<path d="M35 39.5v15.2z"/>
<path d="M35 39.5h7.6z"/>
<path d="M42.6 39.5v15.2z"/>
<path d="M75.6 54.7h7.6z"/>
<path d="M83.2 39.5v15.2z"/>
<path d="M75.6 39.5h7.6z"/>
<path d="M75.6 39.5v15.2z"/>
<path d="M208.9 69.9h15.3z"/>
<path d="M224.2 69.9v25.4z"/>
<path d="M208.9 95.3h15.3z"/>
<path d="M208.9 69.9v25.4z"/>
</g>
<g fill="#800000" stroke="#800000" stroke-width=".25">
<path d="M54.7 166.4h3.8z"/>
<path d="M47 59.8h3.8z"/>
<path d="M56.6 128.3l1.2 1.9z"/>
<path d="M56.6 128.3l-1.3 1.9z"/>
<path d="M48.9 31.8l1.3 1.9z"/>
<path d="M48.9 31.8l-1.2 1.9z"/>
<path d="M87.6 166.4h3.9z"/>
<path d="M89.6 128.3l1.2 1.9z"/>
<path d="M89.6 128.3l-1.3 1.9z"/>
<path d="M186.7 100.4h3.8z"/>
</g>
<g fill="#800000" stroke="#800000" stroke-width=".32">
<path d="M18.5 15.3v179z"/>
<path d="M18.5 194.3h260.3z"/>
<path d="M278.8 15.3v179z"/>
<path d="M18.5 15.3h260.3z"/>
</g>
<g fill="none" stroke="#800000" stroke-width=".25">
<circle cx="136.5" cy="54.7" r="1.27"/>
<circle cx="136.5" cy="59.8" r="1.27"/>
<circle cx="136.5" cy="75" r="1.27"/>
<circle cx="136.5" cy="69.9" r="1.27"/>
<circle cx="136.5" cy="64.8" r="1.27"/>
<circle cx="136.5" cy="95.3" r="1.27"/>
<circle cx="136.5" cy="90.2" r="1.27"/>
<circle cx="136.5" cy="85.2" r="1.27"/>
<circle cx="136.5" cy="80.1" r="1.27"/>
</g>
<g fill="#008000" stroke="#008000" stroke-width=".21">
<path d="M56.6 130.9v10.1z"/>
<path d="M38.8 42h10.1z"/>
<path d="M48.9 42h30.5z"/>
<path d="M48.9 34.4v7.6z"/>
<path d="M89.6 146.1h5z"/>
<path d="M89.6 130.9v15.2z"/>
<path d="M117.5 95.3h15.2z"/>
<path d="M56.6 156.2v7.7z"/>
<path d="M38.8 44.5h10.1z"/>
<path d="M48.9 44.5h30.5z"/>
<path d="M48.9 44.5v12.7z"/>
<path d="M89.6 161.3v2.6z"/>
<path d="M89.6 161.3h5z"/>
<path d="M188.6 92.8h15.3z"/>
<path d="M188.6 92.8v5.1z"/>
<path d="M38.8 47.1h20.3z"/>
<path d="M59.1 47.1h20.3z"/>
<path d="M59.1 47.1v20.3z"/>
<path d="M74.3 151.2h20.3z"/>
<path d="M38.8 49.6h22.8z"/>
<path d="M61.6 49.6h17.8z"/>
<path d="M61.6 49.6v17.8z"/>
<path d="M74.3 143.6h20.3z"/>
<path d="M38.8 52.1h17.8z"/>
<path d="M56.6 52.1v15.3z"/>
<path d="M74.3 138.5h20.3z"/>
<path d="M64.2 52.1h15.2z"/>
<path d="M64.2 52.1v15.3z"/>
<path d="M120 161.3h20.4z"/>
<path d="M120 138.5h20.4z"/>
<path d="M193.7 72.5h10.2z"/>
<path d="M120 141h20.4z"/>
<path d="M193.7 75h10.2z"/>
<path d="M120 143.6h20.4z"/>
<path d="M193.7 77.5h10.2z"/>
<path d="M120 146.1h20.4z"/>
<path d="M193.7 80.1h10.2z"/>
<path d="M120 148.6h20.4z"/>
<path d="M193.7 82.6h10.2z"/>
<path d="M120 151.2h20.4z"/>
<path d="M193.7 85.2h10.2z"/>
<path d="M120 153.7h20.4z"/>
<path d="M193.7 87.7h10.2z"/>
<path d="M120 156.2h20.4z"/>
<path d="M193.7 90.2h10.2z"/>
<path d="M117.5 54.7h15.2z"/>
<path d="M229.2 72.5h12.7z"/>
<path d="M117.5 59.8h15.2z"/>
<path d="M229.2 75h12.7z"/>
<path d="M117.5 64.8h15.2z"/>
<path d="M229.2 77.5h12.7z"/>
<path d="M117.5 69.9h15.2z"/>
<path d="M229.2 80.1h12.7z"/>
<path d="M117.5 75h15.2z"/>
<path d="M229.2 82.6h12.7z"/>
<path d="M117.5 80.1h15.2z"/>
<path d="M229.2 85.2h12.7z"/>
<path d="M117.5 85.2h15.2z"/>
<path d="M229.2 87.7h12.7z"/>
<path d="M117.5 90.2h15.2z"/>
<path d="M229.2 90.2h12.7z"/>
<circle cx="48.9" cy="42" r=".51"/>
<circle cx="48.9" cy="44.5" r=".51"/>
<circle cx="59.1" cy="47.1" r=".51"/>
<circle cx="61.6" cy="49.6" r=".51"/>
</g>
</svg>
